VERSION 5.8 ;
BUSBITCHARS "[]" ;
DIVIDERCHAR "/" ;
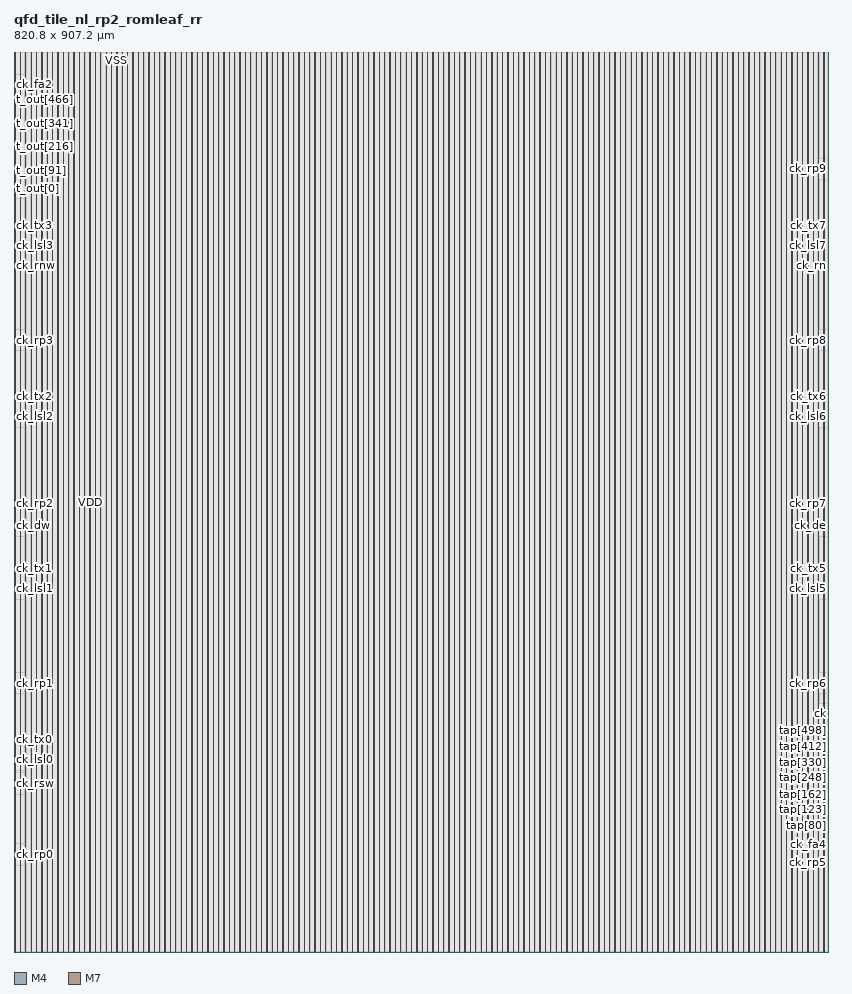
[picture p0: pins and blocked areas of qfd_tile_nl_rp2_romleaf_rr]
MACRO qfd_tile_nl_rp2_romleaf_rr
  CLASS BLOCK ;
  ORIGIN 0 0 ;
  FOREIGN qfd_tile_nl_rp2_romleaf_rr 0 0 ;
  SIZE 820.8 BY 907.2 ;
  SYMMETRY X Y ;
  PIN ck_rp0
    DIRECTION INPUT ;
    USE CLOCK ;
    PORT
      LAYER M4 ;
        RECT 0.000 98.304 0.192 98.328 ;
    END
  END ck_rp0
  PIN ck_rsw
    DIRECTION INPUT ;
    USE CLOCK ;
    PORT
      LAYER M4 ;
        RECT 0.000 170.016 0.192 170.040 ;
    END
  END ck_rsw
  PIN ck_lsl0
    DIRECTION INPUT ;
    USE CLOCK ;
    PORT
      LAYER M4 ;
        RECT 0.000 193.824 0.192 193.848 ;
    END
  END ck_lsl0
  PIN ck_tx0
    DIRECTION INPUT ;
    USE CLOCK ;
    PORT
      LAYER M4 ;
        RECT 0.000 205.824 0.192 205.848 ;
    END
  END ck_tx0
  PIN ck_rp1
    DIRECTION INPUT ;
    USE CLOCK ;
    PORT
      LAYER M4 ;
        RECT 0.000 271.104 0.192 271.128 ;
    END
  END ck_rp1
  PIN ck_lsl1
    DIRECTION INPUT ;
    USE CLOCK ;
    PORT
      LAYER M4 ;
        RECT 0.000 366.624 0.192 366.648 ;
    END
  END ck_lsl1
  PIN ck_tx1
    DIRECTION INPUT ;
    USE CLOCK ;
    PORT
      LAYER M4 ;
        RECT 0.000 378.624 0.192 378.648 ;
    END
  END ck_tx1
  PIN ck_dw
    DIRECTION INPUT ;
    USE CLOCK ;
    PORT
      LAYER M4 ;
        RECT 0.000 429.984 0.192 430.008 ;
    END
  END ck_dw
  PIN ck_rp2
    DIRECTION INPUT ;
    USE CLOCK ;
    PORT
      LAYER M4 ;
        RECT 0.000 443.904 0.192 443.928 ;
    END
  END ck_rp2
  PIN ck_lsl2
    DIRECTION INPUT ;
    USE CLOCK ;
    PORT
      LAYER M4 ;
        RECT 0.000 539.424 0.192 539.448 ;
    END
  END ck_lsl2
  PIN ck_tx2
    DIRECTION INPUT ;
    USE CLOCK ;
    PORT
      LAYER M4 ;
        RECT 0.000 551.424 0.192 551.448 ;
    END
  END ck_tx2
  PIN ck_rp3
    DIRECTION INPUT ;
    USE CLOCK ;
    PORT
      LAYER M4 ;
        RECT 0.000 616.704 0.192 616.728 ;
    END
  END ck_rp3
  PIN ck_rnw
    DIRECTION INPUT ;
    USE CLOCK ;
    PORT
      LAYER M4 ;
        RECT 0.000 700.032 0.192 700.056 ;
    END
  END ck_rnw
  PIN ck_lsl3
    DIRECTION INPUT ;
    USE CLOCK ;
    PORT
      LAYER M4 ;
        RECT 0.000 712.224 0.192 712.248 ;
    END
  END ck_lsl3
  PIN ck_tx3
    DIRECTION INPUT ;
    USE CLOCK ;
    PORT
      LAYER M4 ;
        RECT 0.000 724.224 0.192 724.248 ;
    END
  END ck_tx3
  PIN t_out[0]
    DIRECTION OUTPUT ;
    USE SIGNAL ;
    PORT
      LAYER M4 ;
        RECT 0.000 770.016 0.192 770.040 ;
    END
  END t_out[0]
  PIN t_out[1]
    DIRECTION OUTPUT ;
    USE SIGNAL ;
    PORT
      LAYER M4 ;
        RECT 0.000 770.208 0.192 770.232 ;
    END
  END t_out[1]
  PIN t_out[2]
    DIRECTION OUTPUT ;
    USE SIGNAL ;
    PORT
      LAYER M4 ;
        RECT 0.000 770.400 0.192 770.424 ;
    END
  END t_out[2]
  PIN t_out[3]
    DIRECTION OUTPUT ;
    USE SIGNAL ;
    PORT
      LAYER M4 ;
        RECT 0.000 770.592 0.192 770.616 ;
    END
  END t_out[3]
  PIN t_out[4]
    DIRECTION OUTPUT ;
    USE SIGNAL ;
    PORT
      LAYER M4 ;
        RECT 0.000 770.784 0.192 770.808 ;
    END
  END t_out[4]
  PIN t_out[5]
    DIRECTION OUTPUT ;
    USE SIGNAL ;
    PORT
      LAYER M4 ;
        RECT 0.000 770.976 0.192 771.000 ;
    END
  END t_out[5]
  PIN t_out[6]
    DIRECTION OUTPUT ;
    USE SIGNAL ;
    PORT
      LAYER M4 ;
        RECT 0.000 771.168 0.192 771.192 ;
    END
  END t_out[6]
  PIN t_out[7]
    DIRECTION OUTPUT ;
    USE SIGNAL ;
    PORT
      LAYER M4 ;
        RECT 0.000 771.360 0.192 771.384 ;
    END
  END t_out[7]
  PIN t_out[8]
    DIRECTION OUTPUT ;
    USE SIGNAL ;
    PORT
      LAYER M4 ;
        RECT 0.000 771.552 0.192 771.576 ;
    END
  END t_out[8]
  PIN t_out[9]
    DIRECTION OUTPUT ;
    USE SIGNAL ;
    PORT
      LAYER M4 ;
        RECT 0.000 771.744 0.192 771.768 ;
    END
  END t_out[9]
  PIN t_out[10]
    DIRECTION OUTPUT ;
    USE SIGNAL ;
    PORT
      LAYER M4 ;
        RECT 0.000 771.936 0.192 771.960 ;
    END
  END t_out[10]
  PIN t_out[11]
    DIRECTION OUTPUT ;
    USE SIGNAL ;
    PORT
      LAYER M4 ;
        RECT 0.000 772.128 0.192 772.152 ;
    END
  END t_out[11]
  PIN t_out[12]
    DIRECTION OUTPUT ;
    USE SIGNAL ;
    PORT
      LAYER M4 ;
        RECT 0.000 772.320 0.192 772.344 ;
    END
  END t_out[12]
  PIN t_out[13]
    DIRECTION OUTPUT ;
    USE SIGNAL ;
    PORT
      LAYER M4 ;
        RECT 0.000 772.512 0.192 772.536 ;
    END
  END t_out[13]
  PIN t_out[14]
    DIRECTION OUTPUT ;
    USE SIGNAL ;
    PORT
      LAYER M4 ;
        RECT 0.000 772.704 0.192 772.728 ;
    END
  END t_out[14]
  PIN t_out[15]
    DIRECTION OUTPUT ;
    USE SIGNAL ;
    PORT
      LAYER M4 ;
        RECT 0.000 772.896 0.192 772.920 ;
    END
  END t_out[15]
  PIN t_out[16]
    DIRECTION OUTPUT ;
    USE SIGNAL ;
    PORT
      LAYER M4 ;
        RECT 0.000 773.088 0.192 773.112 ;
    END
  END t_out[16]
  PIN t_out[17]
    DIRECTION OUTPUT ;
    USE SIGNAL ;
    PORT
      LAYER M4 ;
        RECT 0.000 773.280 0.192 773.304 ;
    END
  END t_out[17]
  PIN t_out[18]
    DIRECTION OUTPUT ;
    USE SIGNAL ;
    PORT
      LAYER M4 ;
        RECT 0.000 773.472 0.192 773.496 ;
    END
  END t_out[18]
  PIN t_out[19]
    DIRECTION OUTPUT ;
    USE SIGNAL ;
    PORT
      LAYER M4 ;
        RECT 0.000 773.664 0.192 773.688 ;
    END
  END t_out[19]
  PIN t_out[20]
    DIRECTION OUTPUT ;
    USE SIGNAL ;
    PORT
      LAYER M4 ;
        RECT 0.000 773.856 0.192 773.880 ;
    END
  END t_out[20]
  PIN t_out[21]
    DIRECTION OUTPUT ;
    USE SIGNAL ;
    PORT
      LAYER M4 ;
        RECT 0.000 774.048 0.192 774.072 ;
    END
  END t_out[21]
  PIN t_out[22]
    DIRECTION OUTPUT ;
    USE SIGNAL ;
    PORT
      LAYER M4 ;
        RECT 0.000 774.240 0.192 774.264 ;
    END
  END t_out[22]
  PIN t_out[23]
    DIRECTION OUTPUT ;
    USE SIGNAL ;
    PORT
      LAYER M4 ;
        RECT 0.000 774.432 0.192 774.456 ;
    END
  END t_out[23]
  PIN t_out[24]
    DIRECTION OUTPUT ;
    USE SIGNAL ;
    PORT
      LAYER M4 ;
        RECT 0.000 774.624 0.192 774.648 ;
    END
  END t_out[24]
  PIN t_out[25]
    DIRECTION OUTPUT ;
    USE SIGNAL ;
    PORT
      LAYER M4 ;
        RECT 0.000 774.816 0.192 774.840 ;
    END
  END t_out[25]
  PIN t_out[26]
    DIRECTION OUTPUT ;
    USE SIGNAL ;
    PORT
      LAYER M4 ;
        RECT 0.000 775.008 0.192 775.032 ;
    END
  END t_out[26]
  PIN t_out[27]
    DIRECTION OUTPUT ;
    USE SIGNAL ;
    PORT
      LAYER M4 ;
        RECT 0.000 775.200 0.192 775.224 ;
    END
  END t_out[27]
  PIN t_out[28]
    DIRECTION OUTPUT ;
    USE SIGNAL ;
    PORT
      LAYER M4 ;
        RECT 0.000 775.392 0.192 775.416 ;
    END
  END t_out[28]
  PIN t_out[29]
    DIRECTION OUTPUT ;
    USE SIGNAL ;
    PORT
      LAYER M4 ;
        RECT 0.000 775.584 0.192 775.608 ;
    END
  END t_out[29]
  PIN t_out[30]
    DIRECTION OUTPUT ;
    USE SIGNAL ;
    PORT
      LAYER M4 ;
        RECT 0.000 775.776 0.192 775.800 ;
    END
  END t_out[30]
  PIN t_out[31]
    DIRECTION OUTPUT ;
    USE SIGNAL ;
    PORT
      LAYER M4 ;
        RECT 0.000 775.968 0.192 775.992 ;
    END
  END t_out[31]
  PIN t_out[32]
    DIRECTION OUTPUT ;
    USE SIGNAL ;
    PORT
      LAYER M4 ;
        RECT 0.000 776.160 0.192 776.184 ;
    END
  END t_out[32]
  PIN t_out[33]
    DIRECTION OUTPUT ;
    USE SIGNAL ;
    PORT
      LAYER M4 ;
        RECT 0.000 776.352 0.192 776.376 ;
    END
  END t_out[33]
  PIN t_out[34]
    DIRECTION OUTPUT ;
    USE SIGNAL ;
    PORT
      LAYER M4 ;
        RECT 0.000 776.544 0.192 776.568 ;
    END
  END t_out[34]
  PIN t_out[35]
    DIRECTION OUTPUT ;
    USE SIGNAL ;
    PORT
      LAYER M4 ;
        RECT 0.000 776.736 0.192 776.760 ;
    END
  END t_out[35]
  PIN t_out[36]
    DIRECTION OUTPUT ;
    USE SIGNAL ;
    PORT
      LAYER M4 ;
        RECT 0.000 776.928 0.192 776.952 ;
    END
  END t_out[36]
  PIN t_out[37]
    DIRECTION OUTPUT ;
    USE SIGNAL ;
    PORT
      LAYER M4 ;
        RECT 0.000 777.120 0.192 777.144 ;
    END
  END t_out[37]
  PIN t_out[38]
    DIRECTION OUTPUT ;
    USE SIGNAL ;
    PORT
      LAYER M4 ;
        RECT 0.000 777.312 0.192 777.336 ;
    END
  END t_out[38]
  PIN t_out[39]
    DIRECTION OUTPUT ;
    USE SIGNAL ;
    PORT
      LAYER M4 ;
        RECT 0.000 777.504 0.192 777.528 ;
    END
  END t_out[39]
  PIN t_out[40]
    DIRECTION OUTPUT ;
    USE SIGNAL ;
    PORT
      LAYER M4 ;
        RECT 0.000 777.696 0.192 777.720 ;
    END
  END t_out[40]
  PIN t_out[41]
    DIRECTION OUTPUT ;
    USE SIGNAL ;
    PORT
      LAYER M4 ;
        RECT 0.000 777.888 0.192 777.912 ;
    END
  END t_out[41]
  PIN t_out[42]
    DIRECTION OUTPUT ;
    USE SIGNAL ;
    PORT
      LAYER M4 ;
        RECT 0.000 778.080 0.192 778.104 ;
    END
  END t_out[42]
  PIN t_out[43]
    DIRECTION OUTPUT ;
    USE SIGNAL ;
    PORT
      LAYER M4 ;
        RECT 0.000 778.272 0.192 778.296 ;
    END
  END t_out[43]
  PIN t_out[44]
    DIRECTION OUTPUT ;
    USE SIGNAL ;
    PORT
      LAYER M4 ;
        RECT 0.000 778.464 0.192 778.488 ;
    END
  END t_out[44]
  PIN t_out[45]
    DIRECTION OUTPUT ;
    USE SIGNAL ;
    PORT
      LAYER M4 ;
        RECT 0.000 778.656 0.192 778.680 ;
    END
  END t_out[45]
  PIN t_out[46]
    DIRECTION OUTPUT ;
    USE SIGNAL ;
    PORT
      LAYER M4 ;
        RECT 0.000 778.848 0.192 778.872 ;
    END
  END t_out[46]
  PIN t_out[47]
    DIRECTION OUTPUT ;
    USE SIGNAL ;
    PORT
      LAYER M4 ;
        RECT 0.000 779.040 0.192 779.064 ;
    END
  END t_out[47]
  PIN t_out[48]
    DIRECTION OUTPUT ;
    USE SIGNAL ;
    PORT
      LAYER M4 ;
        RECT 0.000 779.232 0.192 779.256 ;
    END
  END t_out[48]
  PIN t_out[49]
    DIRECTION OUTPUT ;
    USE SIGNAL ;
    PORT
      LAYER M4 ;
        RECT 0.000 779.424 0.192 779.448 ;
    END
  END t_out[49]
  PIN t_out[50]
    DIRECTION OUTPUT ;
    USE SIGNAL ;
    PORT
      LAYER M4 ;
        RECT 0.000 779.616 0.192 779.640 ;
    END
  END t_out[50]
  PIN t_out[51]
    DIRECTION OUTPUT ;
    USE SIGNAL ;
    PORT
      LAYER M4 ;
        RECT 0.000 779.808 0.192 779.832 ;
    END
  END t_out[51]
  PIN t_out[52]
    DIRECTION OUTPUT ;
    USE SIGNAL ;
    PORT
      LAYER M4 ;
        RECT 0.000 780.000 0.192 780.024 ;
    END
  END t_out[52]
  PIN t_out[53]
    DIRECTION OUTPUT ;
    USE SIGNAL ;
    PORT
      LAYER M4 ;
        RECT 0.000 780.192 0.192 780.216 ;
    END
  END t_out[53]
  PIN t_out[54]
    DIRECTION OUTPUT ;
    USE SIGNAL ;
    PORT
      LAYER M4 ;
        RECT 0.000 780.384 0.192 780.408 ;
    END
  END t_out[54]
  PIN t_out[55]
    DIRECTION OUTPUT ;
    USE SIGNAL ;
    PORT
      LAYER M4 ;
        RECT 0.000 780.576 0.192 780.600 ;
    END
  END t_out[55]
  PIN t_out[56]
    DIRECTION OUTPUT ;
    USE SIGNAL ;
    PORT
      LAYER M4 ;
        RECT 0.000 780.768 0.192 780.792 ;
    END
  END t_out[56]
  PIN t_out[57]
    DIRECTION OUTPUT ;
    USE SIGNAL ;
    PORT
      LAYER M4 ;
        RECT 0.000 780.960 0.192 780.984 ;
    END
  END t_out[57]
  PIN t_out[58]
    DIRECTION OUTPUT ;
    USE SIGNAL ;
    PORT
      LAYER M4 ;
        RECT 0.000 781.152 0.192 781.176 ;
    END
  END t_out[58]
  PIN t_out[59]
    DIRECTION OUTPUT ;
    USE SIGNAL ;
    PORT
      LAYER M4 ;
        RECT 0.000 781.344 0.192 781.368 ;
    END
  END t_out[59]
  PIN t_out[60]
    DIRECTION OUTPUT ;
    USE SIGNAL ;
    PORT
      LAYER M4 ;
        RECT 0.000 781.536 0.192 781.560 ;
    END
  END t_out[60]
  PIN t_out[61]
    DIRECTION OUTPUT ;
    USE SIGNAL ;
    PORT
      LAYER M4 ;
        RECT 0.000 781.728 0.192 781.752 ;
    END
  END t_out[61]
  PIN t_out[62]
    DIRECTION OUTPUT ;
    USE SIGNAL ;
    PORT
      LAYER M4 ;
        RECT 0.000 781.920 0.192 781.944 ;
    END
  END t_out[62]
  PIN t_out[63]
    DIRECTION OUTPUT ;
    USE SIGNAL ;
    PORT
      LAYER M4 ;
        RECT 0.000 782.112 0.192 782.136 ;
    END
  END t_out[63]
  PIN t_out[64]
    DIRECTION OUTPUT ;
    USE SIGNAL ;
    PORT
      LAYER M4 ;
        RECT 0.000 782.304 0.192 782.328 ;
    END
  END t_out[64]
  PIN t_out[65]
    DIRECTION OUTPUT ;
    USE SIGNAL ;
    PORT
      LAYER M4 ;
        RECT 0.000 782.496 0.192 782.520 ;
    END
  END t_out[65]
  PIN t_out[66]
    DIRECTION OUTPUT ;
    USE SIGNAL ;
    PORT
      LAYER M4 ;
        RECT 0.000 782.688 0.192 782.712 ;
    END
  END t_out[66]
  PIN t_out[67]
    DIRECTION OUTPUT ;
    USE SIGNAL ;
    PORT
      LAYER M4 ;
        RECT 0.000 782.880 0.192 782.904 ;
    END
  END t_out[67]
  PIN t_out[68]
    DIRECTION OUTPUT ;
    USE SIGNAL ;
    PORT
      LAYER M4 ;
        RECT 0.000 783.072 0.192 783.096 ;
    END
  END t_out[68]
  PIN t_out[69]
    DIRECTION OUTPUT ;
    USE SIGNAL ;
    PORT
      LAYER M4 ;
        RECT 0.000 783.264 0.192 783.288 ;
    END
  END t_out[69]
  PIN t_out[70]
    DIRECTION OUTPUT ;
    USE SIGNAL ;
    PORT
      LAYER M4 ;
        RECT 0.000 783.456 0.192 783.480 ;
    END
  END t_out[70]
  PIN t_out[71]
    DIRECTION OUTPUT ;
    USE SIGNAL ;
    PORT
      LAYER M4 ;
        RECT 0.000 783.648 0.192 783.672 ;
    END
  END t_out[71]
  PIN t_out[72]
    DIRECTION OUTPUT ;
    USE SIGNAL ;
    PORT
      LAYER M4 ;
        RECT 0.000 783.840 0.192 783.864 ;
    END
  END t_out[72]
  PIN t_out[73]
    DIRECTION OUTPUT ;
    USE SIGNAL ;
    PORT
      LAYER M4 ;
        RECT 0.000 784.032 0.192 784.056 ;
    END
  END t_out[73]
  PIN t_out[74]
    DIRECTION OUTPUT ;
    USE SIGNAL ;
    PORT
      LAYER M4 ;
        RECT 0.000 784.224 0.192 784.248 ;
    END
  END t_out[74]
  PIN t_out[75]
    DIRECTION OUTPUT ;
    USE SIGNAL ;
    PORT
      LAYER M4 ;
        RECT 0.000 784.416 0.192 784.440 ;
    END
  END t_out[75]
  PIN t_out[76]
    DIRECTION OUTPUT ;
    USE SIGNAL ;
    PORT
      LAYER M4 ;
        RECT 0.000 784.608 0.192 784.632 ;
    END
  END t_out[76]
  PIN t_out[77]
    DIRECTION OUTPUT ;
    USE SIGNAL ;
    PORT
      LAYER M4 ;
        RECT 0.000 784.800 0.192 784.824 ;
    END
  END t_out[77]
  PIN t_out[78]
    DIRECTION OUTPUT ;
    USE SIGNAL ;
    PORT
      LAYER M4 ;
        RECT 0.000 784.992 0.192 785.016 ;
    END
  END t_out[78]
  PIN t_out[79]
    DIRECTION OUTPUT ;
    USE SIGNAL ;
    PORT
      LAYER M4 ;
        RECT 0.000 785.184 0.192 785.208 ;
    END
  END t_out[79]
  PIN t_out[80]
    DIRECTION OUTPUT ;
    USE SIGNAL ;
    PORT
      LAYER M4 ;
        RECT 0.000 785.376 0.192 785.400 ;
    END
  END t_out[80]
  PIN t_out[81]
    DIRECTION OUTPUT ;
    USE SIGNAL ;
    PORT
      LAYER M4 ;
        RECT 0.000 785.568 0.192 785.592 ;
    END
  END t_out[81]
  PIN t_out[82]
    DIRECTION OUTPUT ;
    USE SIGNAL ;
    PORT
      LAYER M4 ;
        RECT 0.000 785.760 0.192 785.784 ;
    END
  END t_out[82]
  PIN t_out[83]
    DIRECTION OUTPUT ;
    USE SIGNAL ;
    PORT
      LAYER M4 ;
        RECT 0.000 785.952 0.192 785.976 ;
    END
  END t_out[83]
  PIN t_out[84]
    DIRECTION OUTPUT ;
    USE SIGNAL ;
    PORT
      LAYER M4 ;
        RECT 0.000 786.144 0.192 786.168 ;
    END
  END t_out[84]
  PIN t_out[85]
    DIRECTION OUTPUT ;
    USE SIGNAL ;
    PORT
      LAYER M4 ;
        RECT 0.000 786.336 0.192 786.360 ;
    END
  END t_out[85]
  PIN t_out[86]
    DIRECTION OUTPUT ;
    USE SIGNAL ;
    PORT
      LAYER M4 ;
        RECT 0.000 786.528 0.192 786.552 ;
    END
  END t_out[86]
  PIN t_out[87]
    DIRECTION OUTPUT ;
    USE SIGNAL ;
    PORT
      LAYER M4 ;
        RECT 0.000 786.720 0.192 786.744 ;
    END
  END t_out[87]
  PIN t_out[88]
    DIRECTION OUTPUT ;
    USE SIGNAL ;
    PORT
      LAYER M4 ;
        RECT 0.000 786.912 0.192 786.936 ;
    END
  END t_out[88]
  PIN t_out[89]
    DIRECTION OUTPUT ;
    USE SIGNAL ;
    PORT
      LAYER M4 ;
        RECT 0.000 787.104 0.192 787.128 ;
    END
  END t_out[89]
  PIN t_out[90]
    DIRECTION OUTPUT ;
    USE SIGNAL ;
    PORT
      LAYER M4 ;
        RECT 0.000 787.296 0.192 787.320 ;
    END
  END t_out[90]
  PIN t_out[91]
    DIRECTION OUTPUT ;
    USE SIGNAL ;
    PORT
      LAYER M4 ;
        RECT 0.000 787.488 0.192 787.512 ;
    END
  END t_out[91]
  PIN t_out[92]
    DIRECTION OUTPUT ;
    USE SIGNAL ;
    PORT
      LAYER M4 ;
        RECT 0.000 787.680 0.192 787.704 ;
    END
  END t_out[92]
  PIN t_out[93]
    DIRECTION OUTPUT ;
    USE SIGNAL ;
    PORT
      LAYER M4 ;
        RECT 0.000 787.872 0.192 787.896 ;
    END
  END t_out[93]
  PIN t_out[94]
    DIRECTION OUTPUT ;
    USE SIGNAL ;
    PORT
      LAYER M4 ;
        RECT 0.000 788.064 0.192 788.088 ;
    END
  END t_out[94]
  PIN t_out[95]
    DIRECTION OUTPUT ;
    USE SIGNAL ;
    PORT
      LAYER M4 ;
        RECT 0.000 788.256 0.192 788.280 ;
    END
  END t_out[95]
  PIN t_out[96]
    DIRECTION OUTPUT ;
    USE SIGNAL ;
    PORT
      LAYER M4 ;
        RECT 0.000 788.448 0.192 788.472 ;
    END
  END t_out[96]
  PIN t_out[97]
    DIRECTION OUTPUT ;
    USE SIGNAL ;
    PORT
      LAYER M4 ;
        RECT 0.000 788.640 0.192 788.664 ;
    END
  END t_out[97]
  PIN t_out[98]
    DIRECTION OUTPUT ;
    USE SIGNAL ;
    PORT
      LAYER M4 ;
        RECT 0.000 788.832 0.192 788.856 ;
    END
  END t_out[98]
  PIN t_out[99]
    DIRECTION OUTPUT ;
    USE SIGNAL ;
    PORT
      LAYER M4 ;
        RECT 0.000 789.024 0.192 789.048 ;
    END
  END t_out[99]
  PIN t_out[100]
    DIRECTION OUTPUT ;
    USE SIGNAL ;
    PORT
      LAYER M4 ;
        RECT 0.000 789.216 0.192 789.240 ;
    END
  END t_out[100]
  PIN t_out[101]
    DIRECTION OUTPUT ;
    USE SIGNAL ;
    PORT
      LAYER M4 ;
        RECT 0.000 789.408 0.192 789.432 ;
    END
  END t_out[101]
  PIN t_out[102]
    DIRECTION OUTPUT ;
    USE SIGNAL ;
    PORT
      LAYER M4 ;
        RECT 0.000 789.600 0.192 789.624 ;
    END
  END t_out[102]
  PIN t_out[103]
    DIRECTION OUTPUT ;
    USE SIGNAL ;
    PORT
      LAYER M4 ;
        RECT 0.000 789.792 0.192 789.816 ;
    END
  END t_out[103]
  PIN t_out[104]
    DIRECTION OUTPUT ;
    USE SIGNAL ;
    PORT
      LAYER M4 ;
        RECT 0.000 789.984 0.192 790.008 ;
    END
  END t_out[104]
  PIN t_out[105]
    DIRECTION OUTPUT ;
    USE SIGNAL ;
    PORT
      LAYER M4 ;
        RECT 0.000 790.176 0.192 790.200 ;
    END
  END t_out[105]
  PIN t_out[106]
    DIRECTION OUTPUT ;
    USE SIGNAL ;
    PORT
      LAYER M4 ;
        RECT 0.000 790.368 0.192 790.392 ;
    END
  END t_out[106]
  PIN t_out[107]
    DIRECTION OUTPUT ;
    USE SIGNAL ;
    PORT
      LAYER M4 ;
        RECT 0.000 790.560 0.192 790.584 ;
    END
  END t_out[107]
  PIN t_out[108]
    DIRECTION OUTPUT ;
    USE SIGNAL ;
    PORT
      LAYER M4 ;
        RECT 0.000 790.752 0.192 790.776 ;
    END
  END t_out[108]
  PIN t_out[109]
    DIRECTION OUTPUT ;
    USE SIGNAL ;
    PORT
      LAYER M4 ;
        RECT 0.000 790.944 0.192 790.968 ;
    END
  END t_out[109]
  PIN t_out[110]
    DIRECTION OUTPUT ;
    USE SIGNAL ;
    PORT
      LAYER M4 ;
        RECT 0.000 791.136 0.192 791.160 ;
    END
  END t_out[110]
  PIN t_out[111]
    DIRECTION OUTPUT ;
    USE SIGNAL ;
    PORT
      LAYER M4 ;
        RECT 0.000 791.328 0.192 791.352 ;
    END
  END t_out[111]
  PIN t_out[112]
    DIRECTION OUTPUT ;
    USE SIGNAL ;
    PORT
      LAYER M4 ;
        RECT 0.000 791.520 0.192 791.544 ;
    END
  END t_out[112]
  PIN t_out[113]
    DIRECTION OUTPUT ;
    USE SIGNAL ;
    PORT
      LAYER M4 ;
        RECT 0.000 791.712 0.192 791.736 ;
    END
  END t_out[113]
  PIN t_out[114]
    DIRECTION OUTPUT ;
    USE SIGNAL ;
    PORT
      LAYER M4 ;
        RECT 0.000 791.904 0.192 791.928 ;
    END
  END t_out[114]
  PIN t_out[115]
    DIRECTION OUTPUT ;
    USE SIGNAL ;
    PORT
      LAYER M4 ;
        RECT 0.000 792.096 0.192 792.120 ;
    END
  END t_out[115]
  PIN t_out[116]
    DIRECTION OUTPUT ;
    USE SIGNAL ;
    PORT
      LAYER M4 ;
        RECT 0.000 792.288 0.192 792.312 ;
    END
  END t_out[116]
  PIN t_out[117]
    DIRECTION OUTPUT ;
    USE SIGNAL ;
    PORT
      LAYER M4 ;
        RECT 0.000 792.480 0.192 792.504 ;
    END
  END t_out[117]
  PIN t_out[118]
    DIRECTION OUTPUT ;
    USE SIGNAL ;
    PORT
      LAYER M4 ;
        RECT 0.000 792.672 0.192 792.696 ;
    END
  END t_out[118]
  PIN t_out[119]
    DIRECTION OUTPUT ;
    USE SIGNAL ;
    PORT
      LAYER M4 ;
        RECT 0.000 792.864 0.192 792.888 ;
    END
  END t_out[119]
  PIN t_out[120]
    DIRECTION OUTPUT ;
    USE SIGNAL ;
    PORT
      LAYER M4 ;
        RECT 0.000 793.056 0.192 793.080 ;
    END
  END t_out[120]
  PIN t_out[121]
    DIRECTION OUTPUT ;
    USE SIGNAL ;
    PORT
      LAYER M4 ;
        RECT 0.000 793.248 0.192 793.272 ;
    END
  END t_out[121]
  PIN t_out[122]
    DIRECTION OUTPUT ;
    USE SIGNAL ;
    PORT
      LAYER M4 ;
        RECT 0.000 793.440 0.192 793.464 ;
    END
  END t_out[122]
  PIN t_out[123]
    DIRECTION OUTPUT ;
    USE SIGNAL ;
    PORT
      LAYER M4 ;
        RECT 0.000 793.632 0.192 793.656 ;
    END
  END t_out[123]
  PIN t_out[124]
    DIRECTION OUTPUT ;
    USE SIGNAL ;
    PORT
      LAYER M4 ;
        RECT 0.000 793.824 0.192 793.848 ;
    END
  END t_out[124]
  PIN t_out[125]
    DIRECTION OUTPUT ;
    USE SIGNAL ;
    PORT
      LAYER M4 ;
        RECT 0.000 794.016 0.192 794.040 ;
    END
  END t_out[125]
  PIN t_out[126]
    DIRECTION OUTPUT ;
    USE SIGNAL ;
    PORT
      LAYER M4 ;
        RECT 0.000 794.208 0.192 794.232 ;
    END
  END t_out[126]
  PIN t_out[127]
    DIRECTION OUTPUT ;
    USE SIGNAL ;
    PORT
      LAYER M4 ;
        RECT 0.000 794.400 0.192 794.424 ;
    END
  END t_out[127]
  PIN t_out[128]
    DIRECTION OUTPUT ;
    USE SIGNAL ;
    PORT
      LAYER M4 ;
        RECT 0.000 794.592 0.192 794.616 ;
    END
  END t_out[128]
  PIN t_out[129]
    DIRECTION OUTPUT ;
    USE SIGNAL ;
    PORT
      LAYER M4 ;
        RECT 0.000 794.784 0.192 794.808 ;
    END
  END t_out[129]
  PIN t_out[130]
    DIRECTION OUTPUT ;
    USE SIGNAL ;
    PORT
      LAYER M4 ;
        RECT 0.000 794.976 0.192 795.000 ;
    END
  END t_out[130]
  PIN t_out[131]
    DIRECTION OUTPUT ;
    USE SIGNAL ;
    PORT
      LAYER M4 ;
        RECT 0.000 795.168 0.192 795.192 ;
    END
  END t_out[131]
  PIN t_out[132]
    DIRECTION OUTPUT ;
    USE SIGNAL ;
    PORT
      LAYER M4 ;
        RECT 0.000 795.360 0.192 795.384 ;
    END
  END t_out[132]
  PIN t_out[133]
    DIRECTION OUTPUT ;
    USE SIGNAL ;
    PORT
      LAYER M4 ;
        RECT 0.000 795.552 0.192 795.576 ;
    END
  END t_out[133]
  PIN t_out[134]
    DIRECTION OUTPUT ;
    USE SIGNAL ;
    PORT
      LAYER M4 ;
        RECT 0.000 795.744 0.192 795.768 ;
    END
  END t_out[134]
  PIN t_out[135]
    DIRECTION OUTPUT ;
    USE SIGNAL ;
    PORT
      LAYER M4 ;
        RECT 0.000 795.936 0.192 795.960 ;
    END
  END t_out[135]
  PIN t_out[136]
    DIRECTION OUTPUT ;
    USE SIGNAL ;
    PORT
      LAYER M4 ;
        RECT 0.000 796.128 0.192 796.152 ;
    END
  END t_out[136]
  PIN t_out[137]
    DIRECTION OUTPUT ;
    USE SIGNAL ;
    PORT
      LAYER M4 ;
        RECT 0.000 796.320 0.192 796.344 ;
    END
  END t_out[137]
  PIN t_out[138]
    DIRECTION OUTPUT ;
    USE SIGNAL ;
    PORT
      LAYER M4 ;
        RECT 0.000 796.512 0.192 796.536 ;
    END
  END t_out[138]
  PIN t_out[139]
    DIRECTION OUTPUT ;
    USE SIGNAL ;
    PORT
      LAYER M4 ;
        RECT 0.000 796.704 0.192 796.728 ;
    END
  END t_out[139]
  PIN t_out[140]
    DIRECTION OUTPUT ;
    USE SIGNAL ;
    PORT
      LAYER M4 ;
        RECT 0.000 796.896 0.192 796.920 ;
    END
  END t_out[140]
  PIN t_out[141]
    DIRECTION OUTPUT ;
    USE SIGNAL ;
    PORT
      LAYER M4 ;
        RECT 0.000 797.088 0.192 797.112 ;
    END
  END t_out[141]
  PIN t_out[142]
    DIRECTION OUTPUT ;
    USE SIGNAL ;
    PORT
      LAYER M4 ;
        RECT 0.000 797.280 0.192 797.304 ;
    END
  END t_out[142]
  PIN t_out[143]
    DIRECTION OUTPUT ;
    USE SIGNAL ;
    PORT
      LAYER M4 ;
        RECT 0.000 797.472 0.192 797.496 ;
    END
  END t_out[143]
  PIN t_out[144]
    DIRECTION OUTPUT ;
    USE SIGNAL ;
    PORT
      LAYER M4 ;
        RECT 0.000 797.664 0.192 797.688 ;
    END
  END t_out[144]
  PIN t_out[145]
    DIRECTION OUTPUT ;
    USE SIGNAL ;
    PORT
      LAYER M4 ;
        RECT 0.000 797.856 0.192 797.880 ;
    END
  END t_out[145]
  PIN t_out[146]
    DIRECTION OUTPUT ;
    USE SIGNAL ;
    PORT
      LAYER M4 ;
        RECT 0.000 798.048 0.192 798.072 ;
    END
  END t_out[146]
  PIN t_out[147]
    DIRECTION OUTPUT ;
    USE SIGNAL ;
    PORT
      LAYER M4 ;
        RECT 0.000 798.240 0.192 798.264 ;
    END
  END t_out[147]
  PIN t_out[148]
    DIRECTION OUTPUT ;
    USE SIGNAL ;
    PORT
      LAYER M4 ;
        RECT 0.000 798.432 0.192 798.456 ;
    END
  END t_out[148]
  PIN t_out[149]
    DIRECTION OUTPUT ;
    USE SIGNAL ;
    PORT
      LAYER M4 ;
        RECT 0.000 798.624 0.192 798.648 ;
    END
  END t_out[149]
  PIN t_out[150]
    DIRECTION OUTPUT ;
    USE SIGNAL ;
    PORT
      LAYER M4 ;
        RECT 0.000 798.816 0.192 798.840 ;
    END
  END t_out[150]
  PIN t_out[151]
    DIRECTION OUTPUT ;
    USE SIGNAL ;
    PORT
      LAYER M4 ;
        RECT 0.000 799.008 0.192 799.032 ;
    END
  END t_out[151]
  PIN t_out[152]
    DIRECTION OUTPUT ;
    USE SIGNAL ;
    PORT
      LAYER M4 ;
        RECT 0.000 799.200 0.192 799.224 ;
    END
  END t_out[152]
  PIN t_out[153]
    DIRECTION OUTPUT ;
    USE SIGNAL ;
    PORT
      LAYER M4 ;
        RECT 0.000 799.392 0.192 799.416 ;
    END
  END t_out[153]
  PIN t_out[154]
    DIRECTION OUTPUT ;
    USE SIGNAL ;
    PORT
      LAYER M4 ;
        RECT 0.000 799.584 0.192 799.608 ;
    END
  END t_out[154]
  PIN t_out[155]
    DIRECTION OUTPUT ;
    USE SIGNAL ;
    PORT
      LAYER M4 ;
        RECT 0.000 799.776 0.192 799.800 ;
    END
  END t_out[155]
  PIN t_out[156]
    DIRECTION OUTPUT ;
    USE SIGNAL ;
    PORT
      LAYER M4 ;
        RECT 0.000 799.968 0.192 799.992 ;
    END
  END t_out[156]
  PIN t_out[157]
    DIRECTION OUTPUT ;
    USE SIGNAL ;
    PORT
      LAYER M4 ;
        RECT 0.000 800.160 0.192 800.184 ;
    END
  END t_out[157]
  PIN t_out[158]
    DIRECTION OUTPUT ;
    USE SIGNAL ;
    PORT
      LAYER M4 ;
        RECT 0.000 800.352 0.192 800.376 ;
    END
  END t_out[158]
  PIN t_out[159]
    DIRECTION OUTPUT ;
    USE SIGNAL ;
    PORT
      LAYER M4 ;
        RECT 0.000 800.544 0.192 800.568 ;
    END
  END t_out[159]
  PIN t_out[160]
    DIRECTION OUTPUT ;
    USE SIGNAL ;
    PORT
      LAYER M4 ;
        RECT 0.000 800.736 0.192 800.760 ;
    END
  END t_out[160]
  PIN t_out[161]
    DIRECTION OUTPUT ;
    USE SIGNAL ;
    PORT
      LAYER M4 ;
        RECT 0.000 800.928 0.192 800.952 ;
    END
  END t_out[161]
  PIN t_out[162]
    DIRECTION OUTPUT ;
    USE SIGNAL ;
    PORT
      LAYER M4 ;
        RECT 0.000 801.120 0.192 801.144 ;
    END
  END t_out[162]
  PIN t_out[163]
    DIRECTION OUTPUT ;
    USE SIGNAL ;
    PORT
      LAYER M4 ;
        RECT 0.000 801.312 0.192 801.336 ;
    END
  END t_out[163]
  PIN t_out[164]
    DIRECTION OUTPUT ;
    USE SIGNAL ;
    PORT
      LAYER M4 ;
        RECT 0.000 801.504 0.192 801.528 ;
    END
  END t_out[164]
  PIN t_out[165]
    DIRECTION OUTPUT ;
    USE SIGNAL ;
    PORT
      LAYER M4 ;
        RECT 0.000 801.696 0.192 801.720 ;
    END
  END t_out[165]
  PIN t_out[166]
    DIRECTION OUTPUT ;
    USE SIGNAL ;
    PORT
      LAYER M4 ;
        RECT 0.000 801.888 0.192 801.912 ;
    END
  END t_out[166]
  PIN t_out[167]
    DIRECTION OUTPUT ;
    USE SIGNAL ;
    PORT
      LAYER M4 ;
        RECT 0.000 802.080 0.192 802.104 ;
    END
  END t_out[167]
  PIN t_out[168]
    DIRECTION OUTPUT ;
    USE SIGNAL ;
    PORT
      LAYER M4 ;
        RECT 0.000 802.272 0.192 802.296 ;
    END
  END t_out[168]
  PIN t_out[169]
    DIRECTION OUTPUT ;
    USE SIGNAL ;
    PORT
      LAYER M4 ;
        RECT 0.000 802.464 0.192 802.488 ;
    END
  END t_out[169]
  PIN t_out[170]
    DIRECTION OUTPUT ;
    USE SIGNAL ;
    PORT
      LAYER M4 ;
        RECT 0.000 802.656 0.192 802.680 ;
    END
  END t_out[170]
  PIN t_out[171]
    DIRECTION OUTPUT ;
    USE SIGNAL ;
    PORT
      LAYER M4 ;
        RECT 0.000 802.848 0.192 802.872 ;
    END
  END t_out[171]
  PIN t_out[172]
    DIRECTION OUTPUT ;
    USE SIGNAL ;
    PORT
      LAYER M4 ;
        RECT 0.000 803.040 0.192 803.064 ;
    END
  END t_out[172]
  PIN t_out[173]
    DIRECTION OUTPUT ;
    USE SIGNAL ;
    PORT
      LAYER M4 ;
        RECT 0.000 803.232 0.192 803.256 ;
    END
  END t_out[173]
  PIN t_out[174]
    DIRECTION OUTPUT ;
    USE SIGNAL ;
    PORT
      LAYER M4 ;
        RECT 0.000 803.424 0.192 803.448 ;
    END
  END t_out[174]
  PIN t_out[175]
    DIRECTION OUTPUT ;
    USE SIGNAL ;
    PORT
      LAYER M4 ;
        RECT 0.000 803.616 0.192 803.640 ;
    END
  END t_out[175]
  PIN t_out[176]
    DIRECTION OUTPUT ;
    USE SIGNAL ;
    PORT
      LAYER M4 ;
        RECT 0.000 803.808 0.192 803.832 ;
    END
  END t_out[176]
  PIN t_out[177]
    DIRECTION OUTPUT ;
    USE SIGNAL ;
    PORT
      LAYER M4 ;
        RECT 0.000 804.000 0.192 804.024 ;
    END
  END t_out[177]
  PIN t_out[178]
    DIRECTION OUTPUT ;
    USE SIGNAL ;
    PORT
      LAYER M4 ;
        RECT 0.000 804.192 0.192 804.216 ;
    END
  END t_out[178]
  PIN t_out[179]
    DIRECTION OUTPUT ;
    USE SIGNAL ;
    PORT
      LAYER M4 ;
        RECT 0.000 804.384 0.192 804.408 ;
    END
  END t_out[179]
  PIN t_out[180]
    DIRECTION OUTPUT ;
    USE SIGNAL ;
    PORT
      LAYER M4 ;
        RECT 0.000 804.576 0.192 804.600 ;
    END
  END t_out[180]
  PIN t_out[181]
    DIRECTION OUTPUT ;
    USE SIGNAL ;
    PORT
      LAYER M4 ;
        RECT 0.000 804.768 0.192 804.792 ;
    END
  END t_out[181]
  PIN t_out[182]
    DIRECTION OUTPUT ;
    USE SIGNAL ;
    PORT
      LAYER M4 ;
        RECT 0.000 804.960 0.192 804.984 ;
    END
  END t_out[182]
  PIN t_out[183]
    DIRECTION OUTPUT ;
    USE SIGNAL ;
    PORT
      LAYER M4 ;
        RECT 0.000 805.152 0.192 805.176 ;
    END
  END t_out[183]
  PIN t_out[184]
    DIRECTION OUTPUT ;
    USE SIGNAL ;
    PORT
      LAYER M4 ;
        RECT 0.000 805.344 0.192 805.368 ;
    END
  END t_out[184]
  PIN t_out[185]
    DIRECTION OUTPUT ;
    USE SIGNAL ;
    PORT
      LAYER M4 ;
        RECT 0.000 805.536 0.192 805.560 ;
    END
  END t_out[185]
  PIN t_out[186]
    DIRECTION OUTPUT ;
    USE SIGNAL ;
    PORT
      LAYER M4 ;
        RECT 0.000 805.728 0.192 805.752 ;
    END
  END t_out[186]
  PIN t_out[187]
    DIRECTION OUTPUT ;
    USE SIGNAL ;
    PORT
      LAYER M4 ;
        RECT 0.000 805.920 0.192 805.944 ;
    END
  END t_out[187]
  PIN t_out[188]
    DIRECTION OUTPUT ;
    USE SIGNAL ;
    PORT
      LAYER M4 ;
        RECT 0.000 806.112 0.192 806.136 ;
    END
  END t_out[188]
  PIN t_out[189]
    DIRECTION OUTPUT ;
    USE SIGNAL ;
    PORT
      LAYER M4 ;
        RECT 0.000 806.304 0.192 806.328 ;
    END
  END t_out[189]
  PIN t_out[190]
    DIRECTION OUTPUT ;
    USE SIGNAL ;
    PORT
      LAYER M4 ;
        RECT 0.000 806.496 0.192 806.520 ;
    END
  END t_out[190]
  PIN t_out[191]
    DIRECTION OUTPUT ;
    USE SIGNAL ;
    PORT
      LAYER M4 ;
        RECT 0.000 806.688 0.192 806.712 ;
    END
  END t_out[191]
  PIN t_out[192]
    DIRECTION OUTPUT ;
    USE SIGNAL ;
    PORT
      LAYER M4 ;
        RECT 0.000 806.880 0.192 806.904 ;
    END
  END t_out[192]
  PIN t_out[193]
    DIRECTION OUTPUT ;
    USE SIGNAL ;
    PORT
      LAYER M4 ;
        RECT 0.000 807.072 0.192 807.096 ;
    END
  END t_out[193]
  PIN t_out[194]
    DIRECTION OUTPUT ;
    USE SIGNAL ;
    PORT
      LAYER M4 ;
        RECT 0.000 807.264 0.192 807.288 ;
    END
  END t_out[194]
  PIN t_out[195]
    DIRECTION OUTPUT ;
    USE SIGNAL ;
    PORT
      LAYER M4 ;
        RECT 0.000 807.456 0.192 807.480 ;
    END
  END t_out[195]
  PIN t_out[196]
    DIRECTION OUTPUT ;
    USE SIGNAL ;
    PORT
      LAYER M4 ;
        RECT 0.000 807.648 0.192 807.672 ;
    END
  END t_out[196]
  PIN t_out[197]
    DIRECTION OUTPUT ;
    USE SIGNAL ;
    PORT
      LAYER M4 ;
        RECT 0.000 807.840 0.192 807.864 ;
    END
  END t_out[197]
  PIN t_out[198]
    DIRECTION OUTPUT ;
    USE SIGNAL ;
    PORT
      LAYER M4 ;
        RECT 0.000 808.032 0.192 808.056 ;
    END
  END t_out[198]
  PIN t_out[199]
    DIRECTION OUTPUT ;
    USE SIGNAL ;
    PORT
      LAYER M4 ;
        RECT 0.000 808.224 0.192 808.248 ;
    END
  END t_out[199]
  PIN t_out[200]
    DIRECTION OUTPUT ;
    USE SIGNAL ;
    PORT
      LAYER M4 ;
        RECT 0.000 808.416 0.192 808.440 ;
    END
  END t_out[200]
  PIN t_out[201]
    DIRECTION OUTPUT ;
    USE SIGNAL ;
    PORT
      LAYER M4 ;
        RECT 0.000 808.608 0.192 808.632 ;
    END
  END t_out[201]
  PIN t_out[202]
    DIRECTION OUTPUT ;
    USE SIGNAL ;
    PORT
      LAYER M4 ;
        RECT 0.000 808.800 0.192 808.824 ;
    END
  END t_out[202]
  PIN t_out[203]
    DIRECTION OUTPUT ;
    USE SIGNAL ;
    PORT
      LAYER M4 ;
        RECT 0.000 808.992 0.192 809.016 ;
    END
  END t_out[203]
  PIN t_out[204]
    DIRECTION OUTPUT ;
    USE SIGNAL ;
    PORT
      LAYER M4 ;
        RECT 0.000 809.184 0.192 809.208 ;
    END
  END t_out[204]
  PIN t_out[205]
    DIRECTION OUTPUT ;
    USE SIGNAL ;
    PORT
      LAYER M4 ;
        RECT 0.000 809.376 0.192 809.400 ;
    END
  END t_out[205]
  PIN t_out[206]
    DIRECTION OUTPUT ;
    USE SIGNAL ;
    PORT
      LAYER M4 ;
        RECT 0.000 809.568 0.192 809.592 ;
    END
  END t_out[206]
  PIN t_out[207]
    DIRECTION OUTPUT ;
    USE SIGNAL ;
    PORT
      LAYER M4 ;
        RECT 0.000 809.760 0.192 809.784 ;
    END
  END t_out[207]
  PIN t_out[208]
    DIRECTION OUTPUT ;
    USE SIGNAL ;
    PORT
      LAYER M4 ;
        RECT 0.000 809.952 0.192 809.976 ;
    END
  END t_out[208]
  PIN t_out[209]
    DIRECTION OUTPUT ;
    USE SIGNAL ;
    PORT
      LAYER M4 ;
        RECT 0.000 810.144 0.192 810.168 ;
    END
  END t_out[209]
  PIN t_out[210]
    DIRECTION OUTPUT ;
    USE SIGNAL ;
    PORT
      LAYER M4 ;
        RECT 0.000 810.336 0.192 810.360 ;
    END
  END t_out[210]
  PIN t_out[211]
    DIRECTION OUTPUT ;
    USE SIGNAL ;
    PORT
      LAYER M4 ;
        RECT 0.000 810.528 0.192 810.552 ;
    END
  END t_out[211]
  PIN t_out[212]
    DIRECTION OUTPUT ;
    USE SIGNAL ;
    PORT
      LAYER M4 ;
        RECT 0.000 810.720 0.192 810.744 ;
    END
  END t_out[212]
  PIN t_out[213]
    DIRECTION OUTPUT ;
    USE SIGNAL ;
    PORT
      LAYER M4 ;
        RECT 0.000 810.912 0.192 810.936 ;
    END
  END t_out[213]
  PIN t_out[214]
    DIRECTION OUTPUT ;
    USE SIGNAL ;
    PORT
      LAYER M4 ;
        RECT 0.000 811.104 0.192 811.128 ;
    END
  END t_out[214]
  PIN t_out[215]
    DIRECTION OUTPUT ;
    USE SIGNAL ;
    PORT
      LAYER M4 ;
        RECT 0.000 811.296 0.192 811.320 ;
    END
  END t_out[215]
  PIN t_out[216]
    DIRECTION OUTPUT ;
    USE SIGNAL ;
    PORT
      LAYER M4 ;
        RECT 0.000 811.488 0.192 811.512 ;
    END
  END t_out[216]
  PIN t_out[217]
    DIRECTION OUTPUT ;
    USE SIGNAL ;
    PORT
      LAYER M4 ;
        RECT 0.000 811.680 0.192 811.704 ;
    END
  END t_out[217]
  PIN t_out[218]
    DIRECTION OUTPUT ;
    USE SIGNAL ;
    PORT
      LAYER M4 ;
        RECT 0.000 811.872 0.192 811.896 ;
    END
  END t_out[218]
  PIN t_out[219]
    DIRECTION OUTPUT ;
    USE SIGNAL ;
    PORT
      LAYER M4 ;
        RECT 0.000 812.064 0.192 812.088 ;
    END
  END t_out[219]
  PIN t_out[220]
    DIRECTION OUTPUT ;
    USE SIGNAL ;
    PORT
      LAYER M4 ;
        RECT 0.000 812.256 0.192 812.280 ;
    END
  END t_out[220]
  PIN t_out[221]
    DIRECTION OUTPUT ;
    USE SIGNAL ;
    PORT
      LAYER M4 ;
        RECT 0.000 812.448 0.192 812.472 ;
    END
  END t_out[221]
  PIN t_out[222]
    DIRECTION OUTPUT ;
    USE SIGNAL ;
    PORT
      LAYER M4 ;
        RECT 0.000 812.640 0.192 812.664 ;
    END
  END t_out[222]
  PIN t_out[223]
    DIRECTION OUTPUT ;
    USE SIGNAL ;
    PORT
      LAYER M4 ;
        RECT 0.000 812.832 0.192 812.856 ;
    END
  END t_out[223]
  PIN t_out[224]
    DIRECTION OUTPUT ;
    USE SIGNAL ;
    PORT
      LAYER M4 ;
        RECT 0.000 813.024 0.192 813.048 ;
    END
  END t_out[224]
  PIN t_out[225]
    DIRECTION OUTPUT ;
    USE SIGNAL ;
    PORT
      LAYER M4 ;
        RECT 0.000 813.216 0.192 813.240 ;
    END
  END t_out[225]
  PIN t_out[226]
    DIRECTION OUTPUT ;
    USE SIGNAL ;
    PORT
      LAYER M4 ;
        RECT 0.000 813.408 0.192 813.432 ;
    END
  END t_out[226]
  PIN t_out[227]
    DIRECTION OUTPUT ;
    USE SIGNAL ;
    PORT
      LAYER M4 ;
        RECT 0.000 813.600 0.192 813.624 ;
    END
  END t_out[227]
  PIN t_out[228]
    DIRECTION OUTPUT ;
    USE SIGNAL ;
    PORT
      LAYER M4 ;
        RECT 0.000 813.792 0.192 813.816 ;
    END
  END t_out[228]
  PIN t_out[229]
    DIRECTION OUTPUT ;
    USE SIGNAL ;
    PORT
      LAYER M4 ;
        RECT 0.000 813.984 0.192 814.008 ;
    END
  END t_out[229]
  PIN t_out[230]
    DIRECTION OUTPUT ;
    USE SIGNAL ;
    PORT
      LAYER M4 ;
        RECT 0.000 814.176 0.192 814.200 ;
    END
  END t_out[230]
  PIN t_out[231]
    DIRECTION OUTPUT ;
    USE SIGNAL ;
    PORT
      LAYER M4 ;
        RECT 0.000 814.368 0.192 814.392 ;
    END
  END t_out[231]
  PIN t_out[232]
    DIRECTION OUTPUT ;
    USE SIGNAL ;
    PORT
      LAYER M4 ;
        RECT 0.000 814.560 0.192 814.584 ;
    END
  END t_out[232]
  PIN t_out[233]
    DIRECTION OUTPUT ;
    USE SIGNAL ;
    PORT
      LAYER M4 ;
        RECT 0.000 814.752 0.192 814.776 ;
    END
  END t_out[233]
  PIN t_out[234]
    DIRECTION OUTPUT ;
    USE SIGNAL ;
    PORT
      LAYER M4 ;
        RECT 0.000 814.944 0.192 814.968 ;
    END
  END t_out[234]
  PIN t_out[235]
    DIRECTION OUTPUT ;
    USE SIGNAL ;
    PORT
      LAYER M4 ;
        RECT 0.000 815.136 0.192 815.160 ;
    END
  END t_out[235]
  PIN t_out[236]
    DIRECTION OUTPUT ;
    USE SIGNAL ;
    PORT
      LAYER M4 ;
        RECT 0.000 815.328 0.192 815.352 ;
    END
  END t_out[236]
  PIN t_out[237]
    DIRECTION OUTPUT ;
    USE SIGNAL ;
    PORT
      LAYER M4 ;
        RECT 0.000 815.520 0.192 815.544 ;
    END
  END t_out[237]
  PIN t_out[238]
    DIRECTION OUTPUT ;
    USE SIGNAL ;
    PORT
      LAYER M4 ;
        RECT 0.000 815.712 0.192 815.736 ;
    END
  END t_out[238]
  PIN t_out[239]
    DIRECTION OUTPUT ;
    USE SIGNAL ;
    PORT
      LAYER M4 ;
        RECT 0.000 815.904 0.192 815.928 ;
    END
  END t_out[239]
  PIN t_out[240]
    DIRECTION OUTPUT ;
    USE SIGNAL ;
    PORT
      LAYER M4 ;
        RECT 0.000 816.096 0.192 816.120 ;
    END
  END t_out[240]
  PIN t_out[241]
    DIRECTION OUTPUT ;
    USE SIGNAL ;
    PORT
      LAYER M4 ;
        RECT 0.000 816.288 0.192 816.312 ;
    END
  END t_out[241]
  PIN t_out[242]
    DIRECTION OUTPUT ;
    USE SIGNAL ;
    PORT
      LAYER M4 ;
        RECT 0.000 816.480 0.192 816.504 ;
    END
  END t_out[242]
  PIN t_out[243]
    DIRECTION OUTPUT ;
    USE SIGNAL ;
    PORT
      LAYER M4 ;
        RECT 0.000 816.672 0.192 816.696 ;
    END
  END t_out[243]
  PIN t_out[244]
    DIRECTION OUTPUT ;
    USE SIGNAL ;
    PORT
      LAYER M4 ;
        RECT 0.000 816.864 0.192 816.888 ;
    END
  END t_out[244]
  PIN t_out[245]
    DIRECTION OUTPUT ;
    USE SIGNAL ;
    PORT
      LAYER M4 ;
        RECT 0.000 817.056 0.192 817.080 ;
    END
  END t_out[245]
  PIN t_out[246]
    DIRECTION OUTPUT ;
    USE SIGNAL ;
    PORT
      LAYER M4 ;
        RECT 0.000 817.248 0.192 817.272 ;
    END
  END t_out[246]
  PIN t_out[247]
    DIRECTION OUTPUT ;
    USE SIGNAL ;
    PORT
      LAYER M4 ;
        RECT 0.000 817.440 0.192 817.464 ;
    END
  END t_out[247]
  PIN t_out[248]
    DIRECTION OUTPUT ;
    USE SIGNAL ;
    PORT
      LAYER M4 ;
        RECT 0.000 817.632 0.192 817.656 ;
    END
  END t_out[248]
  PIN t_out[249]
    DIRECTION OUTPUT ;
    USE SIGNAL ;
    PORT
      LAYER M4 ;
        RECT 0.000 817.824 0.192 817.848 ;
    END
  END t_out[249]
  PIN t_out[250]
    DIRECTION OUTPUT ;
    USE SIGNAL ;
    PORT
      LAYER M4 ;
        RECT 0.000 818.016 0.192 818.040 ;
    END
  END t_out[250]
  PIN t_out[251]
    DIRECTION OUTPUT ;
    USE SIGNAL ;
    PORT
      LAYER M4 ;
        RECT 0.000 818.208 0.192 818.232 ;
    END
  END t_out[251]
  PIN t_out[252]
    DIRECTION OUTPUT ;
    USE SIGNAL ;
    PORT
      LAYER M4 ;
        RECT 0.000 818.400 0.192 818.424 ;
    END
  END t_out[252]
  PIN t_out[253]
    DIRECTION OUTPUT ;
    USE SIGNAL ;
    PORT
      LAYER M4 ;
        RECT 0.000 818.592 0.192 818.616 ;
    END
  END t_out[253]
  PIN t_out[254]
    DIRECTION OUTPUT ;
    USE SIGNAL ;
    PORT
      LAYER M4 ;
        RECT 0.000 818.784 0.192 818.808 ;
    END
  END t_out[254]
  PIN t_out[255]
    DIRECTION OUTPUT ;
    USE SIGNAL ;
    PORT
      LAYER M4 ;
        RECT 0.000 818.976 0.192 819.000 ;
    END
  END t_out[255]
  PIN t_out[256]
    DIRECTION OUTPUT ;
    USE SIGNAL ;
    PORT
      LAYER M4 ;
        RECT 0.000 819.168 0.192 819.192 ;
    END
  END t_out[256]
  PIN t_out[257]
    DIRECTION OUTPUT ;
    USE SIGNAL ;
    PORT
      LAYER M4 ;
        RECT 0.000 819.360 0.192 819.384 ;
    END
  END t_out[257]
  PIN t_out[258]
    DIRECTION OUTPUT ;
    USE SIGNAL ;
    PORT
      LAYER M4 ;
        RECT 0.000 819.552 0.192 819.576 ;
    END
  END t_out[258]
  PIN t_out[259]
    DIRECTION OUTPUT ;
    USE SIGNAL ;
    PORT
      LAYER M4 ;
        RECT 0.000 819.744 0.192 819.768 ;
    END
  END t_out[259]
  PIN t_out[260]
    DIRECTION OUTPUT ;
    USE SIGNAL ;
    PORT
      LAYER M4 ;
        RECT 0.000 819.936 0.192 819.960 ;
    END
  END t_out[260]
  PIN t_out[261]
    DIRECTION OUTPUT ;
    USE SIGNAL ;
    PORT
      LAYER M4 ;
        RECT 0.000 820.128 0.192 820.152 ;
    END
  END t_out[261]
  PIN t_out[262]
    DIRECTION OUTPUT ;
    USE SIGNAL ;
    PORT
      LAYER M4 ;
        RECT 0.000 820.320 0.192 820.344 ;
    END
  END t_out[262]
  PIN t_out[263]
    DIRECTION OUTPUT ;
    USE SIGNAL ;
    PORT
      LAYER M4 ;
        RECT 0.000 820.512 0.192 820.536 ;
    END
  END t_out[263]
  PIN t_out[264]
    DIRECTION OUTPUT ;
    USE SIGNAL ;
    PORT
      LAYER M4 ;
        RECT 0.000 820.704 0.192 820.728 ;
    END
  END t_out[264]
  PIN t_out[265]
    DIRECTION OUTPUT ;
    USE SIGNAL ;
    PORT
      LAYER M4 ;
        RECT 0.000 820.896 0.192 820.920 ;
    END
  END t_out[265]
  PIN t_out[266]
    DIRECTION OUTPUT ;
    USE SIGNAL ;
    PORT
      LAYER M4 ;
        RECT 0.000 821.088 0.192 821.112 ;
    END
  END t_out[266]
  PIN t_out[267]
    DIRECTION OUTPUT ;
    USE SIGNAL ;
    PORT
      LAYER M4 ;
        RECT 0.000 821.280 0.192 821.304 ;
    END
  END t_out[267]
  PIN t_out[268]
    DIRECTION OUTPUT ;
    USE SIGNAL ;
    PORT
      LAYER M4 ;
        RECT 0.000 821.472 0.192 821.496 ;
    END
  END t_out[268]
  PIN t_out[269]
    DIRECTION OUTPUT ;
    USE SIGNAL ;
    PORT
      LAYER M4 ;
        RECT 0.000 821.664 0.192 821.688 ;
    END
  END t_out[269]
  PIN t_out[270]
    DIRECTION OUTPUT ;
    USE SIGNAL ;
    PORT
      LAYER M4 ;
        RECT 0.000 821.856 0.192 821.880 ;
    END
  END t_out[270]
  PIN t_out[271]
    DIRECTION OUTPUT ;
    USE SIGNAL ;
    PORT
      LAYER M4 ;
        RECT 0.000 822.048 0.192 822.072 ;
    END
  END t_out[271]
  PIN t_out[272]
    DIRECTION OUTPUT ;
    USE SIGNAL ;
    PORT
      LAYER M4 ;
        RECT 0.000 822.240 0.192 822.264 ;
    END
  END t_out[272]
  PIN t_out[273]
    DIRECTION OUTPUT ;
    USE SIGNAL ;
    PORT
      LAYER M4 ;
        RECT 0.000 822.432 0.192 822.456 ;
    END
  END t_out[273]
  PIN t_out[274]
    DIRECTION OUTPUT ;
    USE SIGNAL ;
    PORT
      LAYER M4 ;
        RECT 0.000 822.624 0.192 822.648 ;
    END
  END t_out[274]
  PIN t_out[275]
    DIRECTION OUTPUT ;
    USE SIGNAL ;
    PORT
      LAYER M4 ;
        RECT 0.000 822.816 0.192 822.840 ;
    END
  END t_out[275]
  PIN t_out[276]
    DIRECTION OUTPUT ;
    USE SIGNAL ;
    PORT
      LAYER M4 ;
        RECT 0.000 823.008 0.192 823.032 ;
    END
  END t_out[276]
  PIN t_out[277]
    DIRECTION OUTPUT ;
    USE SIGNAL ;
    PORT
      LAYER M4 ;
        RECT 0.000 823.200 0.192 823.224 ;
    END
  END t_out[277]
  PIN t_out[278]
    DIRECTION OUTPUT ;
    USE SIGNAL ;
    PORT
      LAYER M4 ;
        RECT 0.000 823.392 0.192 823.416 ;
    END
  END t_out[278]
  PIN t_out[279]
    DIRECTION OUTPUT ;
    USE SIGNAL ;
    PORT
      LAYER M4 ;
        RECT 0.000 823.584 0.192 823.608 ;
    END
  END t_out[279]
  PIN t_out[280]
    DIRECTION OUTPUT ;
    USE SIGNAL ;
    PORT
      LAYER M4 ;
        RECT 0.000 823.776 0.192 823.800 ;
    END
  END t_out[280]
  PIN t_out[281]
    DIRECTION OUTPUT ;
    USE SIGNAL ;
    PORT
      LAYER M4 ;
        RECT 0.000 823.968 0.192 823.992 ;
    END
  END t_out[281]
  PIN t_out[282]
    DIRECTION OUTPUT ;
    USE SIGNAL ;
    PORT
      LAYER M4 ;
        RECT 0.000 824.160 0.192 824.184 ;
    END
  END t_out[282]
  PIN t_out[283]
    DIRECTION OUTPUT ;
    USE SIGNAL ;
    PORT
      LAYER M4 ;
        RECT 0.000 824.352 0.192 824.376 ;
    END
  END t_out[283]
  PIN t_out[284]
    DIRECTION OUTPUT ;
    USE SIGNAL ;
    PORT
      LAYER M4 ;
        RECT 0.000 824.544 0.192 824.568 ;
    END
  END t_out[284]
  PIN t_out[285]
    DIRECTION OUTPUT ;
    USE SIGNAL ;
    PORT
      LAYER M4 ;
        RECT 0.000 824.736 0.192 824.760 ;
    END
  END t_out[285]
  PIN t_out[286]
    DIRECTION OUTPUT ;
    USE SIGNAL ;
    PORT
      LAYER M4 ;
        RECT 0.000 824.928 0.192 824.952 ;
    END
  END t_out[286]
  PIN t_out[287]
    DIRECTION OUTPUT ;
    USE SIGNAL ;
    PORT
      LAYER M4 ;
        RECT 0.000 825.120 0.192 825.144 ;
    END
  END t_out[287]
  PIN t_out[288]
    DIRECTION OUTPUT ;
    USE SIGNAL ;
    PORT
      LAYER M4 ;
        RECT 0.000 825.312 0.192 825.336 ;
    END
  END t_out[288]
  PIN t_out[289]
    DIRECTION OUTPUT ;
    USE SIGNAL ;
    PORT
      LAYER M4 ;
        RECT 0.000 825.504 0.192 825.528 ;
    END
  END t_out[289]
  PIN t_out[290]
    DIRECTION OUTPUT ;
    USE SIGNAL ;
    PORT
      LAYER M4 ;
        RECT 0.000 825.696 0.192 825.720 ;
    END
  END t_out[290]
  PIN t_out[291]
    DIRECTION OUTPUT ;
    USE SIGNAL ;
    PORT
      LAYER M4 ;
        RECT 0.000 825.888 0.192 825.912 ;
    END
  END t_out[291]
  PIN t_out[292]
    DIRECTION OUTPUT ;
    USE SIGNAL ;
    PORT
      LAYER M4 ;
        RECT 0.000 826.080 0.192 826.104 ;
    END
  END t_out[292]
  PIN t_out[293]
    DIRECTION OUTPUT ;
    USE SIGNAL ;
    PORT
      LAYER M4 ;
        RECT 0.000 826.272 0.192 826.296 ;
    END
  END t_out[293]
  PIN t_out[294]
    DIRECTION OUTPUT ;
    USE SIGNAL ;
    PORT
      LAYER M4 ;
        RECT 0.000 826.464 0.192 826.488 ;
    END
  END t_out[294]
  PIN t_out[295]
    DIRECTION OUTPUT ;
    USE SIGNAL ;
    PORT
      LAYER M4 ;
        RECT 0.000 826.656 0.192 826.680 ;
    END
  END t_out[295]
  PIN t_out[296]
    DIRECTION OUTPUT ;
    USE SIGNAL ;
    PORT
      LAYER M4 ;
        RECT 0.000 826.848 0.192 826.872 ;
    END
  END t_out[296]
  PIN t_out[297]
    DIRECTION OUTPUT ;
    USE SIGNAL ;
    PORT
      LAYER M4 ;
        RECT 0.000 827.040 0.192 827.064 ;
    END
  END t_out[297]
  PIN t_out[298]
    DIRECTION OUTPUT ;
    USE SIGNAL ;
    PORT
      LAYER M4 ;
        RECT 0.000 827.232 0.192 827.256 ;
    END
  END t_out[298]
  PIN t_out[299]
    DIRECTION OUTPUT ;
    USE SIGNAL ;
    PORT
      LAYER M4 ;
        RECT 0.000 827.424 0.192 827.448 ;
    END
  END t_out[299]
  PIN t_out[300]
    DIRECTION OUTPUT ;
    USE SIGNAL ;
    PORT
      LAYER M4 ;
        RECT 0.000 827.616 0.192 827.640 ;
    END
  END t_out[300]
  PIN t_out[301]
    DIRECTION OUTPUT ;
    USE SIGNAL ;
    PORT
      LAYER M4 ;
        RECT 0.000 827.808 0.192 827.832 ;
    END
  END t_out[301]
  PIN t_out[302]
    DIRECTION OUTPUT ;
    USE SIGNAL ;
    PORT
      LAYER M4 ;
        RECT 0.000 828.000 0.192 828.024 ;
    END
  END t_out[302]
  PIN t_out[303]
    DIRECTION OUTPUT ;
    USE SIGNAL ;
    PORT
      LAYER M4 ;
        RECT 0.000 828.192 0.192 828.216 ;
    END
  END t_out[303]
  PIN t_out[304]
    DIRECTION OUTPUT ;
    USE SIGNAL ;
    PORT
      LAYER M4 ;
        RECT 0.000 828.384 0.192 828.408 ;
    END
  END t_out[304]
  PIN t_out[305]
    DIRECTION OUTPUT ;
    USE SIGNAL ;
    PORT
      LAYER M4 ;
        RECT 0.000 828.576 0.192 828.600 ;
    END
  END t_out[305]
  PIN t_out[306]
    DIRECTION OUTPUT ;
    USE SIGNAL ;
    PORT
      LAYER M4 ;
        RECT 0.000 828.768 0.192 828.792 ;
    END
  END t_out[306]
  PIN t_out[307]
    DIRECTION OUTPUT ;
    USE SIGNAL ;
    PORT
      LAYER M4 ;
        RECT 0.000 828.960 0.192 828.984 ;
    END
  END t_out[307]
  PIN t_out[308]
    DIRECTION OUTPUT ;
    USE SIGNAL ;
    PORT
      LAYER M4 ;
        RECT 0.000 829.152 0.192 829.176 ;
    END
  END t_out[308]
  PIN t_out[309]
    DIRECTION OUTPUT ;
    USE SIGNAL ;
    PORT
      LAYER M4 ;
        RECT 0.000 829.344 0.192 829.368 ;
    END
  END t_out[309]
  PIN t_out[310]
    DIRECTION OUTPUT ;
    USE SIGNAL ;
    PORT
      LAYER M4 ;
        RECT 0.000 829.536 0.192 829.560 ;
    END
  END t_out[310]
  PIN t_out[311]
    DIRECTION OUTPUT ;
    USE SIGNAL ;
    PORT
      LAYER M4 ;
        RECT 0.000 829.728 0.192 829.752 ;
    END
  END t_out[311]
  PIN t_out[312]
    DIRECTION OUTPUT ;
    USE SIGNAL ;
    PORT
      LAYER M4 ;
        RECT 0.000 829.920 0.192 829.944 ;
    END
  END t_out[312]
  PIN t_out[313]
    DIRECTION OUTPUT ;
    USE SIGNAL ;
    PORT
      LAYER M4 ;
        RECT 0.000 830.112 0.192 830.136 ;
    END
  END t_out[313]
  PIN t_out[314]
    DIRECTION OUTPUT ;
    USE SIGNAL ;
    PORT
      LAYER M4 ;
        RECT 0.000 830.304 0.192 830.328 ;
    END
  END t_out[314]
  PIN t_out[315]
    DIRECTION OUTPUT ;
    USE SIGNAL ;
    PORT
      LAYER M4 ;
        RECT 0.000 830.496 0.192 830.520 ;
    END
  END t_out[315]
  PIN t_out[316]
    DIRECTION OUTPUT ;
    USE SIGNAL ;
    PORT
      LAYER M4 ;
        RECT 0.000 830.688 0.192 830.712 ;
    END
  END t_out[316]
  PIN t_out[317]
    DIRECTION OUTPUT ;
    USE SIGNAL ;
    PORT
      LAYER M4 ;
        RECT 0.000 830.880 0.192 830.904 ;
    END
  END t_out[317]
  PIN t_out[318]
    DIRECTION OUTPUT ;
    USE SIGNAL ;
    PORT
      LAYER M4 ;
        RECT 0.000 831.072 0.192 831.096 ;
    END
  END t_out[318]
  PIN t_out[319]
    DIRECTION OUTPUT ;
    USE SIGNAL ;
    PORT
      LAYER M4 ;
        RECT 0.000 831.264 0.192 831.288 ;
    END
  END t_out[319]
  PIN t_out[320]
    DIRECTION OUTPUT ;
    USE SIGNAL ;
    PORT
      LAYER M4 ;
        RECT 0.000 831.456 0.192 831.480 ;
    END
  END t_out[320]
  PIN t_out[321]
    DIRECTION OUTPUT ;
    USE SIGNAL ;
    PORT
      LAYER M4 ;
        RECT 0.000 831.648 0.192 831.672 ;
    END
  END t_out[321]
  PIN t_out[322]
    DIRECTION OUTPUT ;
    USE SIGNAL ;
    PORT
      LAYER M4 ;
        RECT 0.000 831.840 0.192 831.864 ;
    END
  END t_out[322]
  PIN t_out[323]
    DIRECTION OUTPUT ;
    USE SIGNAL ;
    PORT
      LAYER M4 ;
        RECT 0.000 832.032 0.192 832.056 ;
    END
  END t_out[323]
  PIN t_out[324]
    DIRECTION OUTPUT ;
    USE SIGNAL ;
    PORT
      LAYER M4 ;
        RECT 0.000 832.224 0.192 832.248 ;
    END
  END t_out[324]
  PIN t_out[325]
    DIRECTION OUTPUT ;
    USE SIGNAL ;
    PORT
      LAYER M4 ;
        RECT 0.000 832.416 0.192 832.440 ;
    END
  END t_out[325]
  PIN t_out[326]
    DIRECTION OUTPUT ;
    USE SIGNAL ;
    PORT
      LAYER M4 ;
        RECT 0.000 832.608 0.192 832.632 ;
    END
  END t_out[326]
  PIN t_out[327]
    DIRECTION OUTPUT ;
    USE SIGNAL ;
    PORT
      LAYER M4 ;
        RECT 0.000 832.800 0.192 832.824 ;
    END
  END t_out[327]
  PIN t_out[328]
    DIRECTION OUTPUT ;
    USE SIGNAL ;
    PORT
      LAYER M4 ;
        RECT 0.000 832.992 0.192 833.016 ;
    END
  END t_out[328]
  PIN t_out[329]
    DIRECTION OUTPUT ;
    USE SIGNAL ;
    PORT
      LAYER M4 ;
        RECT 0.000 833.184 0.192 833.208 ;
    END
  END t_out[329]
  PIN t_out[330]
    DIRECTION OUTPUT ;
    USE SIGNAL ;
    PORT
      LAYER M4 ;
        RECT 0.000 833.376 0.192 833.400 ;
    END
  END t_out[330]
  PIN t_out[331]
    DIRECTION OUTPUT ;
    USE SIGNAL ;
    PORT
      LAYER M4 ;
        RECT 0.000 833.568 0.192 833.592 ;
    END
  END t_out[331]
  PIN t_out[332]
    DIRECTION OUTPUT ;
    USE SIGNAL ;
    PORT
      LAYER M4 ;
        RECT 0.000 833.760 0.192 833.784 ;
    END
  END t_out[332]
  PIN t_out[333]
    DIRECTION OUTPUT ;
    USE SIGNAL ;
    PORT
      LAYER M4 ;
        RECT 0.000 833.952 0.192 833.976 ;
    END
  END t_out[333]
  PIN t_out[334]
    DIRECTION OUTPUT ;
    USE SIGNAL ;
    PORT
      LAYER M4 ;
        RECT 0.000 834.144 0.192 834.168 ;
    END
  END t_out[334]
  PIN t_out[335]
    DIRECTION OUTPUT ;
    USE SIGNAL ;
    PORT
      LAYER M4 ;
        RECT 0.000 834.336 0.192 834.360 ;
    END
  END t_out[335]
  PIN t_out[336]
    DIRECTION OUTPUT ;
    USE SIGNAL ;
    PORT
      LAYER M4 ;
        RECT 0.000 834.528 0.192 834.552 ;
    END
  END t_out[336]
  PIN t_out[337]
    DIRECTION OUTPUT ;
    USE SIGNAL ;
    PORT
      LAYER M4 ;
        RECT 0.000 834.720 0.192 834.744 ;
    END
  END t_out[337]
  PIN t_out[338]
    DIRECTION OUTPUT ;
    USE SIGNAL ;
    PORT
      LAYER M4 ;
        RECT 0.000 834.912 0.192 834.936 ;
    END
  END t_out[338]
  PIN t_out[339]
    DIRECTION OUTPUT ;
    USE SIGNAL ;
    PORT
      LAYER M4 ;
        RECT 0.000 835.104 0.192 835.128 ;
    END
  END t_out[339]
  PIN t_out[340]
    DIRECTION OUTPUT ;
    USE SIGNAL ;
    PORT
      LAYER M4 ;
        RECT 0.000 835.296 0.192 835.320 ;
    END
  END t_out[340]
  PIN t_out[341]
    DIRECTION OUTPUT ;
    USE SIGNAL ;
    PORT
      LAYER M4 ;
        RECT 0.000 835.488 0.192 835.512 ;
    END
  END t_out[341]
  PIN t_out[342]
    DIRECTION OUTPUT ;
    USE SIGNAL ;
    PORT
      LAYER M4 ;
        RECT 0.000 835.680 0.192 835.704 ;
    END
  END t_out[342]
  PIN t_out[343]
    DIRECTION OUTPUT ;
    USE SIGNAL ;
    PORT
      LAYER M4 ;
        RECT 0.000 835.872 0.192 835.896 ;
    END
  END t_out[343]
  PIN t_out[344]
    DIRECTION OUTPUT ;
    USE SIGNAL ;
    PORT
      LAYER M4 ;
        RECT 0.000 836.064 0.192 836.088 ;
    END
  END t_out[344]
  PIN t_out[345]
    DIRECTION OUTPUT ;
    USE SIGNAL ;
    PORT
      LAYER M4 ;
        RECT 0.000 836.256 0.192 836.280 ;
    END
  END t_out[345]
  PIN t_out[346]
    DIRECTION OUTPUT ;
    USE SIGNAL ;
    PORT
      LAYER M4 ;
        RECT 0.000 836.448 0.192 836.472 ;
    END
  END t_out[346]
  PIN t_out[347]
    DIRECTION OUTPUT ;
    USE SIGNAL ;
    PORT
      LAYER M4 ;
        RECT 0.000 836.640 0.192 836.664 ;
    END
  END t_out[347]
  PIN t_out[348]
    DIRECTION OUTPUT ;
    USE SIGNAL ;
    PORT
      LAYER M4 ;
        RECT 0.000 836.832 0.192 836.856 ;
    END
  END t_out[348]
  PIN t_out[349]
    DIRECTION OUTPUT ;
    USE SIGNAL ;
    PORT
      LAYER M4 ;
        RECT 0.000 837.024 0.192 837.048 ;
    END
  END t_out[349]
  PIN t_out[350]
    DIRECTION OUTPUT ;
    USE SIGNAL ;
    PORT
      LAYER M4 ;
        RECT 0.000 837.216 0.192 837.240 ;
    END
  END t_out[350]
  PIN t_out[351]
    DIRECTION OUTPUT ;
    USE SIGNAL ;
    PORT
      LAYER M4 ;
        RECT 0.000 837.408 0.192 837.432 ;
    END
  END t_out[351]
  PIN t_out[352]
    DIRECTION OUTPUT ;
    USE SIGNAL ;
    PORT
      LAYER M4 ;
        RECT 0.000 837.600 0.192 837.624 ;
    END
  END t_out[352]
  PIN t_out[353]
    DIRECTION OUTPUT ;
    USE SIGNAL ;
    PORT
      LAYER M4 ;
        RECT 0.000 837.792 0.192 837.816 ;
    END
  END t_out[353]
  PIN t_out[354]
    DIRECTION OUTPUT ;
    USE SIGNAL ;
    PORT
      LAYER M4 ;
        RECT 0.000 837.984 0.192 838.008 ;
    END
  END t_out[354]
  PIN t_out[355]
    DIRECTION OUTPUT ;
    USE SIGNAL ;
    PORT
      LAYER M4 ;
        RECT 0.000 838.176 0.192 838.200 ;
    END
  END t_out[355]
  PIN t_out[356]
    DIRECTION OUTPUT ;
    USE SIGNAL ;
    PORT
      LAYER M4 ;
        RECT 0.000 838.368 0.192 838.392 ;
    END
  END t_out[356]
  PIN t_out[357]
    DIRECTION OUTPUT ;
    USE SIGNAL ;
    PORT
      LAYER M4 ;
        RECT 0.000 838.560 0.192 838.584 ;
    END
  END t_out[357]
  PIN t_out[358]
    DIRECTION OUTPUT ;
    USE SIGNAL ;
    PORT
      LAYER M4 ;
        RECT 0.000 838.752 0.192 838.776 ;
    END
  END t_out[358]
  PIN t_out[359]
    DIRECTION OUTPUT ;
    USE SIGNAL ;
    PORT
      LAYER M4 ;
        RECT 0.000 838.944 0.192 838.968 ;
    END
  END t_out[359]
  PIN t_out[360]
    DIRECTION OUTPUT ;
    USE SIGNAL ;
    PORT
      LAYER M4 ;
        RECT 0.000 839.136 0.192 839.160 ;
    END
  END t_out[360]
  PIN t_out[361]
    DIRECTION OUTPUT ;
    USE SIGNAL ;
    PORT
      LAYER M4 ;
        RECT 0.000 839.328 0.192 839.352 ;
    END
  END t_out[361]
  PIN t_out[362]
    DIRECTION OUTPUT ;
    USE SIGNAL ;
    PORT
      LAYER M4 ;
        RECT 0.000 839.520 0.192 839.544 ;
    END
  END t_out[362]
  PIN t_out[363]
    DIRECTION OUTPUT ;
    USE SIGNAL ;
    PORT
      LAYER M4 ;
        RECT 0.000 839.712 0.192 839.736 ;
    END
  END t_out[363]
  PIN t_out[364]
    DIRECTION OUTPUT ;
    USE SIGNAL ;
    PORT
      LAYER M4 ;
        RECT 0.000 839.904 0.192 839.928 ;
    END
  END t_out[364]
  PIN t_out[365]
    DIRECTION OUTPUT ;
    USE SIGNAL ;
    PORT
      LAYER M4 ;
        RECT 0.000 840.096 0.192 840.120 ;
    END
  END t_out[365]
  PIN t_out[366]
    DIRECTION OUTPUT ;
    USE SIGNAL ;
    PORT
      LAYER M4 ;
        RECT 0.000 840.288 0.192 840.312 ;
    END
  END t_out[366]
  PIN t_out[367]
    DIRECTION OUTPUT ;
    USE SIGNAL ;
    PORT
      LAYER M4 ;
        RECT 0.000 840.480 0.192 840.504 ;
    END
  END t_out[367]
  PIN t_out[368]
    DIRECTION OUTPUT ;
    USE SIGNAL ;
    PORT
      LAYER M4 ;
        RECT 0.000 840.672 0.192 840.696 ;
    END
  END t_out[368]
  PIN t_out[369]
    DIRECTION OUTPUT ;
    USE SIGNAL ;
    PORT
      LAYER M4 ;
        RECT 0.000 840.864 0.192 840.888 ;
    END
  END t_out[369]
  PIN t_out[370]
    DIRECTION OUTPUT ;
    USE SIGNAL ;
    PORT
      LAYER M4 ;
        RECT 0.000 841.056 0.192 841.080 ;
    END
  END t_out[370]
  PIN t_out[371]
    DIRECTION OUTPUT ;
    USE SIGNAL ;
    PORT
      LAYER M4 ;
        RECT 0.000 841.248 0.192 841.272 ;
    END
  END t_out[371]
  PIN t_out[372]
    DIRECTION OUTPUT ;
    USE SIGNAL ;
    PORT
      LAYER M4 ;
        RECT 0.000 841.440 0.192 841.464 ;
    END
  END t_out[372]
  PIN t_out[373]
    DIRECTION OUTPUT ;
    USE SIGNAL ;
    PORT
      LAYER M4 ;
        RECT 0.000 841.632 0.192 841.656 ;
    END
  END t_out[373]
  PIN t_out[374]
    DIRECTION OUTPUT ;
    USE SIGNAL ;
    PORT
      LAYER M4 ;
        RECT 0.000 841.824 0.192 841.848 ;
    END
  END t_out[374]
  PIN t_out[375]
    DIRECTION OUTPUT ;
    USE SIGNAL ;
    PORT
      LAYER M4 ;
        RECT 0.000 842.016 0.192 842.040 ;
    END
  END t_out[375]
  PIN t_out[376]
    DIRECTION OUTPUT ;
    USE SIGNAL ;
    PORT
      LAYER M4 ;
        RECT 0.000 842.208 0.192 842.232 ;
    END
  END t_out[376]
  PIN t_out[377]
    DIRECTION OUTPUT ;
    USE SIGNAL ;
    PORT
      LAYER M4 ;
        RECT 0.000 842.400 0.192 842.424 ;
    END
  END t_out[377]
  PIN t_out[378]
    DIRECTION OUTPUT ;
    USE SIGNAL ;
    PORT
      LAYER M4 ;
        RECT 0.000 842.592 0.192 842.616 ;
    END
  END t_out[378]
  PIN t_out[379]
    DIRECTION OUTPUT ;
    USE SIGNAL ;
    PORT
      LAYER M4 ;
        RECT 0.000 842.784 0.192 842.808 ;
    END
  END t_out[379]
  PIN t_out[380]
    DIRECTION OUTPUT ;
    USE SIGNAL ;
    PORT
      LAYER M4 ;
        RECT 0.000 842.976 0.192 843.000 ;
    END
  END t_out[380]
  PIN t_out[381]
    DIRECTION OUTPUT ;
    USE SIGNAL ;
    PORT
      LAYER M4 ;
        RECT 0.000 843.168 0.192 843.192 ;
    END
  END t_out[381]
  PIN t_out[382]
    DIRECTION OUTPUT ;
    USE SIGNAL ;
    PORT
      LAYER M4 ;
        RECT 0.000 843.360 0.192 843.384 ;
    END
  END t_out[382]
  PIN t_out[383]
    DIRECTION OUTPUT ;
    USE SIGNAL ;
    PORT
      LAYER M4 ;
        RECT 0.000 843.552 0.192 843.576 ;
    END
  END t_out[383]
  PIN t_out[384]
    DIRECTION OUTPUT ;
    USE SIGNAL ;
    PORT
      LAYER M4 ;
        RECT 0.000 843.744 0.192 843.768 ;
    END
  END t_out[384]
  PIN t_out[385]
    DIRECTION OUTPUT ;
    USE SIGNAL ;
    PORT
      LAYER M4 ;
        RECT 0.000 843.936 0.192 843.960 ;
    END
  END t_out[385]
  PIN t_out[386]
    DIRECTION OUTPUT ;
    USE SIGNAL ;
    PORT
      LAYER M4 ;
        RECT 0.000 844.128 0.192 844.152 ;
    END
  END t_out[386]
  PIN t_out[387]
    DIRECTION OUTPUT ;
    USE SIGNAL ;
    PORT
      LAYER M4 ;
        RECT 0.000 844.320 0.192 844.344 ;
    END
  END t_out[387]
  PIN t_out[388]
    DIRECTION OUTPUT ;
    USE SIGNAL ;
    PORT
      LAYER M4 ;
        RECT 0.000 844.512 0.192 844.536 ;
    END
  END t_out[388]
  PIN t_out[389]
    DIRECTION OUTPUT ;
    USE SIGNAL ;
    PORT
      LAYER M4 ;
        RECT 0.000 844.704 0.192 844.728 ;
    END
  END t_out[389]
  PIN t_out[390]
    DIRECTION OUTPUT ;
    USE SIGNAL ;
    PORT
      LAYER M4 ;
        RECT 0.000 844.896 0.192 844.920 ;
    END
  END t_out[390]
  PIN t_out[391]
    DIRECTION OUTPUT ;
    USE SIGNAL ;
    PORT
      LAYER M4 ;
        RECT 0.000 845.088 0.192 845.112 ;
    END
  END t_out[391]
  PIN t_out[392]
    DIRECTION OUTPUT ;
    USE SIGNAL ;
    PORT
      LAYER M4 ;
        RECT 0.000 845.280 0.192 845.304 ;
    END
  END t_out[392]
  PIN t_out[393]
    DIRECTION OUTPUT ;
    USE SIGNAL ;
    PORT
      LAYER M4 ;
        RECT 0.000 845.472 0.192 845.496 ;
    END
  END t_out[393]
  PIN t_out[394]
    DIRECTION OUTPUT ;
    USE SIGNAL ;
    PORT
      LAYER M4 ;
        RECT 0.000 845.664 0.192 845.688 ;
    END
  END t_out[394]
  PIN t_out[395]
    DIRECTION OUTPUT ;
    USE SIGNAL ;
    PORT
      LAYER M4 ;
        RECT 0.000 845.856 0.192 845.880 ;
    END
  END t_out[395]
  PIN t_out[396]
    DIRECTION OUTPUT ;
    USE SIGNAL ;
    PORT
      LAYER M4 ;
        RECT 0.000 846.048 0.192 846.072 ;
    END
  END t_out[396]
  PIN t_out[397]
    DIRECTION OUTPUT ;
    USE SIGNAL ;
    PORT
      LAYER M4 ;
        RECT 0.000 846.240 0.192 846.264 ;
    END
  END t_out[397]
  PIN t_out[398]
    DIRECTION OUTPUT ;
    USE SIGNAL ;
    PORT
      LAYER M4 ;
        RECT 0.000 846.432 0.192 846.456 ;
    END
  END t_out[398]
  PIN t_out[399]
    DIRECTION OUTPUT ;
    USE SIGNAL ;
    PORT
      LAYER M4 ;
        RECT 0.000 846.624 0.192 846.648 ;
    END
  END t_out[399]
  PIN t_out[400]
    DIRECTION OUTPUT ;
    USE SIGNAL ;
    PORT
      LAYER M4 ;
        RECT 0.000 846.816 0.192 846.840 ;
    END
  END t_out[400]
  PIN t_out[401]
    DIRECTION OUTPUT ;
    USE SIGNAL ;
    PORT
      LAYER M4 ;
        RECT 0.000 847.008 0.192 847.032 ;
    END
  END t_out[401]
  PIN t_out[402]
    DIRECTION OUTPUT ;
    USE SIGNAL ;
    PORT
      LAYER M4 ;
        RECT 0.000 847.200 0.192 847.224 ;
    END
  END t_out[402]
  PIN t_out[403]
    DIRECTION OUTPUT ;
    USE SIGNAL ;
    PORT
      LAYER M4 ;
        RECT 0.000 847.392 0.192 847.416 ;
    END
  END t_out[403]
  PIN t_out[404]
    DIRECTION OUTPUT ;
    USE SIGNAL ;
    PORT
      LAYER M4 ;
        RECT 0.000 847.584 0.192 847.608 ;
    END
  END t_out[404]
  PIN t_out[405]
    DIRECTION OUTPUT ;
    USE SIGNAL ;
    PORT
      LAYER M4 ;
        RECT 0.000 847.776 0.192 847.800 ;
    END
  END t_out[405]
  PIN t_out[406]
    DIRECTION OUTPUT ;
    USE SIGNAL ;
    PORT
      LAYER M4 ;
        RECT 0.000 847.968 0.192 847.992 ;
    END
  END t_out[406]
  PIN t_out[407]
    DIRECTION OUTPUT ;
    USE SIGNAL ;
    PORT
      LAYER M4 ;
        RECT 0.000 848.160 0.192 848.184 ;
    END
  END t_out[407]
  PIN t_out[408]
    DIRECTION OUTPUT ;
    USE SIGNAL ;
    PORT
      LAYER M4 ;
        RECT 0.000 848.352 0.192 848.376 ;
    END
  END t_out[408]
  PIN t_out[409]
    DIRECTION OUTPUT ;
    USE SIGNAL ;
    PORT
      LAYER M4 ;
        RECT 0.000 848.544 0.192 848.568 ;
    END
  END t_out[409]
  PIN t_out[410]
    DIRECTION OUTPUT ;
    USE SIGNAL ;
    PORT
      LAYER M4 ;
        RECT 0.000 848.736 0.192 848.760 ;
    END
  END t_out[410]
  PIN t_out[411]
    DIRECTION OUTPUT ;
    USE SIGNAL ;
    PORT
      LAYER M4 ;
        RECT 0.000 848.928 0.192 848.952 ;
    END
  END t_out[411]
  PIN t_out[412]
    DIRECTION OUTPUT ;
    USE SIGNAL ;
    PORT
      LAYER M4 ;
        RECT 0.000 849.120 0.192 849.144 ;
    END
  END t_out[412]
  PIN t_out[413]
    DIRECTION OUTPUT ;
    USE SIGNAL ;
    PORT
      LAYER M4 ;
        RECT 0.000 849.312 0.192 849.336 ;
    END
  END t_out[413]
  PIN t_out[414]
    DIRECTION OUTPUT ;
    USE SIGNAL ;
    PORT
      LAYER M4 ;
        RECT 0.000 849.504 0.192 849.528 ;
    END
  END t_out[414]
  PIN t_out[415]
    DIRECTION OUTPUT ;
    USE SIGNAL ;
    PORT
      LAYER M4 ;
        RECT 0.000 849.696 0.192 849.720 ;
    END
  END t_out[415]
  PIN t_out[416]
    DIRECTION OUTPUT ;
    USE SIGNAL ;
    PORT
      LAYER M4 ;
        RECT 0.000 849.888 0.192 849.912 ;
    END
  END t_out[416]
  PIN t_out[417]
    DIRECTION OUTPUT ;
    USE SIGNAL ;
    PORT
      LAYER M4 ;
        RECT 0.000 850.080 0.192 850.104 ;
    END
  END t_out[417]
  PIN t_out[418]
    DIRECTION OUTPUT ;
    USE SIGNAL ;
    PORT
      LAYER M4 ;
        RECT 0.000 850.272 0.192 850.296 ;
    END
  END t_out[418]
  PIN t_out[419]
    DIRECTION OUTPUT ;
    USE SIGNAL ;
    PORT
      LAYER M4 ;
        RECT 0.000 850.464 0.192 850.488 ;
    END
  END t_out[419]
  PIN t_out[420]
    DIRECTION OUTPUT ;
    USE SIGNAL ;
    PORT
      LAYER M4 ;
        RECT 0.000 850.656 0.192 850.680 ;
    END
  END t_out[420]
  PIN t_out[421]
    DIRECTION OUTPUT ;
    USE SIGNAL ;
    PORT
      LAYER M4 ;
        RECT 0.000 850.848 0.192 850.872 ;
    END
  END t_out[421]
  PIN t_out[422]
    DIRECTION OUTPUT ;
    USE SIGNAL ;
    PORT
      LAYER M4 ;
        RECT 0.000 851.040 0.192 851.064 ;
    END
  END t_out[422]
  PIN t_out[423]
    DIRECTION OUTPUT ;
    USE SIGNAL ;
    PORT
      LAYER M4 ;
        RECT 0.000 851.232 0.192 851.256 ;
    END
  END t_out[423]
  PIN t_out[424]
    DIRECTION OUTPUT ;
    USE SIGNAL ;
    PORT
      LAYER M4 ;
        RECT 0.000 851.424 0.192 851.448 ;
    END
  END t_out[424]
  PIN t_out[425]
    DIRECTION OUTPUT ;
    USE SIGNAL ;
    PORT
      LAYER M4 ;
        RECT 0.000 851.616 0.192 851.640 ;
    END
  END t_out[425]
  PIN t_out[426]
    DIRECTION OUTPUT ;
    USE SIGNAL ;
    PORT
      LAYER M4 ;
        RECT 0.000 851.808 0.192 851.832 ;
    END
  END t_out[426]
  PIN t_out[427]
    DIRECTION OUTPUT ;
    USE SIGNAL ;
    PORT
      LAYER M4 ;
        RECT 0.000 852.000 0.192 852.024 ;
    END
  END t_out[427]
  PIN t_out[428]
    DIRECTION OUTPUT ;
    USE SIGNAL ;
    PORT
      LAYER M4 ;
        RECT 0.000 852.192 0.192 852.216 ;
    END
  END t_out[428]
  PIN t_out[429]
    DIRECTION OUTPUT ;
    USE SIGNAL ;
    PORT
      LAYER M4 ;
        RECT 0.000 852.384 0.192 852.408 ;
    END
  END t_out[429]
  PIN t_out[430]
    DIRECTION OUTPUT ;
    USE SIGNAL ;
    PORT
      LAYER M4 ;
        RECT 0.000 852.576 0.192 852.600 ;
    END
  END t_out[430]
  PIN t_out[431]
    DIRECTION OUTPUT ;
    USE SIGNAL ;
    PORT
      LAYER M4 ;
        RECT 0.000 852.768 0.192 852.792 ;
    END
  END t_out[431]
  PIN t_out[432]
    DIRECTION OUTPUT ;
    USE SIGNAL ;
    PORT
      LAYER M4 ;
        RECT 0.000 852.960 0.192 852.984 ;
    END
  END t_out[432]
  PIN t_out[433]
    DIRECTION OUTPUT ;
    USE SIGNAL ;
    PORT
      LAYER M4 ;
        RECT 0.000 853.152 0.192 853.176 ;
    END
  END t_out[433]
  PIN t_out[434]
    DIRECTION OUTPUT ;
    USE SIGNAL ;
    PORT
      LAYER M4 ;
        RECT 0.000 853.344 0.192 853.368 ;
    END
  END t_out[434]
  PIN t_out[435]
    DIRECTION OUTPUT ;
    USE SIGNAL ;
    PORT
      LAYER M4 ;
        RECT 0.000 853.536 0.192 853.560 ;
    END
  END t_out[435]
  PIN t_out[436]
    DIRECTION OUTPUT ;
    USE SIGNAL ;
    PORT
      LAYER M4 ;
        RECT 0.000 853.728 0.192 853.752 ;
    END
  END t_out[436]
  PIN t_out[437]
    DIRECTION OUTPUT ;
    USE SIGNAL ;
    PORT
      LAYER M4 ;
        RECT 0.000 853.920 0.192 853.944 ;
    END
  END t_out[437]
  PIN t_out[438]
    DIRECTION OUTPUT ;
    USE SIGNAL ;
    PORT
      LAYER M4 ;
        RECT 0.000 854.112 0.192 854.136 ;
    END
  END t_out[438]
  PIN t_out[439]
    DIRECTION OUTPUT ;
    USE SIGNAL ;
    PORT
      LAYER M4 ;
        RECT 0.000 854.304 0.192 854.328 ;
    END
  END t_out[439]
  PIN t_out[440]
    DIRECTION OUTPUT ;
    USE SIGNAL ;
    PORT
      LAYER M4 ;
        RECT 0.000 854.496 0.192 854.520 ;
    END
  END t_out[440]
  PIN t_out[441]
    DIRECTION OUTPUT ;
    USE SIGNAL ;
    PORT
      LAYER M4 ;
        RECT 0.000 854.688 0.192 854.712 ;
    END
  END t_out[441]
  PIN t_out[442]
    DIRECTION OUTPUT ;
    USE SIGNAL ;
    PORT
      LAYER M4 ;
        RECT 0.000 854.880 0.192 854.904 ;
    END
  END t_out[442]
  PIN t_out[443]
    DIRECTION OUTPUT ;
    USE SIGNAL ;
    PORT
      LAYER M4 ;
        RECT 0.000 855.072 0.192 855.096 ;
    END
  END t_out[443]
  PIN t_out[444]
    DIRECTION OUTPUT ;
    USE SIGNAL ;
    PORT
      LAYER M4 ;
        RECT 0.000 855.264 0.192 855.288 ;
    END
  END t_out[444]
  PIN t_out[445]
    DIRECTION OUTPUT ;
    USE SIGNAL ;
    PORT
      LAYER M4 ;
        RECT 0.000 855.456 0.192 855.480 ;
    END
  END t_out[445]
  PIN t_out[446]
    DIRECTION OUTPUT ;
    USE SIGNAL ;
    PORT
      LAYER M4 ;
        RECT 0.000 855.648 0.192 855.672 ;
    END
  END t_out[446]
  PIN t_out[447]
    DIRECTION OUTPUT ;
    USE SIGNAL ;
    PORT
      LAYER M4 ;
        RECT 0.000 855.840 0.192 855.864 ;
    END
  END t_out[447]
  PIN t_out[448]
    DIRECTION OUTPUT ;
    USE SIGNAL ;
    PORT
      LAYER M4 ;
        RECT 0.000 856.032 0.192 856.056 ;
    END
  END t_out[448]
  PIN t_out[449]
    DIRECTION OUTPUT ;
    USE SIGNAL ;
    PORT
      LAYER M4 ;
        RECT 0.000 856.224 0.192 856.248 ;
    END
  END t_out[449]
  PIN t_out[450]
    DIRECTION OUTPUT ;
    USE SIGNAL ;
    PORT
      LAYER M4 ;
        RECT 0.000 856.416 0.192 856.440 ;
    END
  END t_out[450]
  PIN t_out[451]
    DIRECTION OUTPUT ;
    USE SIGNAL ;
    PORT
      LAYER M4 ;
        RECT 0.000 856.608 0.192 856.632 ;
    END
  END t_out[451]
  PIN t_out[452]
    DIRECTION OUTPUT ;
    USE SIGNAL ;
    PORT
      LAYER M4 ;
        RECT 0.000 856.800 0.192 856.824 ;
    END
  END t_out[452]
  PIN t_out[453]
    DIRECTION OUTPUT ;
    USE SIGNAL ;
    PORT
      LAYER M4 ;
        RECT 0.000 856.992 0.192 857.016 ;
    END
  END t_out[453]
  PIN t_out[454]
    DIRECTION OUTPUT ;
    USE SIGNAL ;
    PORT
      LAYER M4 ;
        RECT 0.000 857.184 0.192 857.208 ;
    END
  END t_out[454]
  PIN t_out[455]
    DIRECTION OUTPUT ;
    USE SIGNAL ;
    PORT
      LAYER M4 ;
        RECT 0.000 857.376 0.192 857.400 ;
    END
  END t_out[455]
  PIN t_out[456]
    DIRECTION OUTPUT ;
    USE SIGNAL ;
    PORT
      LAYER M4 ;
        RECT 0.000 857.568 0.192 857.592 ;
    END
  END t_out[456]
  PIN t_out[457]
    DIRECTION OUTPUT ;
    USE SIGNAL ;
    PORT
      LAYER M4 ;
        RECT 0.000 857.760 0.192 857.784 ;
    END
  END t_out[457]
  PIN t_out[458]
    DIRECTION OUTPUT ;
    USE SIGNAL ;
    PORT
      LAYER M4 ;
        RECT 0.000 857.952 0.192 857.976 ;
    END
  END t_out[458]
  PIN t_out[459]
    DIRECTION OUTPUT ;
    USE SIGNAL ;
    PORT
      LAYER M4 ;
        RECT 0.000 858.144 0.192 858.168 ;
    END
  END t_out[459]
  PIN t_out[460]
    DIRECTION OUTPUT ;
    USE SIGNAL ;
    PORT
      LAYER M4 ;
        RECT 0.000 858.336 0.192 858.360 ;
    END
  END t_out[460]
  PIN t_out[461]
    DIRECTION OUTPUT ;
    USE SIGNAL ;
    PORT
      LAYER M4 ;
        RECT 0.000 858.528 0.192 858.552 ;
    END
  END t_out[461]
  PIN t_out[462]
    DIRECTION OUTPUT ;
    USE SIGNAL ;
    PORT
      LAYER M4 ;
        RECT 0.000 858.720 0.192 858.744 ;
    END
  END t_out[462]
  PIN t_out[463]
    DIRECTION OUTPUT ;
    USE SIGNAL ;
    PORT
      LAYER M4 ;
        RECT 0.000 858.912 0.192 858.936 ;
    END
  END t_out[463]
  PIN t_out[464]
    DIRECTION OUTPUT ;
    USE SIGNAL ;
    PORT
      LAYER M4 ;
        RECT 0.000 859.104 0.192 859.128 ;
    END
  END t_out[464]
  PIN t_out[465]
    DIRECTION OUTPUT ;
    USE SIGNAL ;
    PORT
      LAYER M4 ;
        RECT 0.000 859.296 0.192 859.320 ;
    END
  END t_out[465]
  PIN t_out[466]
    DIRECTION OUTPUT ;
    USE SIGNAL ;
    PORT
      LAYER M4 ;
        RECT 0.000 859.488 0.192 859.512 ;
    END
  END t_out[466]
  PIN t_out[467]
    DIRECTION OUTPUT ;
    USE SIGNAL ;
    PORT
      LAYER M4 ;
        RECT 0.000 859.680 0.192 859.704 ;
    END
  END t_out[467]
  PIN t_out[468]
    DIRECTION OUTPUT ;
    USE SIGNAL ;
    PORT
      LAYER M4 ;
        RECT 0.000 859.872 0.192 859.896 ;
    END
  END t_out[468]
  PIN t_out[469]
    DIRECTION OUTPUT ;
    USE SIGNAL ;
    PORT
      LAYER M4 ;
        RECT 0.000 860.064 0.192 860.088 ;
    END
  END t_out[469]
  PIN t_out[470]
    DIRECTION OUTPUT ;
    USE SIGNAL ;
    PORT
      LAYER M4 ;
        RECT 0.000 860.256 0.192 860.280 ;
    END
  END t_out[470]
  PIN t_out[471]
    DIRECTION OUTPUT ;
    USE SIGNAL ;
    PORT
      LAYER M4 ;
        RECT 0.000 860.448 0.192 860.472 ;
    END
  END t_out[471]
  PIN t_out[472]
    DIRECTION OUTPUT ;
    USE SIGNAL ;
    PORT
      LAYER M4 ;
        RECT 0.000 860.640 0.192 860.664 ;
    END
  END t_out[472]
  PIN t_out[473]
    DIRECTION OUTPUT ;
    USE SIGNAL ;
    PORT
      LAYER M4 ;
        RECT 0.000 860.832 0.192 860.856 ;
    END
  END t_out[473]
  PIN t_out[474]
    DIRECTION OUTPUT ;
    USE SIGNAL ;
    PORT
      LAYER M4 ;
        RECT 0.000 861.024 0.192 861.048 ;
    END
  END t_out[474]
  PIN t_out[475]
    DIRECTION OUTPUT ;
    USE SIGNAL ;
    PORT
      LAYER M4 ;
        RECT 0.000 861.216 0.192 861.240 ;
    END
  END t_out[475]
  PIN t_out[476]
    DIRECTION OUTPUT ;
    USE SIGNAL ;
    PORT
      LAYER M4 ;
        RECT 0.000 861.408 0.192 861.432 ;
    END
  END t_out[476]
  PIN t_out[477]
    DIRECTION OUTPUT ;
    USE SIGNAL ;
    PORT
      LAYER M4 ;
        RECT 0.000 861.600 0.192 861.624 ;
    END
  END t_out[477]
  PIN t_out[478]
    DIRECTION OUTPUT ;
    USE SIGNAL ;
    PORT
      LAYER M4 ;
        RECT 0.000 861.792 0.192 861.816 ;
    END
  END t_out[478]
  PIN t_out[479]
    DIRECTION OUTPUT ;
    USE SIGNAL ;
    PORT
      LAYER M4 ;
        RECT 0.000 861.984 0.192 862.008 ;
    END
  END t_out[479]
  PIN t_out[480]
    DIRECTION OUTPUT ;
    USE SIGNAL ;
    PORT
      LAYER M4 ;
        RECT 0.000 862.176 0.192 862.200 ;
    END
  END t_out[480]
  PIN t_out[481]
    DIRECTION OUTPUT ;
    USE SIGNAL ;
    PORT
      LAYER M4 ;
        RECT 0.000 862.368 0.192 862.392 ;
    END
  END t_out[481]
  PIN t_out[482]
    DIRECTION OUTPUT ;
    USE SIGNAL ;
    PORT
      LAYER M4 ;
        RECT 0.000 862.560 0.192 862.584 ;
    END
  END t_out[482]
  PIN t_out[483]
    DIRECTION OUTPUT ;
    USE SIGNAL ;
    PORT
      LAYER M4 ;
        RECT 0.000 862.752 0.192 862.776 ;
    END
  END t_out[483]
  PIN t_out[484]
    DIRECTION OUTPUT ;
    USE SIGNAL ;
    PORT
      LAYER M4 ;
        RECT 0.000 862.944 0.192 862.968 ;
    END
  END t_out[484]
  PIN t_out[485]
    DIRECTION OUTPUT ;
    USE SIGNAL ;
    PORT
      LAYER M4 ;
        RECT 0.000 863.136 0.192 863.160 ;
    END
  END t_out[485]
  PIN t_out[486]
    DIRECTION OUTPUT ;
    USE SIGNAL ;
    PORT
      LAYER M4 ;
        RECT 0.000 863.328 0.192 863.352 ;
    END
  END t_out[486]
  PIN t_out[487]
    DIRECTION OUTPUT ;
    USE SIGNAL ;
    PORT
      LAYER M4 ;
        RECT 0.000 863.520 0.192 863.544 ;
    END
  END t_out[487]
  PIN t_out[488]
    DIRECTION OUTPUT ;
    USE SIGNAL ;
    PORT
      LAYER M4 ;
        RECT 0.000 863.712 0.192 863.736 ;
    END
  END t_out[488]
  PIN t_out[489]
    DIRECTION OUTPUT ;
    USE SIGNAL ;
    PORT
      LAYER M4 ;
        RECT 0.000 863.904 0.192 863.928 ;
    END
  END t_out[489]
  PIN t_out[490]
    DIRECTION OUTPUT ;
    USE SIGNAL ;
    PORT
      LAYER M4 ;
        RECT 0.000 864.096 0.192 864.120 ;
    END
  END t_out[490]
  PIN t_out[491]
    DIRECTION OUTPUT ;
    USE SIGNAL ;
    PORT
      LAYER M4 ;
        RECT 0.000 864.288 0.192 864.312 ;
    END
  END t_out[491]
  PIN t_out[492]
    DIRECTION OUTPUT ;
    USE SIGNAL ;
    PORT
      LAYER M4 ;
        RECT 0.000 864.480 0.192 864.504 ;
    END
  END t_out[492]
  PIN t_out[493]
    DIRECTION OUTPUT ;
    USE SIGNAL ;
    PORT
      LAYER M4 ;
        RECT 0.000 864.672 0.192 864.696 ;
    END
  END t_out[493]
  PIN t_out[494]
    DIRECTION OUTPUT ;
    USE SIGNAL ;
    PORT
      LAYER M4 ;
        RECT 0.000 864.864 0.192 864.888 ;
    END
  END t_out[494]
  PIN t_out[495]
    DIRECTION OUTPUT ;
    USE SIGNAL ;
    PORT
      LAYER M4 ;
        RECT 0.000 865.056 0.192 865.080 ;
    END
  END t_out[495]
  PIN t_out[496]
    DIRECTION OUTPUT ;
    USE SIGNAL ;
    PORT
      LAYER M4 ;
        RECT 0.000 865.248 0.192 865.272 ;
    END
  END t_out[496]
  PIN t_out[497]
    DIRECTION OUTPUT ;
    USE SIGNAL ;
    PORT
      LAYER M4 ;
        RECT 0.000 865.440 0.192 865.464 ;
    END
  END t_out[497]
  PIN t_out[498]
    DIRECTION OUTPUT ;
    USE SIGNAL ;
    PORT
      LAYER M4 ;
        RECT 0.000 865.632 0.192 865.656 ;
    END
  END t_out[498]
  PIN t_out[499]
    DIRECTION OUTPUT ;
    USE SIGNAL ;
    PORT
      LAYER M4 ;
        RECT 0.000 865.824 0.192 865.848 ;
    END
  END t_out[499]
  PIN t_out[500]
    DIRECTION OUTPUT ;
    USE SIGNAL ;
    PORT
      LAYER M4 ;
        RECT 0.000 866.016 0.192 866.040 ;
    END
  END t_out[500]
  PIN t_out[501]
    DIRECTION OUTPUT ;
    USE SIGNAL ;
    PORT
      LAYER M4 ;
        RECT 0.000 866.208 0.192 866.232 ;
    END
  END t_out[501]
  PIN t_out[502]
    DIRECTION OUTPUT ;
    USE SIGNAL ;
    PORT
      LAYER M4 ;
        RECT 0.000 866.400 0.192 866.424 ;
    END
  END t_out[502]
  PIN t_out[503]
    DIRECTION OUTPUT ;
    USE SIGNAL ;
    PORT
      LAYER M4 ;
        RECT 0.000 866.592 0.192 866.616 ;
    END
  END t_out[503]
  PIN t_out[504]
    DIRECTION OUTPUT ;
    USE SIGNAL ;
    PORT
      LAYER M4 ;
        RECT 0.000 866.784 0.192 866.808 ;
    END
  END t_out[504]
  PIN t_out[505]
    DIRECTION OUTPUT ;
    USE SIGNAL ;
    PORT
      LAYER M4 ;
        RECT 0.000 866.976 0.192 867.000 ;
    END
  END t_out[505]
  PIN t_out[506]
    DIRECTION OUTPUT ;
    USE SIGNAL ;
    PORT
      LAYER M4 ;
        RECT 0.000 867.168 0.192 867.192 ;
    END
  END t_out[506]
  PIN t_out[507]
    DIRECTION OUTPUT ;
    USE SIGNAL ;
    PORT
      LAYER M4 ;
        RECT 0.000 867.360 0.192 867.384 ;
    END
  END t_out[507]
  PIN t_out[508]
    DIRECTION OUTPUT ;
    USE SIGNAL ;
    PORT
      LAYER M4 ;
        RECT 0.000 867.552 0.192 867.576 ;
    END
  END t_out[508]
  PIN t_out[509]
    DIRECTION OUTPUT ;
    USE SIGNAL ;
    PORT
      LAYER M4 ;
        RECT 0.000 867.744 0.192 867.768 ;
    END
  END t_out[509]
  PIN t_out[510]
    DIRECTION OUTPUT ;
    USE SIGNAL ;
    PORT
      LAYER M4 ;
        RECT 0.000 867.936 0.192 867.960 ;
    END
  END t_out[510]
  PIN t_out[511]
    DIRECTION OUTPUT ;
    USE SIGNAL ;
    PORT
      LAYER M4 ;
        RECT 0.000 868.128 0.192 868.152 ;
    END
  END t_out[511]
  PIN t_out[512]
    DIRECTION OUTPUT ;
    USE SIGNAL ;
    PORT
      LAYER M4 ;
        RECT 0.000 868.320 0.192 868.344 ;
    END
  END t_out[512]
  PIN t_out[513]
    DIRECTION OUTPUT ;
    USE SIGNAL ;
    PORT
      LAYER M4 ;
        RECT 0.000 868.512 0.192 868.536 ;
    END
  END t_out[513]
  PIN ck_rp4
    DIRECTION INPUT ;
    USE CLOCK ;
    PORT
      LAYER M4 ;
        RECT 0.000 869.184 0.192 869.208 ;
    END
  END ck_rp4
  PIN ck_fa2
    DIRECTION INPUT ;
    USE CLOCK ;
    PORT
      LAYER M4 ;
        RECT 0.000 873.984 0.192 874.008 ;
    END
  END ck_fa2
  PIN ck_rp5
    DIRECTION INPUT ;
    USE CLOCK ;
    PORT
      LAYER M4 ;
        RECT 820.608 98.304 820.800 98.328 ;
    END
  END ck_rp5
  PIN ck_fa4
    DIRECTION INPUT ;
    USE CLOCK ;
    PORT
      LAYER M4 ;
        RECT 820.608 115.968 820.800 115.992 ;
    END
  END ck_fa4
  PIN tap[0]
    DIRECTION INPUT ;
    USE SIGNAL ;
    PORT
      LAYER M4 ;
        RECT 820.608 120.000 820.800 120.024 ;
    END
  END tap[0]
  PIN tap[1]
    DIRECTION INPUT ;
    USE SIGNAL ;
    PORT
      LAYER M4 ;
        RECT 820.608 120.192 820.800 120.216 ;
    END
  END tap[1]
  PIN tap[2]
    DIRECTION INPUT ;
    USE SIGNAL ;
    PORT
      LAYER M4 ;
        RECT 820.608 120.384 820.800 120.408 ;
    END
  END tap[2]
  PIN tap[3]
    DIRECTION INPUT ;
    USE SIGNAL ;
    PORT
      LAYER M4 ;
        RECT 820.608 120.576 820.800 120.600 ;
    END
  END tap[3]
  PIN tap[4]
    DIRECTION INPUT ;
    USE SIGNAL ;
    PORT
      LAYER M4 ;
        RECT 820.608 120.768 820.800 120.792 ;
    END
  END tap[4]
  PIN tap[5]
    DIRECTION INPUT ;
    USE SIGNAL ;
    PORT
      LAYER M4 ;
        RECT 820.608 120.960 820.800 120.984 ;
    END
  END tap[5]
  PIN tap[6]
    DIRECTION INPUT ;
    USE SIGNAL ;
    PORT
      LAYER M4 ;
        RECT 820.608 121.152 820.800 121.176 ;
    END
  END tap[6]
  PIN tap[7]
    DIRECTION INPUT ;
    USE SIGNAL ;
    PORT
      LAYER M4 ;
        RECT 820.608 121.344 820.800 121.368 ;
    END
  END tap[7]
  PIN tap[8]
    DIRECTION INPUT ;
    USE SIGNAL ;
    PORT
      LAYER M4 ;
        RECT 820.608 121.536 820.800 121.560 ;
    END
  END tap[8]
  PIN tap[9]
    DIRECTION INPUT ;
    USE SIGNAL ;
    PORT
      LAYER M4 ;
        RECT 820.608 121.728 820.800 121.752 ;
    END
  END tap[9]
  PIN tap[10]
    DIRECTION INPUT ;
    USE SIGNAL ;
    PORT
      LAYER M4 ;
        RECT 820.608 121.920 820.800 121.944 ;
    END
  END tap[10]
  PIN tap[11]
    DIRECTION INPUT ;
    USE SIGNAL ;
    PORT
      LAYER M4 ;
        RECT 820.608 122.112 820.800 122.136 ;
    END
  END tap[11]
  PIN tap[12]
    DIRECTION INPUT ;
    USE SIGNAL ;
    PORT
      LAYER M4 ;
        RECT 820.608 122.304 820.800 122.328 ;
    END
  END tap[12]
  PIN tap[13]
    DIRECTION INPUT ;
    USE SIGNAL ;
    PORT
      LAYER M4 ;
        RECT 820.608 122.496 820.800 122.520 ;
    END
  END tap[13]
  PIN tap[14]
    DIRECTION INPUT ;
    USE SIGNAL ;
    PORT
      LAYER M4 ;
        RECT 820.608 122.688 820.800 122.712 ;
    END
  END tap[14]
  PIN tap[15]
    DIRECTION INPUT ;
    USE SIGNAL ;
    PORT
      LAYER M4 ;
        RECT 820.608 122.880 820.800 122.904 ;
    END
  END tap[15]
  PIN tap[16]
    DIRECTION INPUT ;
    USE SIGNAL ;
    PORT
      LAYER M4 ;
        RECT 820.608 123.072 820.800 123.096 ;
    END
  END tap[16]
  PIN tap[17]
    DIRECTION INPUT ;
    USE SIGNAL ;
    PORT
      LAYER M4 ;
        RECT 820.608 123.264 820.800 123.288 ;
    END
  END tap[17]
  PIN tap[18]
    DIRECTION INPUT ;
    USE SIGNAL ;
    PORT
      LAYER M4 ;
        RECT 820.608 123.456 820.800 123.480 ;
    END
  END tap[18]
  PIN tap[19]
    DIRECTION INPUT ;
    USE SIGNAL ;
    PORT
      LAYER M4 ;
        RECT 820.608 123.648 820.800 123.672 ;
    END
  END tap[19]
  PIN tap[20]
    DIRECTION INPUT ;
    USE SIGNAL ;
    PORT
      LAYER M4 ;
        RECT 820.608 123.840 820.800 123.864 ;
    END
  END tap[20]
  PIN tap[21]
    DIRECTION INPUT ;
    USE SIGNAL ;
    PORT
      LAYER M4 ;
        RECT 820.608 124.032 820.800 124.056 ;
    END
  END tap[21]
  PIN tap[22]
    DIRECTION INPUT ;
    USE SIGNAL ;
    PORT
      LAYER M4 ;
        RECT 820.608 124.224 820.800 124.248 ;
    END
  END tap[22]
  PIN tap[23]
    DIRECTION INPUT ;
    USE SIGNAL ;
    PORT
      LAYER M4 ;
        RECT 820.608 124.416 820.800 124.440 ;
    END
  END tap[23]
  PIN tap[24]
    DIRECTION INPUT ;
    USE SIGNAL ;
    PORT
      LAYER M4 ;
        RECT 820.608 124.608 820.800 124.632 ;
    END
  END tap[24]
  PIN tap[25]
    DIRECTION INPUT ;
    USE SIGNAL ;
    PORT
      LAYER M4 ;
        RECT 820.608 124.800 820.800 124.824 ;
    END
  END tap[25]
  PIN tap[26]
    DIRECTION INPUT ;
    USE SIGNAL ;
    PORT
      LAYER M4 ;
        RECT 820.608 124.992 820.800 125.016 ;
    END
  END tap[26]
  PIN tap[27]
    DIRECTION INPUT ;
    USE SIGNAL ;
    PORT
      LAYER M4 ;
        RECT 820.608 125.184 820.800 125.208 ;
    END
  END tap[27]
  PIN tap[28]
    DIRECTION INPUT ;
    USE SIGNAL ;
    PORT
      LAYER M4 ;
        RECT 820.608 125.376 820.800 125.400 ;
    END
  END tap[28]
  PIN tap[29]
    DIRECTION INPUT ;
    USE SIGNAL ;
    PORT
      LAYER M4 ;
        RECT 820.608 125.568 820.800 125.592 ;
    END
  END tap[29]
  PIN tap[30]
    DIRECTION INPUT ;
    USE SIGNAL ;
    PORT
      LAYER M4 ;
        RECT 820.608 125.760 820.800 125.784 ;
    END
  END tap[30]
  PIN tap[31]
    DIRECTION INPUT ;
    USE SIGNAL ;
    PORT
      LAYER M4 ;
        RECT 820.608 125.952 820.800 125.976 ;
    END
  END tap[31]
  PIN tap[32]
    DIRECTION INPUT ;
    USE SIGNAL ;
    PORT
      LAYER M4 ;
        RECT 820.608 126.144 820.800 126.168 ;
    END
  END tap[32]
  PIN tap[33]
    DIRECTION INPUT ;
    USE SIGNAL ;
    PORT
      LAYER M4 ;
        RECT 820.608 126.336 820.800 126.360 ;
    END
  END tap[33]
  PIN tap[34]
    DIRECTION INPUT ;
    USE SIGNAL ;
    PORT
      LAYER M4 ;
        RECT 820.608 126.528 820.800 126.552 ;
    END
  END tap[34]
  PIN tap[35]
    DIRECTION INPUT ;
    USE SIGNAL ;
    PORT
      LAYER M4 ;
        RECT 820.608 126.720 820.800 126.744 ;
    END
  END tap[35]
  PIN tap[36]
    DIRECTION INPUT ;
    USE SIGNAL ;
    PORT
      LAYER M4 ;
        RECT 820.608 126.912 820.800 126.936 ;
    END
  END tap[36]
  PIN tap[37]
    DIRECTION INPUT ;
    USE SIGNAL ;
    PORT
      LAYER M4 ;
        RECT 820.608 127.104 820.800 127.128 ;
    END
  END tap[37]
  PIN tap[38]
    DIRECTION INPUT ;
    USE SIGNAL ;
    PORT
      LAYER M4 ;
        RECT 820.608 127.296 820.800 127.320 ;
    END
  END tap[38]
  PIN tap[39]
    DIRECTION INPUT ;
    USE SIGNAL ;
    PORT
      LAYER M4 ;
        RECT 820.608 127.488 820.800 127.512 ;
    END
  END tap[39]
  PIN tap[40]
    DIRECTION INPUT ;
    USE SIGNAL ;
    PORT
      LAYER M4 ;
        RECT 820.608 127.680 820.800 127.704 ;
    END
  END tap[40]
  PIN tap[41]
    DIRECTION INPUT ;
    USE SIGNAL ;
    PORT
      LAYER M4 ;
        RECT 820.608 127.872 820.800 127.896 ;
    END
  END tap[41]
  PIN tap[42]
    DIRECTION INPUT ;
    USE SIGNAL ;
    PORT
      LAYER M4 ;
        RECT 820.608 128.064 820.800 128.088 ;
    END
  END tap[42]
  PIN tap[43]
    DIRECTION INPUT ;
    USE SIGNAL ;
    PORT
      LAYER M4 ;
        RECT 820.608 128.256 820.800 128.280 ;
    END
  END tap[43]
  PIN tap[44]
    DIRECTION INPUT ;
    USE SIGNAL ;
    PORT
      LAYER M4 ;
        RECT 820.608 128.448 820.800 128.472 ;
    END
  END tap[44]
  PIN tap[45]
    DIRECTION INPUT ;
    USE SIGNAL ;
    PORT
      LAYER M4 ;
        RECT 820.608 128.640 820.800 128.664 ;
    END
  END tap[45]
  PIN tap[46]
    DIRECTION INPUT ;
    USE SIGNAL ;
    PORT
      LAYER M4 ;
        RECT 820.608 128.832 820.800 128.856 ;
    END
  END tap[46]
  PIN tap[47]
    DIRECTION INPUT ;
    USE SIGNAL ;
    PORT
      LAYER M4 ;
        RECT 820.608 129.024 820.800 129.048 ;
    END
  END tap[47]
  PIN tap[48]
    DIRECTION INPUT ;
    USE SIGNAL ;
    PORT
      LAYER M4 ;
        RECT 820.608 129.216 820.800 129.240 ;
    END
  END tap[48]
  PIN tap[49]
    DIRECTION INPUT ;
    USE SIGNAL ;
    PORT
      LAYER M4 ;
        RECT 820.608 129.408 820.800 129.432 ;
    END
  END tap[49]
  PIN tap[50]
    DIRECTION INPUT ;
    USE SIGNAL ;
    PORT
      LAYER M4 ;
        RECT 820.608 129.600 820.800 129.624 ;
    END
  END tap[50]
  PIN tap[51]
    DIRECTION INPUT ;
    USE SIGNAL ;
    PORT
      LAYER M4 ;
        RECT 820.608 129.792 820.800 129.816 ;
    END
  END tap[51]
  PIN tap[52]
    DIRECTION INPUT ;
    USE SIGNAL ;
    PORT
      LAYER M4 ;
        RECT 820.608 129.984 820.800 130.008 ;
    END
  END tap[52]
  PIN tap[53]
    DIRECTION INPUT ;
    USE SIGNAL ;
    PORT
      LAYER M4 ;
        RECT 820.608 130.176 820.800 130.200 ;
    END
  END tap[53]
  PIN tap[54]
    DIRECTION INPUT ;
    USE SIGNAL ;
    PORT
      LAYER M4 ;
        RECT 820.608 130.368 820.800 130.392 ;
    END
  END tap[54]
  PIN tap[55]
    DIRECTION INPUT ;
    USE SIGNAL ;
    PORT
      LAYER M4 ;
        RECT 820.608 130.560 820.800 130.584 ;
    END
  END tap[55]
  PIN tap[56]
    DIRECTION INPUT ;
    USE SIGNAL ;
    PORT
      LAYER M4 ;
        RECT 820.608 130.752 820.800 130.776 ;
    END
  END tap[56]
  PIN tap[57]
    DIRECTION INPUT ;
    USE SIGNAL ;
    PORT
      LAYER M4 ;
        RECT 820.608 130.944 820.800 130.968 ;
    END
  END tap[57]
  PIN tap[58]
    DIRECTION INPUT ;
    USE SIGNAL ;
    PORT
      LAYER M4 ;
        RECT 820.608 131.136 820.800 131.160 ;
    END
  END tap[58]
  PIN tap[59]
    DIRECTION INPUT ;
    USE SIGNAL ;
    PORT
      LAYER M4 ;
        RECT 820.608 131.328 820.800 131.352 ;
    END
  END tap[59]
  PIN tap[60]
    DIRECTION INPUT ;
    USE SIGNAL ;
    PORT
      LAYER M4 ;
        RECT 820.608 131.520 820.800 131.544 ;
    END
  END tap[60]
  PIN tap[61]
    DIRECTION INPUT ;
    USE SIGNAL ;
    PORT
      LAYER M4 ;
        RECT 820.608 131.712 820.800 131.736 ;
    END
  END tap[61]
  PIN tap[62]
    DIRECTION INPUT ;
    USE SIGNAL ;
    PORT
      LAYER M4 ;
        RECT 820.608 131.904 820.800 131.928 ;
    END
  END tap[62]
  PIN tap[63]
    DIRECTION INPUT ;
    USE SIGNAL ;
    PORT
      LAYER M4 ;
        RECT 820.608 132.096 820.800 132.120 ;
    END
  END tap[63]
  PIN tap[64]
    DIRECTION INPUT ;
    USE SIGNAL ;
    PORT
      LAYER M4 ;
        RECT 820.608 132.288 820.800 132.312 ;
    END
  END tap[64]
  PIN tap[65]
    DIRECTION INPUT ;
    USE SIGNAL ;
    PORT
      LAYER M4 ;
        RECT 820.608 132.480 820.800 132.504 ;
    END
  END tap[65]
  PIN tap[66]
    DIRECTION INPUT ;
    USE SIGNAL ;
    PORT
      LAYER M4 ;
        RECT 820.608 132.672 820.800 132.696 ;
    END
  END tap[66]
  PIN tap[67]
    DIRECTION INPUT ;
    USE SIGNAL ;
    PORT
      LAYER M4 ;
        RECT 820.608 132.864 820.800 132.888 ;
    END
  END tap[67]
  PIN tap[68]
    DIRECTION INPUT ;
    USE SIGNAL ;
    PORT
      LAYER M4 ;
        RECT 820.608 133.056 820.800 133.080 ;
    END
  END tap[68]
  PIN tap[69]
    DIRECTION INPUT ;
    USE SIGNAL ;
    PORT
      LAYER M4 ;
        RECT 820.608 133.248 820.800 133.272 ;
    END
  END tap[69]
  PIN tap[70]
    DIRECTION INPUT ;
    USE SIGNAL ;
    PORT
      LAYER M4 ;
        RECT 820.608 133.440 820.800 133.464 ;
    END
  END tap[70]
  PIN tap[71]
    DIRECTION INPUT ;
    USE SIGNAL ;
    PORT
      LAYER M4 ;
        RECT 820.608 133.632 820.800 133.656 ;
    END
  END tap[71]
  PIN tap[72]
    DIRECTION INPUT ;
    USE SIGNAL ;
    PORT
      LAYER M4 ;
        RECT 820.608 133.824 820.800 133.848 ;
    END
  END tap[72]
  PIN tap[73]
    DIRECTION INPUT ;
    USE SIGNAL ;
    PORT
      LAYER M4 ;
        RECT 820.608 134.016 820.800 134.040 ;
    END
  END tap[73]
  PIN tap[74]
    DIRECTION INPUT ;
    USE SIGNAL ;
    PORT
      LAYER M4 ;
        RECT 820.608 134.208 820.800 134.232 ;
    END
  END tap[74]
  PIN tap[75]
    DIRECTION INPUT ;
    USE SIGNAL ;
    PORT
      LAYER M4 ;
        RECT 820.608 134.400 820.800 134.424 ;
    END
  END tap[75]
  PIN tap[76]
    DIRECTION INPUT ;
    USE SIGNAL ;
    PORT
      LAYER M4 ;
        RECT 820.608 134.592 820.800 134.616 ;
    END
  END tap[76]
  PIN tap[77]
    DIRECTION INPUT ;
    USE SIGNAL ;
    PORT
      LAYER M4 ;
        RECT 820.608 134.784 820.800 134.808 ;
    END
  END tap[77]
  PIN tap[78]
    DIRECTION INPUT ;
    USE SIGNAL ;
    PORT
      LAYER M4 ;
        RECT 820.608 134.976 820.800 135.000 ;
    END
  END tap[78]
  PIN tap[79]
    DIRECTION INPUT ;
    USE SIGNAL ;
    PORT
      LAYER M4 ;
        RECT 820.608 135.168 820.800 135.192 ;
    END
  END tap[79]
  PIN tap[80]
    DIRECTION INPUT ;
    USE SIGNAL ;
    PORT
      LAYER M4 ;
        RECT 820.608 135.360 820.800 135.384 ;
    END
  END tap[80]
  PIN tap[81]
    DIRECTION INPUT ;
    USE SIGNAL ;
    PORT
      LAYER M4 ;
        RECT 820.608 135.552 820.800 135.576 ;
    END
  END tap[81]
  PIN tap[82]
    DIRECTION INPUT ;
    USE SIGNAL ;
    PORT
      LAYER M4 ;
        RECT 820.608 135.744 820.800 135.768 ;
    END
  END tap[82]
  PIN tap[83]
    DIRECTION INPUT ;
    USE SIGNAL ;
    PORT
      LAYER M4 ;
        RECT 820.608 135.936 820.800 135.960 ;
    END
  END tap[83]
  PIN tap[84]
    DIRECTION INPUT ;
    USE SIGNAL ;
    PORT
      LAYER M4 ;
        RECT 820.608 136.128 820.800 136.152 ;
    END
  END tap[84]
  PIN tap[85]
    DIRECTION INPUT ;
    USE SIGNAL ;
    PORT
      LAYER M4 ;
        RECT 820.608 136.320 820.800 136.344 ;
    END
  END tap[85]
  PIN tap[86]
    DIRECTION INPUT ;
    USE SIGNAL ;
    PORT
      LAYER M4 ;
        RECT 820.608 136.512 820.800 136.536 ;
    END
  END tap[86]
  PIN tap[87]
    DIRECTION INPUT ;
    USE SIGNAL ;
    PORT
      LAYER M4 ;
        RECT 820.608 136.704 820.800 136.728 ;
    END
  END tap[87]
  PIN tap[88]
    DIRECTION INPUT ;
    USE SIGNAL ;
    PORT
      LAYER M4 ;
        RECT 820.608 136.896 820.800 136.920 ;
    END
  END tap[88]
  PIN tap[89]
    DIRECTION INPUT ;
    USE SIGNAL ;
    PORT
      LAYER M4 ;
        RECT 820.608 137.088 820.800 137.112 ;
    END
  END tap[89]
  PIN tap[90]
    DIRECTION INPUT ;
    USE SIGNAL ;
    PORT
      LAYER M4 ;
        RECT 820.608 137.280 820.800 137.304 ;
    END
  END tap[90]
  PIN tap[91]
    DIRECTION INPUT ;
    USE SIGNAL ;
    PORT
      LAYER M4 ;
        RECT 820.608 137.472 820.800 137.496 ;
    END
  END tap[91]
  PIN tap[92]
    DIRECTION INPUT ;
    USE SIGNAL ;
    PORT
      LAYER M4 ;
        RECT 820.608 137.664 820.800 137.688 ;
    END
  END tap[92]
  PIN tap[93]
    DIRECTION INPUT ;
    USE SIGNAL ;
    PORT
      LAYER M4 ;
        RECT 820.608 137.856 820.800 137.880 ;
    END
  END tap[93]
  PIN tap[94]
    DIRECTION INPUT ;
    USE SIGNAL ;
    PORT
      LAYER M4 ;
        RECT 820.608 138.048 820.800 138.072 ;
    END
  END tap[94]
  PIN tap[95]
    DIRECTION INPUT ;
    USE SIGNAL ;
    PORT
      LAYER M4 ;
        RECT 820.608 138.240 820.800 138.264 ;
    END
  END tap[95]
  PIN tap[96]
    DIRECTION INPUT ;
    USE SIGNAL ;
    PORT
      LAYER M4 ;
        RECT 820.608 138.432 820.800 138.456 ;
    END
  END tap[96]
  PIN tap[97]
    DIRECTION INPUT ;
    USE SIGNAL ;
    PORT
      LAYER M4 ;
        RECT 820.608 138.624 820.800 138.648 ;
    END
  END tap[97]
  PIN tap[98]
    DIRECTION INPUT ;
    USE SIGNAL ;
    PORT
      LAYER M4 ;
        RECT 820.608 138.816 820.800 138.840 ;
    END
  END tap[98]
  PIN tap[99]
    DIRECTION INPUT ;
    USE SIGNAL ;
    PORT
      LAYER M4 ;
        RECT 820.608 139.008 820.800 139.032 ;
    END
  END tap[99]
  PIN tap[100]
    DIRECTION INPUT ;
    USE SIGNAL ;
    PORT
      LAYER M4 ;
        RECT 820.608 139.200 820.800 139.224 ;
    END
  END tap[100]
  PIN tap[101]
    DIRECTION INPUT ;
    USE SIGNAL ;
    PORT
      LAYER M4 ;
        RECT 820.608 139.392 820.800 139.416 ;
    END
  END tap[101]
  PIN tap[102]
    DIRECTION INPUT ;
    USE SIGNAL ;
    PORT
      LAYER M4 ;
        RECT 820.608 139.584 820.800 139.608 ;
    END
  END tap[102]
  PIN tap[103]
    DIRECTION INPUT ;
    USE SIGNAL ;
    PORT
      LAYER M4 ;
        RECT 820.608 139.776 820.800 139.800 ;
    END
  END tap[103]
  PIN tap[104]
    DIRECTION INPUT ;
    USE SIGNAL ;
    PORT
      LAYER M4 ;
        RECT 820.608 139.968 820.800 139.992 ;
    END
  END tap[104]
  PIN tap[105]
    DIRECTION INPUT ;
    USE SIGNAL ;
    PORT
      LAYER M4 ;
        RECT 820.608 140.160 820.800 140.184 ;
    END
  END tap[105]
  PIN tap[106]
    DIRECTION INPUT ;
    USE SIGNAL ;
    PORT
      LAYER M4 ;
        RECT 820.608 140.352 820.800 140.376 ;
    END
  END tap[106]
  PIN tap[107]
    DIRECTION INPUT ;
    USE SIGNAL ;
    PORT
      LAYER M4 ;
        RECT 820.608 140.544 820.800 140.568 ;
    END
  END tap[107]
  PIN tap[108]
    DIRECTION INPUT ;
    USE SIGNAL ;
    PORT
      LAYER M4 ;
        RECT 820.608 140.736 820.800 140.760 ;
    END
  END tap[108]
  PIN tap[109]
    DIRECTION INPUT ;
    USE SIGNAL ;
    PORT
      LAYER M4 ;
        RECT 820.608 140.928 820.800 140.952 ;
    END
  END tap[109]
  PIN tap[110]
    DIRECTION INPUT ;
    USE SIGNAL ;
    PORT
      LAYER M4 ;
        RECT 820.608 141.120 820.800 141.144 ;
    END
  END tap[110]
  PIN tap[111]
    DIRECTION INPUT ;
    USE SIGNAL ;
    PORT
      LAYER M4 ;
        RECT 820.608 141.312 820.800 141.336 ;
    END
  END tap[111]
  PIN tap[112]
    DIRECTION INPUT ;
    USE SIGNAL ;
    PORT
      LAYER M4 ;
        RECT 820.608 141.504 820.800 141.528 ;
    END
  END tap[112]
  PIN tap[113]
    DIRECTION INPUT ;
    USE SIGNAL ;
    PORT
      LAYER M4 ;
        RECT 820.608 141.696 820.800 141.720 ;
    END
  END tap[113]
  PIN tap[114]
    DIRECTION INPUT ;
    USE SIGNAL ;
    PORT
      LAYER M4 ;
        RECT 820.608 141.888 820.800 141.912 ;
    END
  END tap[114]
  PIN tap[115]
    DIRECTION INPUT ;
    USE SIGNAL ;
    PORT
      LAYER M4 ;
        RECT 820.608 142.080 820.800 142.104 ;
    END
  END tap[115]
  PIN tap[116]
    DIRECTION INPUT ;
    USE SIGNAL ;
    PORT
      LAYER M4 ;
        RECT 820.608 142.272 820.800 142.296 ;
    END
  END tap[116]
  PIN tap[117]
    DIRECTION INPUT ;
    USE SIGNAL ;
    PORT
      LAYER M4 ;
        RECT 820.608 142.464 820.800 142.488 ;
    END
  END tap[117]
  PIN tap[118]
    DIRECTION INPUT ;
    USE SIGNAL ;
    PORT
      LAYER M4 ;
        RECT 820.608 142.656 820.800 142.680 ;
    END
  END tap[118]
  PIN tap[119]
    DIRECTION INPUT ;
    USE SIGNAL ;
    PORT
      LAYER M4 ;
        RECT 820.608 142.848 820.800 142.872 ;
    END
  END tap[119]
  PIN tap[120]
    DIRECTION INPUT ;
    USE SIGNAL ;
    PORT
      LAYER M4 ;
        RECT 820.608 143.040 820.800 143.064 ;
    END
  END tap[120]
  PIN tap[121]
    DIRECTION INPUT ;
    USE SIGNAL ;
    PORT
      LAYER M4 ;
        RECT 820.608 143.232 820.800 143.256 ;
    END
  END tap[121]
  PIN tap[122]
    DIRECTION INPUT ;
    USE SIGNAL ;
    PORT
      LAYER M4 ;
        RECT 820.608 143.424 820.800 143.448 ;
    END
  END tap[122]
  PIN tap[123]
    DIRECTION INPUT ;
    USE SIGNAL ;
    PORT
      LAYER M4 ;
        RECT 820.608 143.616 820.800 143.640 ;
    END
  END tap[123]
  PIN tap[124]
    DIRECTION INPUT ;
    USE SIGNAL ;
    PORT
      LAYER M4 ;
        RECT 820.608 143.808 820.800 143.832 ;
    END
  END tap[124]
  PIN tap[125]
    DIRECTION INPUT ;
    USE SIGNAL ;
    PORT
      LAYER M4 ;
        RECT 820.608 144.000 820.800 144.024 ;
    END
  END tap[125]
  PIN tap[126]
    DIRECTION INPUT ;
    USE SIGNAL ;
    PORT
      LAYER M4 ;
        RECT 820.608 144.192 820.800 144.216 ;
    END
  END tap[126]
  PIN tap[127]
    DIRECTION INPUT ;
    USE SIGNAL ;
    PORT
      LAYER M4 ;
        RECT 820.608 144.384 820.800 144.408 ;
    END
  END tap[127]
  PIN tap[128]
    DIRECTION INPUT ;
    USE SIGNAL ;
    PORT
      LAYER M4 ;
        RECT 820.608 144.576 820.800 144.600 ;
    END
  END tap[128]
  PIN tap[129]
    DIRECTION INPUT ;
    USE SIGNAL ;
    PORT
      LAYER M4 ;
        RECT 820.608 144.768 820.800 144.792 ;
    END
  END tap[129]
  PIN tap[130]
    DIRECTION INPUT ;
    USE SIGNAL ;
    PORT
      LAYER M4 ;
        RECT 820.608 144.960 820.800 144.984 ;
    END
  END tap[130]
  PIN tap[131]
    DIRECTION INPUT ;
    USE SIGNAL ;
    PORT
      LAYER M4 ;
        RECT 820.608 145.152 820.800 145.176 ;
    END
  END tap[131]
  PIN tap[132]
    DIRECTION INPUT ;
    USE SIGNAL ;
    PORT
      LAYER M4 ;
        RECT 820.608 145.344 820.800 145.368 ;
    END
  END tap[132]
  PIN tap[133]
    DIRECTION INPUT ;
    USE SIGNAL ;
    PORT
      LAYER M4 ;
        RECT 820.608 145.536 820.800 145.560 ;
    END
  END tap[133]
  PIN tap[134]
    DIRECTION INPUT ;
    USE SIGNAL ;
    PORT
      LAYER M4 ;
        RECT 820.608 145.728 820.800 145.752 ;
    END
  END tap[134]
  PIN tap[135]
    DIRECTION INPUT ;
    USE SIGNAL ;
    PORT
      LAYER M4 ;
        RECT 820.608 145.920 820.800 145.944 ;
    END
  END tap[135]
  PIN tap[136]
    DIRECTION INPUT ;
    USE SIGNAL ;
    PORT
      LAYER M4 ;
        RECT 820.608 146.112 820.800 146.136 ;
    END
  END tap[136]
  PIN tap[137]
    DIRECTION INPUT ;
    USE SIGNAL ;
    PORT
      LAYER M4 ;
        RECT 820.608 146.304 820.800 146.328 ;
    END
  END tap[137]
  PIN tap[138]
    DIRECTION INPUT ;
    USE SIGNAL ;
    PORT
      LAYER M4 ;
        RECT 820.608 146.496 820.800 146.520 ;
    END
  END tap[138]
  PIN tap[139]
    DIRECTION INPUT ;
    USE SIGNAL ;
    PORT
      LAYER M4 ;
        RECT 820.608 146.688 820.800 146.712 ;
    END
  END tap[139]
  PIN tap[140]
    DIRECTION INPUT ;
    USE SIGNAL ;
    PORT
      LAYER M4 ;
        RECT 820.608 146.880 820.800 146.904 ;
    END
  END tap[140]
  PIN tap[141]
    DIRECTION INPUT ;
    USE SIGNAL ;
    PORT
      LAYER M4 ;
        RECT 820.608 147.072 820.800 147.096 ;
    END
  END tap[141]
  PIN tap[142]
    DIRECTION INPUT ;
    USE SIGNAL ;
    PORT
      LAYER M4 ;
        RECT 820.608 147.264 820.800 147.288 ;
    END
  END tap[142]
  PIN tap[143]
    DIRECTION INPUT ;
    USE SIGNAL ;
    PORT
      LAYER M4 ;
        RECT 820.608 147.456 820.800 147.480 ;
    END
  END tap[143]
  PIN tap[144]
    DIRECTION INPUT ;
    USE SIGNAL ;
    PORT
      LAYER M4 ;
        RECT 820.608 147.648 820.800 147.672 ;
    END
  END tap[144]
  PIN tap[145]
    DIRECTION INPUT ;
    USE SIGNAL ;
    PORT
      LAYER M4 ;
        RECT 820.608 147.840 820.800 147.864 ;
    END
  END tap[145]
  PIN tap[146]
    DIRECTION INPUT ;
    USE SIGNAL ;
    PORT
      LAYER M4 ;
        RECT 820.608 148.032 820.800 148.056 ;
    END
  END tap[146]
  PIN tap[147]
    DIRECTION INPUT ;
    USE SIGNAL ;
    PORT
      LAYER M4 ;
        RECT 820.608 148.224 820.800 148.248 ;
    END
  END tap[147]
  PIN tap[148]
    DIRECTION INPUT ;
    USE SIGNAL ;
    PORT
      LAYER M4 ;
        RECT 820.608 148.416 820.800 148.440 ;
    END
  END tap[148]
  PIN tap[149]
    DIRECTION INPUT ;
    USE SIGNAL ;
    PORT
      LAYER M4 ;
        RECT 820.608 148.608 820.800 148.632 ;
    END
  END tap[149]
  PIN tap[150]
    DIRECTION INPUT ;
    USE SIGNAL ;
    PORT
      LAYER M4 ;
        RECT 820.608 148.800 820.800 148.824 ;
    END
  END tap[150]
  PIN tap[151]
    DIRECTION INPUT ;
    USE SIGNAL ;
    PORT
      LAYER M4 ;
        RECT 820.608 148.992 820.800 149.016 ;
    END
  END tap[151]
  PIN tap[152]
    DIRECTION INPUT ;
    USE SIGNAL ;
    PORT
      LAYER M4 ;
        RECT 820.608 149.184 820.800 149.208 ;
    END
  END tap[152]
  PIN tap[153]
    DIRECTION INPUT ;
    USE SIGNAL ;
    PORT
      LAYER M4 ;
        RECT 820.608 149.376 820.800 149.400 ;
    END
  END tap[153]
  PIN tap[154]
    DIRECTION INPUT ;
    USE SIGNAL ;
    PORT
      LAYER M4 ;
        RECT 820.608 149.568 820.800 149.592 ;
    END
  END tap[154]
  PIN tap[155]
    DIRECTION INPUT ;
    USE SIGNAL ;
    PORT
      LAYER M4 ;
        RECT 820.608 149.760 820.800 149.784 ;
    END
  END tap[155]
  PIN tap[156]
    DIRECTION INPUT ;
    USE SIGNAL ;
    PORT
      LAYER M4 ;
        RECT 820.608 149.952 820.800 149.976 ;
    END
  END tap[156]
  PIN tap[157]
    DIRECTION INPUT ;
    USE SIGNAL ;
    PORT
      LAYER M4 ;
        RECT 820.608 150.144 820.800 150.168 ;
    END
  END tap[157]
  PIN tap[158]
    DIRECTION INPUT ;
    USE SIGNAL ;
    PORT
      LAYER M4 ;
        RECT 820.608 150.336 820.800 150.360 ;
    END
  END tap[158]
  PIN tap[159]
    DIRECTION INPUT ;
    USE SIGNAL ;
    PORT
      LAYER M4 ;
        RECT 820.608 150.528 820.800 150.552 ;
    END
  END tap[159]
  PIN tap[160]
    DIRECTION INPUT ;
    USE SIGNAL ;
    PORT
      LAYER M4 ;
        RECT 820.608 150.720 820.800 150.744 ;
    END
  END tap[160]
  PIN tap[161]
    DIRECTION INPUT ;
    USE SIGNAL ;
    PORT
      LAYER M4 ;
        RECT 820.608 150.912 820.800 150.936 ;
    END
  END tap[161]
  PIN tap[162]
    DIRECTION INPUT ;
    USE SIGNAL ;
    PORT
      LAYER M4 ;
        RECT 820.608 151.104 820.800 151.128 ;
    END
  END tap[162]
  PIN tap[163]
    DIRECTION INPUT ;
    USE SIGNAL ;
    PORT
      LAYER M4 ;
        RECT 820.608 151.296 820.800 151.320 ;
    END
  END tap[163]
  PIN tap[164]
    DIRECTION INPUT ;
    USE SIGNAL ;
    PORT
      LAYER M4 ;
        RECT 820.608 151.488 820.800 151.512 ;
    END
  END tap[164]
  PIN tap[165]
    DIRECTION INPUT ;
    USE SIGNAL ;
    PORT
      LAYER M4 ;
        RECT 820.608 151.680 820.800 151.704 ;
    END
  END tap[165]
  PIN tap[166]
    DIRECTION INPUT ;
    USE SIGNAL ;
    PORT
      LAYER M4 ;
        RECT 820.608 151.872 820.800 151.896 ;
    END
  END tap[166]
  PIN tap[167]
    DIRECTION INPUT ;
    USE SIGNAL ;
    PORT
      LAYER M4 ;
        RECT 820.608 152.064 820.800 152.088 ;
    END
  END tap[167]
  PIN tap[168]
    DIRECTION INPUT ;
    USE SIGNAL ;
    PORT
      LAYER M4 ;
        RECT 820.608 152.256 820.800 152.280 ;
    END
  END tap[168]
  PIN tap[169]
    DIRECTION INPUT ;
    USE SIGNAL ;
    PORT
      LAYER M4 ;
        RECT 820.608 152.448 820.800 152.472 ;
    END
  END tap[169]
  PIN tap[170]
    DIRECTION INPUT ;
    USE SIGNAL ;
    PORT
      LAYER M4 ;
        RECT 820.608 152.640 820.800 152.664 ;
    END
  END tap[170]
  PIN tap[171]
    DIRECTION INPUT ;
    USE SIGNAL ;
    PORT
      LAYER M4 ;
        RECT 820.608 152.832 820.800 152.856 ;
    END
  END tap[171]
  PIN tap[172]
    DIRECTION INPUT ;
    USE SIGNAL ;
    PORT
      LAYER M4 ;
        RECT 820.608 153.024 820.800 153.048 ;
    END
  END tap[172]
  PIN tap[173]
    DIRECTION INPUT ;
    USE SIGNAL ;
    PORT
      LAYER M4 ;
        RECT 820.608 153.216 820.800 153.240 ;
    END
  END tap[173]
  PIN tap[174]
    DIRECTION INPUT ;
    USE SIGNAL ;
    PORT
      LAYER M4 ;
        RECT 820.608 153.408 820.800 153.432 ;
    END
  END tap[174]
  PIN tap[175]
    DIRECTION INPUT ;
    USE SIGNAL ;
    PORT
      LAYER M4 ;
        RECT 820.608 153.600 820.800 153.624 ;
    END
  END tap[175]
  PIN tap[176]
    DIRECTION INPUT ;
    USE SIGNAL ;
    PORT
      LAYER M4 ;
        RECT 820.608 153.792 820.800 153.816 ;
    END
  END tap[176]
  PIN tap[177]
    DIRECTION INPUT ;
    USE SIGNAL ;
    PORT
      LAYER M4 ;
        RECT 820.608 153.984 820.800 154.008 ;
    END
  END tap[177]
  PIN tap[178]
    DIRECTION INPUT ;
    USE SIGNAL ;
    PORT
      LAYER M4 ;
        RECT 820.608 154.176 820.800 154.200 ;
    END
  END tap[178]
  PIN tap[179]
    DIRECTION INPUT ;
    USE SIGNAL ;
    PORT
      LAYER M4 ;
        RECT 820.608 154.368 820.800 154.392 ;
    END
  END tap[179]
  PIN tap[180]
    DIRECTION INPUT ;
    USE SIGNAL ;
    PORT
      LAYER M4 ;
        RECT 820.608 154.560 820.800 154.584 ;
    END
  END tap[180]
  PIN tap[181]
    DIRECTION INPUT ;
    USE SIGNAL ;
    PORT
      LAYER M4 ;
        RECT 820.608 154.752 820.800 154.776 ;
    END
  END tap[181]
  PIN tap[182]
    DIRECTION INPUT ;
    USE SIGNAL ;
    PORT
      LAYER M4 ;
        RECT 820.608 154.944 820.800 154.968 ;
    END
  END tap[182]
  PIN tap[183]
    DIRECTION INPUT ;
    USE SIGNAL ;
    PORT
      LAYER M4 ;
        RECT 820.608 155.136 820.800 155.160 ;
    END
  END tap[183]
  PIN tap[184]
    DIRECTION INPUT ;
    USE SIGNAL ;
    PORT
      LAYER M4 ;
        RECT 820.608 155.328 820.800 155.352 ;
    END
  END tap[184]
  PIN tap[185]
    DIRECTION INPUT ;
    USE SIGNAL ;
    PORT
      LAYER M4 ;
        RECT 820.608 155.520 820.800 155.544 ;
    END
  END tap[185]
  PIN tap[186]
    DIRECTION INPUT ;
    USE SIGNAL ;
    PORT
      LAYER M4 ;
        RECT 820.608 155.712 820.800 155.736 ;
    END
  END tap[186]
  PIN tap[187]
    DIRECTION INPUT ;
    USE SIGNAL ;
    PORT
      LAYER M4 ;
        RECT 820.608 155.904 820.800 155.928 ;
    END
  END tap[187]
  PIN tap[188]
    DIRECTION INPUT ;
    USE SIGNAL ;
    PORT
      LAYER M4 ;
        RECT 820.608 156.096 820.800 156.120 ;
    END
  END tap[188]
  PIN tap[189]
    DIRECTION INPUT ;
    USE SIGNAL ;
    PORT
      LAYER M4 ;
        RECT 820.608 156.288 820.800 156.312 ;
    END
  END tap[189]
  PIN tap[190]
    DIRECTION INPUT ;
    USE SIGNAL ;
    PORT
      LAYER M4 ;
        RECT 820.608 156.480 820.800 156.504 ;
    END
  END tap[190]
  PIN tap[191]
    DIRECTION INPUT ;
    USE SIGNAL ;
    PORT
      LAYER M4 ;
        RECT 820.608 156.672 820.800 156.696 ;
    END
  END tap[191]
  PIN tap[192]
    DIRECTION INPUT ;
    USE SIGNAL ;
    PORT
      LAYER M4 ;
        RECT 820.608 156.864 820.800 156.888 ;
    END
  END tap[192]
  PIN tap[193]
    DIRECTION INPUT ;
    USE SIGNAL ;
    PORT
      LAYER M4 ;
        RECT 820.608 157.056 820.800 157.080 ;
    END
  END tap[193]
  PIN tap[194]
    DIRECTION INPUT ;
    USE SIGNAL ;
    PORT
      LAYER M4 ;
        RECT 820.608 157.248 820.800 157.272 ;
    END
  END tap[194]
  PIN tap[195]
    DIRECTION INPUT ;
    USE SIGNAL ;
    PORT
      LAYER M4 ;
        RECT 820.608 157.440 820.800 157.464 ;
    END
  END tap[195]
  PIN tap[196]
    DIRECTION INPUT ;
    USE SIGNAL ;
    PORT
      LAYER M4 ;
        RECT 820.608 157.632 820.800 157.656 ;
    END
  END tap[196]
  PIN tap[197]
    DIRECTION INPUT ;
    USE SIGNAL ;
    PORT
      LAYER M4 ;
        RECT 820.608 157.824 820.800 157.848 ;
    END
  END tap[197]
  PIN tap[198]
    DIRECTION INPUT ;
    USE SIGNAL ;
    PORT
      LAYER M4 ;
        RECT 820.608 158.016 820.800 158.040 ;
    END
  END tap[198]
  PIN tap[199]
    DIRECTION INPUT ;
    USE SIGNAL ;
    PORT
      LAYER M4 ;
        RECT 820.608 158.208 820.800 158.232 ;
    END
  END tap[199]
  PIN tap[200]
    DIRECTION INPUT ;
    USE SIGNAL ;
    PORT
      LAYER M4 ;
        RECT 820.608 158.400 820.800 158.424 ;
    END
  END tap[200]
  PIN tap[201]
    DIRECTION INPUT ;
    USE SIGNAL ;
    PORT
      LAYER M4 ;
        RECT 820.608 158.592 820.800 158.616 ;
    END
  END tap[201]
  PIN tap[202]
    DIRECTION INPUT ;
    USE SIGNAL ;
    PORT
      LAYER M4 ;
        RECT 820.608 158.784 820.800 158.808 ;
    END
  END tap[202]
  PIN tap[203]
    DIRECTION INPUT ;
    USE SIGNAL ;
    PORT
      LAYER M4 ;
        RECT 820.608 158.976 820.800 159.000 ;
    END
  END tap[203]
  PIN tap[204]
    DIRECTION INPUT ;
    USE SIGNAL ;
    PORT
      LAYER M4 ;
        RECT 820.608 159.168 820.800 159.192 ;
    END
  END tap[204]
  PIN tap[205]
    DIRECTION INPUT ;
    USE SIGNAL ;
    PORT
      LAYER M4 ;
        RECT 820.608 159.360 820.800 159.384 ;
    END
  END tap[205]
  PIN tap[206]
    DIRECTION INPUT ;
    USE SIGNAL ;
    PORT
      LAYER M4 ;
        RECT 820.608 159.552 820.800 159.576 ;
    END
  END tap[206]
  PIN tap[207]
    DIRECTION INPUT ;
    USE SIGNAL ;
    PORT
      LAYER M4 ;
        RECT 820.608 159.744 820.800 159.768 ;
    END
  END tap[207]
  PIN tap[208]
    DIRECTION INPUT ;
    USE SIGNAL ;
    PORT
      LAYER M4 ;
        RECT 820.608 159.936 820.800 159.960 ;
    END
  END tap[208]
  PIN tap[209]
    DIRECTION INPUT ;
    USE SIGNAL ;
    PORT
      LAYER M4 ;
        RECT 820.608 160.128 820.800 160.152 ;
    END
  END tap[209]
  PIN tap[210]
    DIRECTION INPUT ;
    USE SIGNAL ;
    PORT
      LAYER M4 ;
        RECT 820.608 160.320 820.800 160.344 ;
    END
  END tap[210]
  PIN tap[211]
    DIRECTION INPUT ;
    USE SIGNAL ;
    PORT
      LAYER M4 ;
        RECT 820.608 160.512 820.800 160.536 ;
    END
  END tap[211]
  PIN tap[212]
    DIRECTION INPUT ;
    USE SIGNAL ;
    PORT
      LAYER M4 ;
        RECT 820.608 160.704 820.800 160.728 ;
    END
  END tap[212]
  PIN tap[213]
    DIRECTION INPUT ;
    USE SIGNAL ;
    PORT
      LAYER M4 ;
        RECT 820.608 160.896 820.800 160.920 ;
    END
  END tap[213]
  PIN tap[214]
    DIRECTION INPUT ;
    USE SIGNAL ;
    PORT
      LAYER M4 ;
        RECT 820.608 161.088 820.800 161.112 ;
    END
  END tap[214]
  PIN tap[215]
    DIRECTION INPUT ;
    USE SIGNAL ;
    PORT
      LAYER M4 ;
        RECT 820.608 161.280 820.800 161.304 ;
    END
  END tap[215]
  PIN tap[216]
    DIRECTION INPUT ;
    USE SIGNAL ;
    PORT
      LAYER M4 ;
        RECT 820.608 161.472 820.800 161.496 ;
    END
  END tap[216]
  PIN tap[217]
    DIRECTION INPUT ;
    USE SIGNAL ;
    PORT
      LAYER M4 ;
        RECT 820.608 161.664 820.800 161.688 ;
    END
  END tap[217]
  PIN tap[218]
    DIRECTION INPUT ;
    USE SIGNAL ;
    PORT
      LAYER M4 ;
        RECT 820.608 161.856 820.800 161.880 ;
    END
  END tap[218]
  PIN tap[219]
    DIRECTION INPUT ;
    USE SIGNAL ;
    PORT
      LAYER M4 ;
        RECT 820.608 162.048 820.800 162.072 ;
    END
  END tap[219]
  PIN tap[220]
    DIRECTION INPUT ;
    USE SIGNAL ;
    PORT
      LAYER M4 ;
        RECT 820.608 162.240 820.800 162.264 ;
    END
  END tap[220]
  PIN tap[221]
    DIRECTION INPUT ;
    USE SIGNAL ;
    PORT
      LAYER M4 ;
        RECT 820.608 162.432 820.800 162.456 ;
    END
  END tap[221]
  PIN tap[222]
    DIRECTION INPUT ;
    USE SIGNAL ;
    PORT
      LAYER M4 ;
        RECT 820.608 162.624 820.800 162.648 ;
    END
  END tap[222]
  PIN tap[223]
    DIRECTION INPUT ;
    USE SIGNAL ;
    PORT
      LAYER M4 ;
        RECT 820.608 162.816 820.800 162.840 ;
    END
  END tap[223]
  PIN tap[224]
    DIRECTION INPUT ;
    USE SIGNAL ;
    PORT
      LAYER M4 ;
        RECT 820.608 163.008 820.800 163.032 ;
    END
  END tap[224]
  PIN tap[225]
    DIRECTION INPUT ;
    USE SIGNAL ;
    PORT
      LAYER M4 ;
        RECT 820.608 163.200 820.800 163.224 ;
    END
  END tap[225]
  PIN tap[226]
    DIRECTION INPUT ;
    USE SIGNAL ;
    PORT
      LAYER M4 ;
        RECT 820.608 163.392 820.800 163.416 ;
    END
  END tap[226]
  PIN tap[227]
    DIRECTION INPUT ;
    USE SIGNAL ;
    PORT
      LAYER M4 ;
        RECT 820.608 163.584 820.800 163.608 ;
    END
  END tap[227]
  PIN tap[228]
    DIRECTION INPUT ;
    USE SIGNAL ;
    PORT
      LAYER M4 ;
        RECT 820.608 163.776 820.800 163.800 ;
    END
  END tap[228]
  PIN tap[229]
    DIRECTION INPUT ;
    USE SIGNAL ;
    PORT
      LAYER M4 ;
        RECT 820.608 163.968 820.800 163.992 ;
    END
  END tap[229]
  PIN tap[230]
    DIRECTION INPUT ;
    USE SIGNAL ;
    PORT
      LAYER M4 ;
        RECT 820.608 164.160 820.800 164.184 ;
    END
  END tap[230]
  PIN tap[231]
    DIRECTION INPUT ;
    USE SIGNAL ;
    PORT
      LAYER M4 ;
        RECT 820.608 164.352 820.800 164.376 ;
    END
  END tap[231]
  PIN tap[232]
    DIRECTION INPUT ;
    USE SIGNAL ;
    PORT
      LAYER M4 ;
        RECT 820.608 164.544 820.800 164.568 ;
    END
  END tap[232]
  PIN tap[233]
    DIRECTION INPUT ;
    USE SIGNAL ;
    PORT
      LAYER M4 ;
        RECT 820.608 164.736 820.800 164.760 ;
    END
  END tap[233]
  PIN tap[234]
    DIRECTION INPUT ;
    USE SIGNAL ;
    PORT
      LAYER M4 ;
        RECT 820.608 164.928 820.800 164.952 ;
    END
  END tap[234]
  PIN tap[235]
    DIRECTION INPUT ;
    USE SIGNAL ;
    PORT
      LAYER M4 ;
        RECT 820.608 165.120 820.800 165.144 ;
    END
  END tap[235]
  PIN tap[236]
    DIRECTION INPUT ;
    USE SIGNAL ;
    PORT
      LAYER M4 ;
        RECT 820.608 165.312 820.800 165.336 ;
    END
  END tap[236]
  PIN tap[237]
    DIRECTION INPUT ;
    USE SIGNAL ;
    PORT
      LAYER M4 ;
        RECT 820.608 165.504 820.800 165.528 ;
    END
  END tap[237]
  PIN tap[238]
    DIRECTION INPUT ;
    USE SIGNAL ;
    PORT
      LAYER M4 ;
        RECT 820.608 165.696 820.800 165.720 ;
    END
  END tap[238]
  PIN tap[239]
    DIRECTION INPUT ;
    USE SIGNAL ;
    PORT
      LAYER M4 ;
        RECT 820.608 165.888 820.800 165.912 ;
    END
  END tap[239]
  PIN tap[240]
    DIRECTION INPUT ;
    USE SIGNAL ;
    PORT
      LAYER M4 ;
        RECT 820.608 166.080 820.800 166.104 ;
    END
  END tap[240]
  PIN tap[241]
    DIRECTION INPUT ;
    USE SIGNAL ;
    PORT
      LAYER M4 ;
        RECT 820.608 166.272 820.800 166.296 ;
    END
  END tap[241]
  PIN tap[242]
    DIRECTION INPUT ;
    USE SIGNAL ;
    PORT
      LAYER M4 ;
        RECT 820.608 166.464 820.800 166.488 ;
    END
  END tap[242]
  PIN tap[243]
    DIRECTION INPUT ;
    USE SIGNAL ;
    PORT
      LAYER M4 ;
        RECT 820.608 166.656 820.800 166.680 ;
    END
  END tap[243]
  PIN tap[244]
    DIRECTION INPUT ;
    USE SIGNAL ;
    PORT
      LAYER M4 ;
        RECT 820.608 166.848 820.800 166.872 ;
    END
  END tap[244]
  PIN tap[245]
    DIRECTION INPUT ;
    USE SIGNAL ;
    PORT
      LAYER M4 ;
        RECT 820.608 167.040 820.800 167.064 ;
    END
  END tap[245]
  PIN tap[246]
    DIRECTION INPUT ;
    USE SIGNAL ;
    PORT
      LAYER M4 ;
        RECT 820.608 167.232 820.800 167.256 ;
    END
  END tap[246]
  PIN tap[247]
    DIRECTION INPUT ;
    USE SIGNAL ;
    PORT
      LAYER M4 ;
        RECT 820.608 167.424 820.800 167.448 ;
    END
  END tap[247]
  PIN tap[248]
    DIRECTION INPUT ;
    USE SIGNAL ;
    PORT
      LAYER M4 ;
        RECT 820.608 167.616 820.800 167.640 ;
    END
  END tap[248]
  PIN tap[249]
    DIRECTION INPUT ;
    USE SIGNAL ;
    PORT
      LAYER M4 ;
        RECT 820.608 167.808 820.800 167.832 ;
    END
  END tap[249]
  PIN tap[250]
    DIRECTION INPUT ;
    USE SIGNAL ;
    PORT
      LAYER M4 ;
        RECT 820.608 168.000 820.800 168.024 ;
    END
  END tap[250]
  PIN tap[251]
    DIRECTION INPUT ;
    USE SIGNAL ;
    PORT
      LAYER M4 ;
        RECT 820.608 168.192 820.800 168.216 ;
    END
  END tap[251]
  PIN tap[252]
    DIRECTION INPUT ;
    USE SIGNAL ;
    PORT
      LAYER M4 ;
        RECT 820.608 168.384 820.800 168.408 ;
    END
  END tap[252]
  PIN tap[253]
    DIRECTION INPUT ;
    USE SIGNAL ;
    PORT
      LAYER M4 ;
        RECT 820.608 168.576 820.800 168.600 ;
    END
  END tap[253]
  PIN tap[254]
    DIRECTION INPUT ;
    USE SIGNAL ;
    PORT
      LAYER M4 ;
        RECT 820.608 168.768 820.800 168.792 ;
    END
  END tap[254]
  PIN tap[255]
    DIRECTION INPUT ;
    USE SIGNAL ;
    PORT
      LAYER M4 ;
        RECT 820.608 168.960 820.800 168.984 ;
    END
  END tap[255]
  PIN tap[256]
    DIRECTION INPUT ;
    USE SIGNAL ;
    PORT
      LAYER M4 ;
        RECT 820.608 169.152 820.800 169.176 ;
    END
  END tap[256]
  PIN tap[257]
    DIRECTION INPUT ;
    USE SIGNAL ;
    PORT
      LAYER M4 ;
        RECT 820.608 169.344 820.800 169.368 ;
    END
  END tap[257]
  PIN tap[258]
    DIRECTION INPUT ;
    USE SIGNAL ;
    PORT
      LAYER M4 ;
        RECT 820.608 169.536 820.800 169.560 ;
    END
  END tap[258]
  PIN tap[259]
    DIRECTION INPUT ;
    USE SIGNAL ;
    PORT
      LAYER M4 ;
        RECT 820.608 169.728 820.800 169.752 ;
    END
  END tap[259]
  PIN tap[260]
    DIRECTION INPUT ;
    USE SIGNAL ;
    PORT
      LAYER M4 ;
        RECT 820.608 169.920 820.800 169.944 ;
    END
  END tap[260]
  PIN tap[261]
    DIRECTION INPUT ;
    USE SIGNAL ;
    PORT
      LAYER M4 ;
        RECT 820.608 170.112 820.800 170.136 ;
    END
  END tap[261]
  PIN tap[262]
    DIRECTION INPUT ;
    USE SIGNAL ;
    PORT
      LAYER M4 ;
        RECT 820.608 170.304 820.800 170.328 ;
    END
  END tap[262]
  PIN tap[263]
    DIRECTION INPUT ;
    USE SIGNAL ;
    PORT
      LAYER M4 ;
        RECT 820.608 170.496 820.800 170.520 ;
    END
  END tap[263]
  PIN tap[264]
    DIRECTION INPUT ;
    USE SIGNAL ;
    PORT
      LAYER M4 ;
        RECT 820.608 170.688 820.800 170.712 ;
    END
  END tap[264]
  PIN tap[265]
    DIRECTION INPUT ;
    USE SIGNAL ;
    PORT
      LAYER M4 ;
        RECT 820.608 170.880 820.800 170.904 ;
    END
  END tap[265]
  PIN tap[266]
    DIRECTION INPUT ;
    USE SIGNAL ;
    PORT
      LAYER M4 ;
        RECT 820.608 171.072 820.800 171.096 ;
    END
  END tap[266]
  PIN tap[267]
    DIRECTION INPUT ;
    USE SIGNAL ;
    PORT
      LAYER M4 ;
        RECT 820.608 171.264 820.800 171.288 ;
    END
  END tap[267]
  PIN tap[268]
    DIRECTION INPUT ;
    USE SIGNAL ;
    PORT
      LAYER M4 ;
        RECT 820.608 171.456 820.800 171.480 ;
    END
  END tap[268]
  PIN tap[269]
    DIRECTION INPUT ;
    USE SIGNAL ;
    PORT
      LAYER M4 ;
        RECT 820.608 171.648 820.800 171.672 ;
    END
  END tap[269]
  PIN tap[270]
    DIRECTION INPUT ;
    USE SIGNAL ;
    PORT
      LAYER M4 ;
        RECT 820.608 171.840 820.800 171.864 ;
    END
  END tap[270]
  PIN tap[271]
    DIRECTION INPUT ;
    USE SIGNAL ;
    PORT
      LAYER M4 ;
        RECT 820.608 172.032 820.800 172.056 ;
    END
  END tap[271]
  PIN tap[272]
    DIRECTION INPUT ;
    USE SIGNAL ;
    PORT
      LAYER M4 ;
        RECT 820.608 172.224 820.800 172.248 ;
    END
  END tap[272]
  PIN tap[273]
    DIRECTION INPUT ;
    USE SIGNAL ;
    PORT
      LAYER M4 ;
        RECT 820.608 172.416 820.800 172.440 ;
    END
  END tap[273]
  PIN tap[274]
    DIRECTION INPUT ;
    USE SIGNAL ;
    PORT
      LAYER M4 ;
        RECT 820.608 172.608 820.800 172.632 ;
    END
  END tap[274]
  PIN tap[275]
    DIRECTION INPUT ;
    USE SIGNAL ;
    PORT
      LAYER M4 ;
        RECT 820.608 172.800 820.800 172.824 ;
    END
  END tap[275]
  PIN tap[276]
    DIRECTION INPUT ;
    USE SIGNAL ;
    PORT
      LAYER M4 ;
        RECT 820.608 172.992 820.800 173.016 ;
    END
  END tap[276]
  PIN tap[277]
    DIRECTION INPUT ;
    USE SIGNAL ;
    PORT
      LAYER M4 ;
        RECT 820.608 173.184 820.800 173.208 ;
    END
  END tap[277]
  PIN tap[278]
    DIRECTION INPUT ;
    USE SIGNAL ;
    PORT
      LAYER M4 ;
        RECT 820.608 173.376 820.800 173.400 ;
    END
  END tap[278]
  PIN tap[279]
    DIRECTION INPUT ;
    USE SIGNAL ;
    PORT
      LAYER M4 ;
        RECT 820.608 173.568 820.800 173.592 ;
    END
  END tap[279]
  PIN tap[280]
    DIRECTION INPUT ;
    USE SIGNAL ;
    PORT
      LAYER M4 ;
        RECT 820.608 173.760 820.800 173.784 ;
    END
  END tap[280]
  PIN tap[281]
    DIRECTION INPUT ;
    USE SIGNAL ;
    PORT
      LAYER M4 ;
        RECT 820.608 173.952 820.800 173.976 ;
    END
  END tap[281]
  PIN tap[282]
    DIRECTION INPUT ;
    USE SIGNAL ;
    PORT
      LAYER M4 ;
        RECT 820.608 174.144 820.800 174.168 ;
    END
  END tap[282]
  PIN tap[283]
    DIRECTION INPUT ;
    USE SIGNAL ;
    PORT
      LAYER M4 ;
        RECT 820.608 174.336 820.800 174.360 ;
    END
  END tap[283]
  PIN tap[284]
    DIRECTION INPUT ;
    USE SIGNAL ;
    PORT
      LAYER M4 ;
        RECT 820.608 174.528 820.800 174.552 ;
    END
  END tap[284]
  PIN tap[285]
    DIRECTION INPUT ;
    USE SIGNAL ;
    PORT
      LAYER M4 ;
        RECT 820.608 174.720 820.800 174.744 ;
    END
  END tap[285]
  PIN tap[286]
    DIRECTION INPUT ;
    USE SIGNAL ;
    PORT
      LAYER M4 ;
        RECT 820.608 174.912 820.800 174.936 ;
    END
  END tap[286]
  PIN tap[287]
    DIRECTION INPUT ;
    USE SIGNAL ;
    PORT
      LAYER M4 ;
        RECT 820.608 175.104 820.800 175.128 ;
    END
  END tap[287]
  PIN tap[288]
    DIRECTION INPUT ;
    USE SIGNAL ;
    PORT
      LAYER M4 ;
        RECT 820.608 175.296 820.800 175.320 ;
    END
  END tap[288]
  PIN tap[289]
    DIRECTION INPUT ;
    USE SIGNAL ;
    PORT
      LAYER M4 ;
        RECT 820.608 175.488 820.800 175.512 ;
    END
  END tap[289]
  PIN tap[290]
    DIRECTION INPUT ;
    USE SIGNAL ;
    PORT
      LAYER M4 ;
        RECT 820.608 175.680 820.800 175.704 ;
    END
  END tap[290]
  PIN tap[291]
    DIRECTION INPUT ;
    USE SIGNAL ;
    PORT
      LAYER M4 ;
        RECT 820.608 175.872 820.800 175.896 ;
    END
  END tap[291]
  PIN tap[292]
    DIRECTION INPUT ;
    USE SIGNAL ;
    PORT
      LAYER M4 ;
        RECT 820.608 176.064 820.800 176.088 ;
    END
  END tap[292]
  PIN tap[293]
    DIRECTION INPUT ;
    USE SIGNAL ;
    PORT
      LAYER M4 ;
        RECT 820.608 176.256 820.800 176.280 ;
    END
  END tap[293]
  PIN tap[294]
    DIRECTION INPUT ;
    USE SIGNAL ;
    PORT
      LAYER M4 ;
        RECT 820.608 176.448 820.800 176.472 ;
    END
  END tap[294]
  PIN tap[295]
    DIRECTION INPUT ;
    USE SIGNAL ;
    PORT
      LAYER M4 ;
        RECT 820.608 176.640 820.800 176.664 ;
    END
  END tap[295]
  PIN tap[296]
    DIRECTION INPUT ;
    USE SIGNAL ;
    PORT
      LAYER M4 ;
        RECT 820.608 176.832 820.800 176.856 ;
    END
  END tap[296]
  PIN tap[297]
    DIRECTION INPUT ;
    USE SIGNAL ;
    PORT
      LAYER M4 ;
        RECT 820.608 177.024 820.800 177.048 ;
    END
  END tap[297]
  PIN tap[298]
    DIRECTION INPUT ;
    USE SIGNAL ;
    PORT
      LAYER M4 ;
        RECT 820.608 177.216 820.800 177.240 ;
    END
  END tap[298]
  PIN tap[299]
    DIRECTION INPUT ;
    USE SIGNAL ;
    PORT
      LAYER M4 ;
        RECT 820.608 177.408 820.800 177.432 ;
    END
  END tap[299]
  PIN tap[300]
    DIRECTION INPUT ;
    USE SIGNAL ;
    PORT
      LAYER M4 ;
        RECT 820.608 177.600 820.800 177.624 ;
    END
  END tap[300]
  PIN tap[301]
    DIRECTION INPUT ;
    USE SIGNAL ;
    PORT
      LAYER M4 ;
        RECT 820.608 177.792 820.800 177.816 ;
    END
  END tap[301]
  PIN tap[302]
    DIRECTION INPUT ;
    USE SIGNAL ;
    PORT
      LAYER M4 ;
        RECT 820.608 177.984 820.800 178.008 ;
    END
  END tap[302]
  PIN tap[303]
    DIRECTION INPUT ;
    USE SIGNAL ;
    PORT
      LAYER M4 ;
        RECT 820.608 178.176 820.800 178.200 ;
    END
  END tap[303]
  PIN tap[304]
    DIRECTION INPUT ;
    USE SIGNAL ;
    PORT
      LAYER M4 ;
        RECT 820.608 178.368 820.800 178.392 ;
    END
  END tap[304]
  PIN tap[305]
    DIRECTION INPUT ;
    USE SIGNAL ;
    PORT
      LAYER M4 ;
        RECT 820.608 178.560 820.800 178.584 ;
    END
  END tap[305]
  PIN tap[306]
    DIRECTION INPUT ;
    USE SIGNAL ;
    PORT
      LAYER M4 ;
        RECT 820.608 178.752 820.800 178.776 ;
    END
  END tap[306]
  PIN tap[307]
    DIRECTION INPUT ;
    USE SIGNAL ;
    PORT
      LAYER M4 ;
        RECT 820.608 178.944 820.800 178.968 ;
    END
  END tap[307]
  PIN tap[308]
    DIRECTION INPUT ;
    USE SIGNAL ;
    PORT
      LAYER M4 ;
        RECT 820.608 179.136 820.800 179.160 ;
    END
  END tap[308]
  PIN tap[309]
    DIRECTION INPUT ;
    USE SIGNAL ;
    PORT
      LAYER M4 ;
        RECT 820.608 179.328 820.800 179.352 ;
    END
  END tap[309]
  PIN tap[310]
    DIRECTION INPUT ;
    USE SIGNAL ;
    PORT
      LAYER M4 ;
        RECT 820.608 179.520 820.800 179.544 ;
    END
  END tap[310]
  PIN tap[311]
    DIRECTION INPUT ;
    USE SIGNAL ;
    PORT
      LAYER M4 ;
        RECT 820.608 179.712 820.800 179.736 ;
    END
  END tap[311]
  PIN tap[312]
    DIRECTION INPUT ;
    USE SIGNAL ;
    PORT
      LAYER M4 ;
        RECT 820.608 179.904 820.800 179.928 ;
    END
  END tap[312]
  PIN tap[313]
    DIRECTION INPUT ;
    USE SIGNAL ;
    PORT
      LAYER M4 ;
        RECT 820.608 180.096 820.800 180.120 ;
    END
  END tap[313]
  PIN tap[314]
    DIRECTION INPUT ;
    USE SIGNAL ;
    PORT
      LAYER M4 ;
        RECT 820.608 180.288 820.800 180.312 ;
    END
  END tap[314]
  PIN tap[315]
    DIRECTION INPUT ;
    USE SIGNAL ;
    PORT
      LAYER M4 ;
        RECT 820.608 180.480 820.800 180.504 ;
    END
  END tap[315]
  PIN tap[316]
    DIRECTION INPUT ;
    USE SIGNAL ;
    PORT
      LAYER M4 ;
        RECT 820.608 180.672 820.800 180.696 ;
    END
  END tap[316]
  PIN tap[317]
    DIRECTION INPUT ;
    USE SIGNAL ;
    PORT
      LAYER M4 ;
        RECT 820.608 180.864 820.800 180.888 ;
    END
  END tap[317]
  PIN tap[318]
    DIRECTION INPUT ;
    USE SIGNAL ;
    PORT
      LAYER M4 ;
        RECT 820.608 181.056 820.800 181.080 ;
    END
  END tap[318]
  PIN tap[319]
    DIRECTION INPUT ;
    USE SIGNAL ;
    PORT
      LAYER M4 ;
        RECT 820.608 181.248 820.800 181.272 ;
    END
  END tap[319]
  PIN tap[320]
    DIRECTION INPUT ;
    USE SIGNAL ;
    PORT
      LAYER M4 ;
        RECT 820.608 181.440 820.800 181.464 ;
    END
  END tap[320]
  PIN tap[321]
    DIRECTION INPUT ;
    USE SIGNAL ;
    PORT
      LAYER M4 ;
        RECT 820.608 181.632 820.800 181.656 ;
    END
  END tap[321]
  PIN tap[322]
    DIRECTION INPUT ;
    USE SIGNAL ;
    PORT
      LAYER M4 ;
        RECT 820.608 181.824 820.800 181.848 ;
    END
  END tap[322]
  PIN tap[323]
    DIRECTION INPUT ;
    USE SIGNAL ;
    PORT
      LAYER M4 ;
        RECT 820.608 182.016 820.800 182.040 ;
    END
  END tap[323]
  PIN tap[324]
    DIRECTION INPUT ;
    USE SIGNAL ;
    PORT
      LAYER M4 ;
        RECT 820.608 182.208 820.800 182.232 ;
    END
  END tap[324]
  PIN tap[325]
    DIRECTION INPUT ;
    USE SIGNAL ;
    PORT
      LAYER M4 ;
        RECT 820.608 182.400 820.800 182.424 ;
    END
  END tap[325]
  PIN tap[326]
    DIRECTION INPUT ;
    USE SIGNAL ;
    PORT
      LAYER M4 ;
        RECT 820.608 182.592 820.800 182.616 ;
    END
  END tap[326]
  PIN tap[327]
    DIRECTION INPUT ;
    USE SIGNAL ;
    PORT
      LAYER M4 ;
        RECT 820.608 182.784 820.800 182.808 ;
    END
  END tap[327]
  PIN tap[328]
    DIRECTION INPUT ;
    USE SIGNAL ;
    PORT
      LAYER M4 ;
        RECT 820.608 182.976 820.800 183.000 ;
    END
  END tap[328]
  PIN tap[329]
    DIRECTION INPUT ;
    USE SIGNAL ;
    PORT
      LAYER M4 ;
        RECT 820.608 183.168 820.800 183.192 ;
    END
  END tap[329]
  PIN tap[330]
    DIRECTION INPUT ;
    USE SIGNAL ;
    PORT
      LAYER M4 ;
        RECT 820.608 183.360 820.800 183.384 ;
    END
  END tap[330]
  PIN tap[331]
    DIRECTION INPUT ;
    USE SIGNAL ;
    PORT
      LAYER M4 ;
        RECT 820.608 183.552 820.800 183.576 ;
    END
  END tap[331]
  PIN tap[332]
    DIRECTION INPUT ;
    USE SIGNAL ;
    PORT
      LAYER M4 ;
        RECT 820.608 183.744 820.800 183.768 ;
    END
  END tap[332]
  PIN tap[333]
    DIRECTION INPUT ;
    USE SIGNAL ;
    PORT
      LAYER M4 ;
        RECT 820.608 183.936 820.800 183.960 ;
    END
  END tap[333]
  PIN tap[334]
    DIRECTION INPUT ;
    USE SIGNAL ;
    PORT
      LAYER M4 ;
        RECT 820.608 184.128 820.800 184.152 ;
    END
  END tap[334]
  PIN tap[335]
    DIRECTION INPUT ;
    USE SIGNAL ;
    PORT
      LAYER M4 ;
        RECT 820.608 184.320 820.800 184.344 ;
    END
  END tap[335]
  PIN tap[336]
    DIRECTION INPUT ;
    USE SIGNAL ;
    PORT
      LAYER M4 ;
        RECT 820.608 184.512 820.800 184.536 ;
    END
  END tap[336]
  PIN tap[337]
    DIRECTION INPUT ;
    USE SIGNAL ;
    PORT
      LAYER M4 ;
        RECT 820.608 184.704 820.800 184.728 ;
    END
  END tap[337]
  PIN tap[338]
    DIRECTION INPUT ;
    USE SIGNAL ;
    PORT
      LAYER M4 ;
        RECT 820.608 184.896 820.800 184.920 ;
    END
  END tap[338]
  PIN tap[339]
    DIRECTION INPUT ;
    USE SIGNAL ;
    PORT
      LAYER M4 ;
        RECT 820.608 185.088 820.800 185.112 ;
    END
  END tap[339]
  PIN tap[340]
    DIRECTION INPUT ;
    USE SIGNAL ;
    PORT
      LAYER M4 ;
        RECT 820.608 185.280 820.800 185.304 ;
    END
  END tap[340]
  PIN tap[341]
    DIRECTION INPUT ;
    USE SIGNAL ;
    PORT
      LAYER M4 ;
        RECT 820.608 185.472 820.800 185.496 ;
    END
  END tap[341]
  PIN tap[342]
    DIRECTION INPUT ;
    USE SIGNAL ;
    PORT
      LAYER M4 ;
        RECT 820.608 185.664 820.800 185.688 ;
    END
  END tap[342]
  PIN tap[343]
    DIRECTION INPUT ;
    USE SIGNAL ;
    PORT
      LAYER M4 ;
        RECT 820.608 185.856 820.800 185.880 ;
    END
  END tap[343]
  PIN tap[344]
    DIRECTION INPUT ;
    USE SIGNAL ;
    PORT
      LAYER M4 ;
        RECT 820.608 186.048 820.800 186.072 ;
    END
  END tap[344]
  PIN tap[345]
    DIRECTION INPUT ;
    USE SIGNAL ;
    PORT
      LAYER M4 ;
        RECT 820.608 186.240 820.800 186.264 ;
    END
  END tap[345]
  PIN tap[346]
    DIRECTION INPUT ;
    USE SIGNAL ;
    PORT
      LAYER M4 ;
        RECT 820.608 186.432 820.800 186.456 ;
    END
  END tap[346]
  PIN tap[347]
    DIRECTION INPUT ;
    USE SIGNAL ;
    PORT
      LAYER M4 ;
        RECT 820.608 186.624 820.800 186.648 ;
    END
  END tap[347]
  PIN tap[348]
    DIRECTION INPUT ;
    USE SIGNAL ;
    PORT
      LAYER M4 ;
        RECT 820.608 186.816 820.800 186.840 ;
    END
  END tap[348]
  PIN tap[349]
    DIRECTION INPUT ;
    USE SIGNAL ;
    PORT
      LAYER M4 ;
        RECT 820.608 187.008 820.800 187.032 ;
    END
  END tap[349]
  PIN tap[350]
    DIRECTION INPUT ;
    USE SIGNAL ;
    PORT
      LAYER M4 ;
        RECT 820.608 187.200 820.800 187.224 ;
    END
  END tap[350]
  PIN tap[351]
    DIRECTION INPUT ;
    USE SIGNAL ;
    PORT
      LAYER M4 ;
        RECT 820.608 187.392 820.800 187.416 ;
    END
  END tap[351]
  PIN tap[352]
    DIRECTION INPUT ;
    USE SIGNAL ;
    PORT
      LAYER M4 ;
        RECT 820.608 187.584 820.800 187.608 ;
    END
  END tap[352]
  PIN tap[353]
    DIRECTION INPUT ;
    USE SIGNAL ;
    PORT
      LAYER M4 ;
        RECT 820.608 187.776 820.800 187.800 ;
    END
  END tap[353]
  PIN tap[354]
    DIRECTION INPUT ;
    USE SIGNAL ;
    PORT
      LAYER M4 ;
        RECT 820.608 187.968 820.800 187.992 ;
    END
  END tap[354]
  PIN tap[355]
    DIRECTION INPUT ;
    USE SIGNAL ;
    PORT
      LAYER M4 ;
        RECT 820.608 188.160 820.800 188.184 ;
    END
  END tap[355]
  PIN tap[356]
    DIRECTION INPUT ;
    USE SIGNAL ;
    PORT
      LAYER M4 ;
        RECT 820.608 188.352 820.800 188.376 ;
    END
  END tap[356]
  PIN tap[357]
    DIRECTION INPUT ;
    USE SIGNAL ;
    PORT
      LAYER M4 ;
        RECT 820.608 188.544 820.800 188.568 ;
    END
  END tap[357]
  PIN tap[358]
    DIRECTION INPUT ;
    USE SIGNAL ;
    PORT
      LAYER M4 ;
        RECT 820.608 188.736 820.800 188.760 ;
    END
  END tap[358]
  PIN tap[359]
    DIRECTION INPUT ;
    USE SIGNAL ;
    PORT
      LAYER M4 ;
        RECT 820.608 188.928 820.800 188.952 ;
    END
  END tap[359]
  PIN tap[360]
    DIRECTION INPUT ;
    USE SIGNAL ;
    PORT
      LAYER M4 ;
        RECT 820.608 189.120 820.800 189.144 ;
    END
  END tap[360]
  PIN tap[361]
    DIRECTION INPUT ;
    USE SIGNAL ;
    PORT
      LAYER M4 ;
        RECT 820.608 189.312 820.800 189.336 ;
    END
  END tap[361]
  PIN tap[362]
    DIRECTION INPUT ;
    USE SIGNAL ;
    PORT
      LAYER M4 ;
        RECT 820.608 189.504 820.800 189.528 ;
    END
  END tap[362]
  PIN tap[363]
    DIRECTION INPUT ;
    USE SIGNAL ;
    PORT
      LAYER M4 ;
        RECT 820.608 189.696 820.800 189.720 ;
    END
  END tap[363]
  PIN tap[364]
    DIRECTION INPUT ;
    USE SIGNAL ;
    PORT
      LAYER M4 ;
        RECT 820.608 189.888 820.800 189.912 ;
    END
  END tap[364]
  PIN tap[365]
    DIRECTION INPUT ;
    USE SIGNAL ;
    PORT
      LAYER M4 ;
        RECT 820.608 190.080 820.800 190.104 ;
    END
  END tap[365]
  PIN tap[366]
    DIRECTION INPUT ;
    USE SIGNAL ;
    PORT
      LAYER M4 ;
        RECT 820.608 190.272 820.800 190.296 ;
    END
  END tap[366]
  PIN tap[367]
    DIRECTION INPUT ;
    USE SIGNAL ;
    PORT
      LAYER M4 ;
        RECT 820.608 190.464 820.800 190.488 ;
    END
  END tap[367]
  PIN tap[368]
    DIRECTION INPUT ;
    USE SIGNAL ;
    PORT
      LAYER M4 ;
        RECT 820.608 190.656 820.800 190.680 ;
    END
  END tap[368]
  PIN tap[369]
    DIRECTION INPUT ;
    USE SIGNAL ;
    PORT
      LAYER M4 ;
        RECT 820.608 190.848 820.800 190.872 ;
    END
  END tap[369]
  PIN tap[370]
    DIRECTION INPUT ;
    USE SIGNAL ;
    PORT
      LAYER M4 ;
        RECT 820.608 191.040 820.800 191.064 ;
    END
  END tap[370]
  PIN tap[371]
    DIRECTION INPUT ;
    USE SIGNAL ;
    PORT
      LAYER M4 ;
        RECT 820.608 191.232 820.800 191.256 ;
    END
  END tap[371]
  PIN tap[372]
    DIRECTION INPUT ;
    USE SIGNAL ;
    PORT
      LAYER M4 ;
        RECT 820.608 191.424 820.800 191.448 ;
    END
  END tap[372]
  PIN tap[373]
    DIRECTION INPUT ;
    USE SIGNAL ;
    PORT
      LAYER M4 ;
        RECT 820.608 191.616 820.800 191.640 ;
    END
  END tap[373]
  PIN tap[374]
    DIRECTION INPUT ;
    USE SIGNAL ;
    PORT
      LAYER M4 ;
        RECT 820.608 191.808 820.800 191.832 ;
    END
  END tap[374]
  PIN tap[375]
    DIRECTION INPUT ;
    USE SIGNAL ;
    PORT
      LAYER M4 ;
        RECT 820.608 192.000 820.800 192.024 ;
    END
  END tap[375]
  PIN tap[376]
    DIRECTION INPUT ;
    USE SIGNAL ;
    PORT
      LAYER M4 ;
        RECT 820.608 192.192 820.800 192.216 ;
    END
  END tap[376]
  PIN tap[377]
    DIRECTION INPUT ;
    USE SIGNAL ;
    PORT
      LAYER M4 ;
        RECT 820.608 192.384 820.800 192.408 ;
    END
  END tap[377]
  PIN tap[378]
    DIRECTION INPUT ;
    USE SIGNAL ;
    PORT
      LAYER M4 ;
        RECT 820.608 192.576 820.800 192.600 ;
    END
  END tap[378]
  PIN tap[379]
    DIRECTION INPUT ;
    USE SIGNAL ;
    PORT
      LAYER M4 ;
        RECT 820.608 192.768 820.800 192.792 ;
    END
  END tap[379]
  PIN tap[380]
    DIRECTION INPUT ;
    USE SIGNAL ;
    PORT
      LAYER M4 ;
        RECT 820.608 192.960 820.800 192.984 ;
    END
  END tap[380]
  PIN tap[381]
    DIRECTION INPUT ;
    USE SIGNAL ;
    PORT
      LAYER M4 ;
        RECT 820.608 193.152 820.800 193.176 ;
    END
  END tap[381]
  PIN tap[382]
    DIRECTION INPUT ;
    USE SIGNAL ;
    PORT
      LAYER M4 ;
        RECT 820.608 193.344 820.800 193.368 ;
    END
  END tap[382]
  PIN tap[383]
    DIRECTION INPUT ;
    USE SIGNAL ;
    PORT
      LAYER M4 ;
        RECT 820.608 193.536 820.800 193.560 ;
    END
  END tap[383]
  PIN tap[384]
    DIRECTION INPUT ;
    USE SIGNAL ;
    PORT
      LAYER M4 ;
        RECT 820.608 193.728 820.800 193.752 ;
    END
  END tap[384]
  PIN tap[385]
    DIRECTION INPUT ;
    USE SIGNAL ;
    PORT
      LAYER M4 ;
        RECT 820.608 193.920 820.800 193.944 ;
    END
  END tap[385]
  PIN tap[386]
    DIRECTION INPUT ;
    USE SIGNAL ;
    PORT
      LAYER M4 ;
        RECT 820.608 194.112 820.800 194.136 ;
    END
  END tap[386]
  PIN tap[387]
    DIRECTION INPUT ;
    USE SIGNAL ;
    PORT
      LAYER M4 ;
        RECT 820.608 194.304 820.800 194.328 ;
    END
  END tap[387]
  PIN tap[388]
    DIRECTION INPUT ;
    USE SIGNAL ;
    PORT
      LAYER M4 ;
        RECT 820.608 194.496 820.800 194.520 ;
    END
  END tap[388]
  PIN tap[389]
    DIRECTION INPUT ;
    USE SIGNAL ;
    PORT
      LAYER M4 ;
        RECT 820.608 194.688 820.800 194.712 ;
    END
  END tap[389]
  PIN tap[390]
    DIRECTION INPUT ;
    USE SIGNAL ;
    PORT
      LAYER M4 ;
        RECT 820.608 194.880 820.800 194.904 ;
    END
  END tap[390]
  PIN tap[391]
    DIRECTION INPUT ;
    USE SIGNAL ;
    PORT
      LAYER M4 ;
        RECT 820.608 195.072 820.800 195.096 ;
    END
  END tap[391]
  PIN tap[392]
    DIRECTION INPUT ;
    USE SIGNAL ;
    PORT
      LAYER M4 ;
        RECT 820.608 195.264 820.800 195.288 ;
    END
  END tap[392]
  PIN tap[393]
    DIRECTION INPUT ;
    USE SIGNAL ;
    PORT
      LAYER M4 ;
        RECT 820.608 195.456 820.800 195.480 ;
    END
  END tap[393]
  PIN tap[394]
    DIRECTION INPUT ;
    USE SIGNAL ;
    PORT
      LAYER M4 ;
        RECT 820.608 195.648 820.800 195.672 ;
    END
  END tap[394]
  PIN tap[395]
    DIRECTION INPUT ;
    USE SIGNAL ;
    PORT
      LAYER M4 ;
        RECT 820.608 195.840 820.800 195.864 ;
    END
  END tap[395]
  PIN tap[396]
    DIRECTION INPUT ;
    USE SIGNAL ;
    PORT
      LAYER M4 ;
        RECT 820.608 196.032 820.800 196.056 ;
    END
  END tap[396]
  PIN tap[397]
    DIRECTION INPUT ;
    USE SIGNAL ;
    PORT
      LAYER M4 ;
        RECT 820.608 196.224 820.800 196.248 ;
    END
  END tap[397]
  PIN tap[398]
    DIRECTION INPUT ;
    USE SIGNAL ;
    PORT
      LAYER M4 ;
        RECT 820.608 196.416 820.800 196.440 ;
    END
  END tap[398]
  PIN tap[399]
    DIRECTION INPUT ;
    USE SIGNAL ;
    PORT
      LAYER M4 ;
        RECT 820.608 196.608 820.800 196.632 ;
    END
  END tap[399]
  PIN tap[400]
    DIRECTION INPUT ;
    USE SIGNAL ;
    PORT
      LAYER M4 ;
        RECT 820.608 196.800 820.800 196.824 ;
    END
  END tap[400]
  PIN tap[401]
    DIRECTION INPUT ;
    USE SIGNAL ;
    PORT
      LAYER M4 ;
        RECT 820.608 196.992 820.800 197.016 ;
    END
  END tap[401]
  PIN tap[402]
    DIRECTION INPUT ;
    USE SIGNAL ;
    PORT
      LAYER M4 ;
        RECT 820.608 197.184 820.800 197.208 ;
    END
  END tap[402]
  PIN tap[403]
    DIRECTION INPUT ;
    USE SIGNAL ;
    PORT
      LAYER M4 ;
        RECT 820.608 197.376 820.800 197.400 ;
    END
  END tap[403]
  PIN tap[404]
    DIRECTION INPUT ;
    USE SIGNAL ;
    PORT
      LAYER M4 ;
        RECT 820.608 197.568 820.800 197.592 ;
    END
  END tap[404]
  PIN tap[405]
    DIRECTION INPUT ;
    USE SIGNAL ;
    PORT
      LAYER M4 ;
        RECT 820.608 197.760 820.800 197.784 ;
    END
  END tap[405]
  PIN tap[406]
    DIRECTION INPUT ;
    USE SIGNAL ;
    PORT
      LAYER M4 ;
        RECT 820.608 197.952 820.800 197.976 ;
    END
  END tap[406]
  PIN tap[407]
    DIRECTION INPUT ;
    USE SIGNAL ;
    PORT
      LAYER M4 ;
        RECT 820.608 198.144 820.800 198.168 ;
    END
  END tap[407]
  PIN tap[408]
    DIRECTION INPUT ;
    USE SIGNAL ;
    PORT
      LAYER M4 ;
        RECT 820.608 198.336 820.800 198.360 ;
    END
  END tap[408]
  PIN tap[409]
    DIRECTION INPUT ;
    USE SIGNAL ;
    PORT
      LAYER M4 ;
        RECT 820.608 198.528 820.800 198.552 ;
    END
  END tap[409]
  PIN tap[410]
    DIRECTION INPUT ;
    USE SIGNAL ;
    PORT
      LAYER M4 ;
        RECT 820.608 198.720 820.800 198.744 ;
    END
  END tap[410]
  PIN tap[411]
    DIRECTION INPUT ;
    USE SIGNAL ;
    PORT
      LAYER M4 ;
        RECT 820.608 198.912 820.800 198.936 ;
    END
  END tap[411]
  PIN tap[412]
    DIRECTION INPUT ;
    USE SIGNAL ;
    PORT
      LAYER M4 ;
        RECT 820.608 199.104 820.800 199.128 ;
    END
  END tap[412]
  PIN tap[413]
    DIRECTION INPUT ;
    USE SIGNAL ;
    PORT
      LAYER M4 ;
        RECT 820.608 199.296 820.800 199.320 ;
    END
  END tap[413]
  PIN tap[414]
    DIRECTION INPUT ;
    USE SIGNAL ;
    PORT
      LAYER M4 ;
        RECT 820.608 199.488 820.800 199.512 ;
    END
  END tap[414]
  PIN tap[415]
    DIRECTION INPUT ;
    USE SIGNAL ;
    PORT
      LAYER M4 ;
        RECT 820.608 199.680 820.800 199.704 ;
    END
  END tap[415]
  PIN tap[416]
    DIRECTION INPUT ;
    USE SIGNAL ;
    PORT
      LAYER M4 ;
        RECT 820.608 199.872 820.800 199.896 ;
    END
  END tap[416]
  PIN tap[417]
    DIRECTION INPUT ;
    USE SIGNAL ;
    PORT
      LAYER M4 ;
        RECT 820.608 200.064 820.800 200.088 ;
    END
  END tap[417]
  PIN tap[418]
    DIRECTION INPUT ;
    USE SIGNAL ;
    PORT
      LAYER M4 ;
        RECT 820.608 200.256 820.800 200.280 ;
    END
  END tap[418]
  PIN tap[419]
    DIRECTION INPUT ;
    USE SIGNAL ;
    PORT
      LAYER M4 ;
        RECT 820.608 200.448 820.800 200.472 ;
    END
  END tap[419]
  PIN tap[420]
    DIRECTION INPUT ;
    USE SIGNAL ;
    PORT
      LAYER M4 ;
        RECT 820.608 200.640 820.800 200.664 ;
    END
  END tap[420]
  PIN tap[421]
    DIRECTION INPUT ;
    USE SIGNAL ;
    PORT
      LAYER M4 ;
        RECT 820.608 200.832 820.800 200.856 ;
    END
  END tap[421]
  PIN tap[422]
    DIRECTION INPUT ;
    USE SIGNAL ;
    PORT
      LAYER M4 ;
        RECT 820.608 201.024 820.800 201.048 ;
    END
  END tap[422]
  PIN tap[423]
    DIRECTION INPUT ;
    USE SIGNAL ;
    PORT
      LAYER M4 ;
        RECT 820.608 201.216 820.800 201.240 ;
    END
  END tap[423]
  PIN tap[424]
    DIRECTION INPUT ;
    USE SIGNAL ;
    PORT
      LAYER M4 ;
        RECT 820.608 201.408 820.800 201.432 ;
    END
  END tap[424]
  PIN tap[425]
    DIRECTION INPUT ;
    USE SIGNAL ;
    PORT
      LAYER M4 ;
        RECT 820.608 201.600 820.800 201.624 ;
    END
  END tap[425]
  PIN tap[426]
    DIRECTION INPUT ;
    USE SIGNAL ;
    PORT
      LAYER M4 ;
        RECT 820.608 201.792 820.800 201.816 ;
    END
  END tap[426]
  PIN tap[427]
    DIRECTION INPUT ;
    USE SIGNAL ;
    PORT
      LAYER M4 ;
        RECT 820.608 201.984 820.800 202.008 ;
    END
  END tap[427]
  PIN tap[428]
    DIRECTION INPUT ;
    USE SIGNAL ;
    PORT
      LAYER M4 ;
        RECT 820.608 202.176 820.800 202.200 ;
    END
  END tap[428]
  PIN tap[429]
    DIRECTION INPUT ;
    USE SIGNAL ;
    PORT
      LAYER M4 ;
        RECT 820.608 202.368 820.800 202.392 ;
    END
  END tap[429]
  PIN tap[430]
    DIRECTION INPUT ;
    USE SIGNAL ;
    PORT
      LAYER M4 ;
        RECT 820.608 202.560 820.800 202.584 ;
    END
  END tap[430]
  PIN tap[431]
    DIRECTION INPUT ;
    USE SIGNAL ;
    PORT
      LAYER M4 ;
        RECT 820.608 202.752 820.800 202.776 ;
    END
  END tap[431]
  PIN tap[432]
    DIRECTION INPUT ;
    USE SIGNAL ;
    PORT
      LAYER M4 ;
        RECT 820.608 202.944 820.800 202.968 ;
    END
  END tap[432]
  PIN tap[433]
    DIRECTION INPUT ;
    USE SIGNAL ;
    PORT
      LAYER M4 ;
        RECT 820.608 203.136 820.800 203.160 ;
    END
  END tap[433]
  PIN tap[434]
    DIRECTION INPUT ;
    USE SIGNAL ;
    PORT
      LAYER M4 ;
        RECT 820.608 203.328 820.800 203.352 ;
    END
  END tap[434]
  PIN tap[435]
    DIRECTION INPUT ;
    USE SIGNAL ;
    PORT
      LAYER M4 ;
        RECT 820.608 203.520 820.800 203.544 ;
    END
  END tap[435]
  PIN tap[436]
    DIRECTION INPUT ;
    USE SIGNAL ;
    PORT
      LAYER M4 ;
        RECT 820.608 203.712 820.800 203.736 ;
    END
  END tap[436]
  PIN tap[437]
    DIRECTION INPUT ;
    USE SIGNAL ;
    PORT
      LAYER M4 ;
        RECT 820.608 203.904 820.800 203.928 ;
    END
  END tap[437]
  PIN tap[438]
    DIRECTION INPUT ;
    USE SIGNAL ;
    PORT
      LAYER M4 ;
        RECT 820.608 204.096 820.800 204.120 ;
    END
  END tap[438]
  PIN tap[439]
    DIRECTION INPUT ;
    USE SIGNAL ;
    PORT
      LAYER M4 ;
        RECT 820.608 204.288 820.800 204.312 ;
    END
  END tap[439]
  PIN tap[440]
    DIRECTION INPUT ;
    USE SIGNAL ;
    PORT
      LAYER M4 ;
        RECT 820.608 204.480 820.800 204.504 ;
    END
  END tap[440]
  PIN tap[441]
    DIRECTION INPUT ;
    USE SIGNAL ;
    PORT
      LAYER M4 ;
        RECT 820.608 204.672 820.800 204.696 ;
    END
  END tap[441]
  PIN tap[442]
    DIRECTION INPUT ;
    USE SIGNAL ;
    PORT
      LAYER M4 ;
        RECT 820.608 204.864 820.800 204.888 ;
    END
  END tap[442]
  PIN tap[443]
    DIRECTION INPUT ;
    USE SIGNAL ;
    PORT
      LAYER M4 ;
        RECT 820.608 205.056 820.800 205.080 ;
    END
  END tap[443]
  PIN tap[444]
    DIRECTION INPUT ;
    USE SIGNAL ;
    PORT
      LAYER M4 ;
        RECT 820.608 205.248 820.800 205.272 ;
    END
  END tap[444]
  PIN tap[445]
    DIRECTION INPUT ;
    USE SIGNAL ;
    PORT
      LAYER M4 ;
        RECT 820.608 205.440 820.800 205.464 ;
    END
  END tap[445]
  PIN tap[446]
    DIRECTION INPUT ;
    USE SIGNAL ;
    PORT
      LAYER M4 ;
        RECT 820.608 205.632 820.800 205.656 ;
    END
  END tap[446]
  PIN tap[447]
    DIRECTION INPUT ;
    USE SIGNAL ;
    PORT
      LAYER M4 ;
        RECT 820.608 205.824 820.800 205.848 ;
    END
  END tap[447]
  PIN tap[448]
    DIRECTION INPUT ;
    USE SIGNAL ;
    PORT
      LAYER M4 ;
        RECT 820.608 206.016 820.800 206.040 ;
    END
  END tap[448]
  PIN tap[449]
    DIRECTION INPUT ;
    USE SIGNAL ;
    PORT
      LAYER M4 ;
        RECT 820.608 206.208 820.800 206.232 ;
    END
  END tap[449]
  PIN tap[450]
    DIRECTION INPUT ;
    USE SIGNAL ;
    PORT
      LAYER M4 ;
        RECT 820.608 206.400 820.800 206.424 ;
    END
  END tap[450]
  PIN tap[451]
    DIRECTION INPUT ;
    USE SIGNAL ;
    PORT
      LAYER M4 ;
        RECT 820.608 206.592 820.800 206.616 ;
    END
  END tap[451]
  PIN tap[452]
    DIRECTION INPUT ;
    USE SIGNAL ;
    PORT
      LAYER M4 ;
        RECT 820.608 206.784 820.800 206.808 ;
    END
  END tap[452]
  PIN tap[453]
    DIRECTION INPUT ;
    USE SIGNAL ;
    PORT
      LAYER M4 ;
        RECT 820.608 206.976 820.800 207.000 ;
    END
  END tap[453]
  PIN tap[454]
    DIRECTION INPUT ;
    USE SIGNAL ;
    PORT
      LAYER M4 ;
        RECT 820.608 207.168 820.800 207.192 ;
    END
  END tap[454]
  PIN tap[455]
    DIRECTION INPUT ;
    USE SIGNAL ;
    PORT
      LAYER M4 ;
        RECT 820.608 207.360 820.800 207.384 ;
    END
  END tap[455]
  PIN tap[456]
    DIRECTION INPUT ;
    USE SIGNAL ;
    PORT
      LAYER M4 ;
        RECT 820.608 207.552 820.800 207.576 ;
    END
  END tap[456]
  PIN tap[457]
    DIRECTION INPUT ;
    USE SIGNAL ;
    PORT
      LAYER M4 ;
        RECT 820.608 207.744 820.800 207.768 ;
    END
  END tap[457]
  PIN tap[458]
    DIRECTION INPUT ;
    USE SIGNAL ;
    PORT
      LAYER M4 ;
        RECT 820.608 207.936 820.800 207.960 ;
    END
  END tap[458]
  PIN tap[459]
    DIRECTION INPUT ;
    USE SIGNAL ;
    PORT
      LAYER M4 ;
        RECT 820.608 208.128 820.800 208.152 ;
    END
  END tap[459]
  PIN tap[460]
    DIRECTION INPUT ;
    USE SIGNAL ;
    PORT
      LAYER M4 ;
        RECT 820.608 208.320 820.800 208.344 ;
    END
  END tap[460]
  PIN tap[461]
    DIRECTION INPUT ;
    USE SIGNAL ;
    PORT
      LAYER M4 ;
        RECT 820.608 208.512 820.800 208.536 ;
    END
  END tap[461]
  PIN tap[462]
    DIRECTION INPUT ;
    USE SIGNAL ;
    PORT
      LAYER M4 ;
        RECT 820.608 208.704 820.800 208.728 ;
    END
  END tap[462]
  PIN tap[463]
    DIRECTION INPUT ;
    USE SIGNAL ;
    PORT
      LAYER M4 ;
        RECT 820.608 208.896 820.800 208.920 ;
    END
  END tap[463]
  PIN tap[464]
    DIRECTION INPUT ;
    USE SIGNAL ;
    PORT
      LAYER M4 ;
        RECT 820.608 209.088 820.800 209.112 ;
    END
  END tap[464]
  PIN tap[465]
    DIRECTION INPUT ;
    USE SIGNAL ;
    PORT
      LAYER M4 ;
        RECT 820.608 209.280 820.800 209.304 ;
    END
  END tap[465]
  PIN tap[466]
    DIRECTION INPUT ;
    USE SIGNAL ;
    PORT
      LAYER M4 ;
        RECT 820.608 209.472 820.800 209.496 ;
    END
  END tap[466]
  PIN tap[467]
    DIRECTION INPUT ;
    USE SIGNAL ;
    PORT
      LAYER M4 ;
        RECT 820.608 209.664 820.800 209.688 ;
    END
  END tap[467]
  PIN tap[468]
    DIRECTION INPUT ;
    USE SIGNAL ;
    PORT
      LAYER M4 ;
        RECT 820.608 209.856 820.800 209.880 ;
    END
  END tap[468]
  PIN tap[469]
    DIRECTION INPUT ;
    USE SIGNAL ;
    PORT
      LAYER M4 ;
        RECT 820.608 210.048 820.800 210.072 ;
    END
  END tap[469]
  PIN tap[470]
    DIRECTION INPUT ;
    USE SIGNAL ;
    PORT
      LAYER M4 ;
        RECT 820.608 210.240 820.800 210.264 ;
    END
  END tap[470]
  PIN tap[471]
    DIRECTION INPUT ;
    USE SIGNAL ;
    PORT
      LAYER M4 ;
        RECT 820.608 210.432 820.800 210.456 ;
    END
  END tap[471]
  PIN tap[472]
    DIRECTION INPUT ;
    USE SIGNAL ;
    PORT
      LAYER M4 ;
        RECT 820.608 210.624 820.800 210.648 ;
    END
  END tap[472]
  PIN tap[473]
    DIRECTION INPUT ;
    USE SIGNAL ;
    PORT
      LAYER M4 ;
        RECT 820.608 210.816 820.800 210.840 ;
    END
  END tap[473]
  PIN tap[474]
    DIRECTION INPUT ;
    USE SIGNAL ;
    PORT
      LAYER M4 ;
        RECT 820.608 211.008 820.800 211.032 ;
    END
  END tap[474]
  PIN tap[475]
    DIRECTION INPUT ;
    USE SIGNAL ;
    PORT
      LAYER M4 ;
        RECT 820.608 211.200 820.800 211.224 ;
    END
  END tap[475]
  PIN tap[476]
    DIRECTION INPUT ;
    USE SIGNAL ;
    PORT
      LAYER M4 ;
        RECT 820.608 211.392 820.800 211.416 ;
    END
  END tap[476]
  PIN tap[477]
    DIRECTION INPUT ;
    USE SIGNAL ;
    PORT
      LAYER M4 ;
        RECT 820.608 211.584 820.800 211.608 ;
    END
  END tap[477]
  PIN tap[478]
    DIRECTION INPUT ;
    USE SIGNAL ;
    PORT
      LAYER M4 ;
        RECT 820.608 211.776 820.800 211.800 ;
    END
  END tap[478]
  PIN tap[479]
    DIRECTION INPUT ;
    USE SIGNAL ;
    PORT
      LAYER M4 ;
        RECT 820.608 211.968 820.800 211.992 ;
    END
  END tap[479]
  PIN tap[480]
    DIRECTION INPUT ;
    USE SIGNAL ;
    PORT
      LAYER M4 ;
        RECT 820.608 212.160 820.800 212.184 ;
    END
  END tap[480]
  PIN tap[481]
    DIRECTION INPUT ;
    USE SIGNAL ;
    PORT
      LAYER M4 ;
        RECT 820.608 212.352 820.800 212.376 ;
    END
  END tap[481]
  PIN tap[482]
    DIRECTION INPUT ;
    USE SIGNAL ;
    PORT
      LAYER M4 ;
        RECT 820.608 212.544 820.800 212.568 ;
    END
  END tap[482]
  PIN tap[483]
    DIRECTION INPUT ;
    USE SIGNAL ;
    PORT
      LAYER M4 ;
        RECT 820.608 212.736 820.800 212.760 ;
    END
  END tap[483]
  PIN tap[484]
    DIRECTION INPUT ;
    USE SIGNAL ;
    PORT
      LAYER M4 ;
        RECT 820.608 212.928 820.800 212.952 ;
    END
  END tap[484]
  PIN tap[485]
    DIRECTION INPUT ;
    USE SIGNAL ;
    PORT
      LAYER M4 ;
        RECT 820.608 213.120 820.800 213.144 ;
    END
  END tap[485]
  PIN tap[486]
    DIRECTION INPUT ;
    USE SIGNAL ;
    PORT
      LAYER M4 ;
        RECT 820.608 213.312 820.800 213.336 ;
    END
  END tap[486]
  PIN tap[487]
    DIRECTION INPUT ;
    USE SIGNAL ;
    PORT
      LAYER M4 ;
        RECT 820.608 213.504 820.800 213.528 ;
    END
  END tap[487]
  PIN tap[488]
    DIRECTION INPUT ;
    USE SIGNAL ;
    PORT
      LAYER M4 ;
        RECT 820.608 213.696 820.800 213.720 ;
    END
  END tap[488]
  PIN tap[489]
    DIRECTION INPUT ;
    USE SIGNAL ;
    PORT
      LAYER M4 ;
        RECT 820.608 213.888 820.800 213.912 ;
    END
  END tap[489]
  PIN tap[490]
    DIRECTION INPUT ;
    USE SIGNAL ;
    PORT
      LAYER M4 ;
        RECT 820.608 214.080 820.800 214.104 ;
    END
  END tap[490]
  PIN tap[491]
    DIRECTION INPUT ;
    USE SIGNAL ;
    PORT
      LAYER M4 ;
        RECT 820.608 214.272 820.800 214.296 ;
    END
  END tap[491]
  PIN tap[492]
    DIRECTION INPUT ;
    USE SIGNAL ;
    PORT
      LAYER M4 ;
        RECT 820.608 214.464 820.800 214.488 ;
    END
  END tap[492]
  PIN tap[493]
    DIRECTION INPUT ;
    USE SIGNAL ;
    PORT
      LAYER M4 ;
        RECT 820.608 214.656 820.800 214.680 ;
    END
  END tap[493]
  PIN tap[494]
    DIRECTION INPUT ;
    USE SIGNAL ;
    PORT
      LAYER M4 ;
        RECT 820.608 214.848 820.800 214.872 ;
    END
  END tap[494]
  PIN tap[495]
    DIRECTION INPUT ;
    USE SIGNAL ;
    PORT
      LAYER M4 ;
        RECT 820.608 215.040 820.800 215.064 ;
    END
  END tap[495]
  PIN tap[496]
    DIRECTION INPUT ;
    USE SIGNAL ;
    PORT
      LAYER M4 ;
        RECT 820.608 215.232 820.800 215.256 ;
    END
  END tap[496]
  PIN tap[497]
    DIRECTION INPUT ;
    USE SIGNAL ;
    PORT
      LAYER M4 ;
        RECT 820.608 215.424 820.800 215.448 ;
    END
  END tap[497]
  PIN tap[498]
    DIRECTION INPUT ;
    USE SIGNAL ;
    PORT
      LAYER M4 ;
        RECT 820.608 215.616 820.800 215.640 ;
    END
  END tap[498]
  PIN tap[499]
    DIRECTION INPUT ;
    USE SIGNAL ;
    PORT
      LAYER M4 ;
        RECT 820.608 215.808 820.800 215.832 ;
    END
  END tap[499]
  PIN tap[500]
    DIRECTION INPUT ;
    USE SIGNAL ;
    PORT
      LAYER M4 ;
        RECT 820.608 216.000 820.800 216.024 ;
    END
  END tap[500]
  PIN tap[501]
    DIRECTION INPUT ;
    USE SIGNAL ;
    PORT
      LAYER M4 ;
        RECT 820.608 216.192 820.800 216.216 ;
    END
  END tap[501]
  PIN tap[502]
    DIRECTION INPUT ;
    USE SIGNAL ;
    PORT
      LAYER M4 ;
        RECT 820.608 216.384 820.800 216.408 ;
    END
  END tap[502]
  PIN tap[503]
    DIRECTION INPUT ;
    USE SIGNAL ;
    PORT
      LAYER M4 ;
        RECT 820.608 216.576 820.800 216.600 ;
    END
  END tap[503]
  PIN tap[504]
    DIRECTION INPUT ;
    USE SIGNAL ;
    PORT
      LAYER M4 ;
        RECT 820.608 216.768 820.800 216.792 ;
    END
  END tap[504]
  PIN tap[505]
    DIRECTION INPUT ;
    USE SIGNAL ;
    PORT
      LAYER M4 ;
        RECT 820.608 216.960 820.800 216.984 ;
    END
  END tap[505]
  PIN tap[506]
    DIRECTION INPUT ;
    USE SIGNAL ;
    PORT
      LAYER M4 ;
        RECT 820.608 217.152 820.800 217.176 ;
    END
  END tap[506]
  PIN tap[507]
    DIRECTION INPUT ;
    USE SIGNAL ;
    PORT
      LAYER M4 ;
        RECT 820.608 217.344 820.800 217.368 ;
    END
  END tap[507]
  PIN ck_rs
    DIRECTION INPUT ;
    USE CLOCK ;
    PORT
      LAYER M4 ;
        RECT 820.608 218.016 820.800 218.040 ;
    END
  END ck_rs
  PIN ck_lsl4
    DIRECTION INPUT ;
    USE CLOCK ;
    PORT
      LAYER M4 ;
        RECT 820.608 219.744 820.800 219.768 ;
    END
  END ck_lsl4
  PIN ck_tx4
    DIRECTION INPUT ;
    USE CLOCK ;
    PORT
      LAYER M4 ;
        RECT 820.608 221.184 820.800 221.208 ;
    END
  END ck_tx4
  PIN tile_id[0]
    DIRECTION INPUT ;
    USE SIGNAL ;
    PORT
      LAYER M4 ;
        RECT 820.608 221.952 820.800 221.976 ;
    END
  END tile_id[0]
  PIN tile_id[1]
    DIRECTION INPUT ;
    USE SIGNAL ;
    PORT
      LAYER M4 ;
        RECT 820.608 222.144 820.800 222.168 ;
    END
  END tile_id[1]
  PIN tile_id[2]
    DIRECTION INPUT ;
    USE SIGNAL ;
    PORT
      LAYER M4 ;
        RECT 820.608 222.336 820.800 222.360 ;
    END
  END tile_id[2]
  PIN tile_id[3]
    DIRECTION INPUT ;
    USE SIGNAL ;
    PORT
      LAYER M4 ;
        RECT 820.608 222.528 820.800 222.552 ;
    END
  END tile_id[3]
  PIN tile_id[4]
    DIRECTION INPUT ;
    USE SIGNAL ;
    PORT
      LAYER M4 ;
        RECT 820.608 222.720 820.800 222.744 ;
    END
  END tile_id[4]
  PIN tile_id[5]
    DIRECTION INPUT ;
    USE SIGNAL ;
    PORT
      LAYER M4 ;
        RECT 820.608 222.912 820.800 222.936 ;
    END
  END tile_id[5]
  PIN tile_id[6]
    DIRECTION INPUT ;
    USE SIGNAL ;
    PORT
      LAYER M4 ;
        RECT 820.608 223.104 820.800 223.128 ;
    END
  END tile_id[6]
  PIN tile_id[7]
    DIRECTION INPUT ;
    USE SIGNAL ;
    PORT
      LAYER M4 ;
        RECT 820.608 223.296 820.800 223.320 ;
    END
  END tile_id[7]
  PIN tile_id[8]
    DIRECTION INPUT ;
    USE SIGNAL ;
    PORT
      LAYER M4 ;
        RECT 820.608 223.488 820.800 223.512 ;
    END
  END tile_id[8]
  PIN tile_id[9]
    DIRECTION INPUT ;
    USE SIGNAL ;
    PORT
      LAYER M4 ;
        RECT 820.608 223.680 820.800 223.704 ;
    END
  END tile_id[9]
  PIN tile_id[10]
    DIRECTION INPUT ;
    USE SIGNAL ;
    PORT
      LAYER M4 ;
        RECT 820.608 223.872 820.800 223.896 ;
    END
  END tile_id[10]
  PIN tile_id[11]
    DIRECTION INPUT ;
    USE SIGNAL ;
    PORT
      LAYER M4 ;
        RECT 820.608 224.064 820.800 224.088 ;
    END
  END tile_id[11]
  PIN tile_id[12]
    DIRECTION INPUT ;
    USE SIGNAL ;
    PORT
      LAYER M4 ;
        RECT 820.608 224.256 820.800 224.280 ;
    END
  END tile_id[12]
  PIN tile_id[13]
    DIRECTION INPUT ;
    USE SIGNAL ;
    PORT
      LAYER M4 ;
        RECT 820.608 224.448 820.800 224.472 ;
    END
  END tile_id[13]
  PIN tile_id[14]
    DIRECTION INPUT ;
    USE SIGNAL ;
    PORT
      LAYER M4 ;
        RECT 820.608 224.640 820.800 224.664 ;
    END
  END tile_id[14]
  PIN tile_id[15]
    DIRECTION INPUT ;
    USE SIGNAL ;
    PORT
      LAYER M4 ;
        RECT 820.608 224.832 820.800 224.856 ;
    END
  END tile_id[15]
  PIN rst_n
    DIRECTION INPUT ;
    USE SIGNAL ;
    PORT
      LAYER M4 ;
        RECT 820.608 228.000 820.800 228.024 ;
    END
  END rst_n
  PIN tie_hi
    DIRECTION OUTPUT ;
    USE SIGNAL ;
    PORT
      LAYER M4 ;
        RECT 820.608 232.032 820.800 232.056 ;
    END
  END tie_hi
  PIN tie_lo
    DIRECTION OUTPUT ;
    USE SIGNAL ;
    PORT
      LAYER M4 ;
        RECT 820.608 235.968 820.800 235.992 ;
    END
  END tie_lo
  PIN ck
    DIRECTION INPUT ;
    USE CLOCK ;
    PORT
      LAYER M4 ;
        RECT 820.608 240.000 820.800 240.024 ;
    END
  END ck
  PIN ck_rp6
    DIRECTION INPUT ;
    USE CLOCK ;
    PORT
      LAYER M4 ;
        RECT 820.608 271.104 820.800 271.128 ;
    END
  END ck_rp6
  PIN ck_lsl5
    DIRECTION INPUT ;
    USE CLOCK ;
    PORT
      LAYER M4 ;
        RECT 820.608 366.624 820.800 366.648 ;
    END
  END ck_lsl5
  PIN ck_tx5
    DIRECTION INPUT ;
    USE CLOCK ;
    PORT
      LAYER M4 ;
        RECT 820.608 378.624 820.800 378.648 ;
    END
  END ck_tx5
  PIN ck_de
    DIRECTION INPUT ;
    USE CLOCK ;
    PORT
      LAYER M4 ;
        RECT 820.608 429.984 820.800 430.008 ;
    END
  END ck_de
  PIN ck_rp7
    DIRECTION INPUT ;
    USE CLOCK ;
    PORT
      LAYER M4 ;
        RECT 820.608 443.904 820.800 443.928 ;
    END
  END ck_rp7
  PIN ck_lsl6
    DIRECTION INPUT ;
    USE CLOCK ;
    PORT
      LAYER M4 ;
        RECT 820.608 539.424 820.800 539.448 ;
    END
  END ck_lsl6
  PIN ck_tx6
    DIRECTION INPUT ;
    USE CLOCK ;
    PORT
      LAYER M4 ;
        RECT 820.608 551.424 820.800 551.448 ;
    END
  END ck_tx6
  PIN ck_rp8
    DIRECTION INPUT ;
    USE CLOCK ;
    PORT
      LAYER M4 ;
        RECT 820.608 616.704 820.800 616.728 ;
    END
  END ck_rp8
  PIN ck_rn
    DIRECTION INPUT ;
    USE CLOCK ;
    PORT
      LAYER M4 ;
        RECT 820.608 700.032 820.800 700.056 ;
    END
  END ck_rn
  PIN ck_lsl7
    DIRECTION INPUT ;
    USE CLOCK ;
    PORT
      LAYER M4 ;
        RECT 820.608 712.224 820.800 712.248 ;
    END
  END ck_lsl7
  PIN ck_tx7
    DIRECTION INPUT ;
    USE CLOCK ;
    PORT
      LAYER M4 ;
        RECT 820.608 724.224 820.800 724.248 ;
    END
  END ck_tx7
  PIN ck_rp9
    DIRECTION INPUT ;
    USE CLOCK ;
    PORT
      LAYER M4 ;
        RECT 820.608 789.504 820.800 789.528 ;
    END
  END ck_rp9
  PIN VDD
    DIRECTION INOUT ;
    USE POWER ;
    PORT
      LAYER M7 ;
        RECT 1.000 0.000 1.288 907.200 ;
        RECT 11.800 0.000 12.088 907.200 ;
        RECT 22.600 0.000 22.888 907.200 ;
        RECT 33.400 0.000 33.688 907.200 ;
        RECT 44.200 0.000 44.488 907.200 ;
        RECT 55.000 0.000 55.288 907.200 ;
        RECT 65.800 0.000 66.088 907.200 ;
        RECT 76.600 0.000 76.888 907.200 ;
        RECT 87.400 0.000 87.688 907.200 ;
        RECT 98.200 0.000 98.488 907.200 ;
        RECT 109.000 0.000 109.288 907.200 ;
        RECT 119.800 0.000 120.088 907.200 ;
        RECT 130.600 0.000 130.888 907.200 ;
        RECT 141.400 0.000 141.688 907.200 ;
        RECT 152.200 0.000 152.488 907.200 ;
        RECT 163.000 0.000 163.288 907.200 ;
        RECT 173.800 0.000 174.088 907.200 ;
        RECT 184.600 0.000 184.888 907.200 ;
        RECT 195.400 0.000 195.688 907.200 ;
        RECT 206.200 0.000 206.488 907.200 ;
        RECT 217.000 0.000 217.288 907.200 ;
        RECT 227.800 0.000 228.088 907.200 ;
        RECT 238.600 0.000 238.888 907.200 ;
        RECT 249.400 0.000 249.688 907.200 ;
        RECT 260.200 0.000 260.488 907.200 ;
        RECT 271.000 0.000 271.288 907.200 ;
        RECT 281.800 0.000 282.088 907.200 ;
        RECT 292.600 0.000 292.888 907.200 ;
        RECT 303.400 0.000 303.688 907.200 ;
        RECT 314.200 0.000 314.488 907.200 ;
        RECT 325.000 0.000 325.288 907.200 ;
        RECT 335.800 0.000 336.088 907.200 ;
        RECT 346.600 0.000 346.888 907.200 ;
        RECT 357.400 0.000 357.688 907.200 ;
        RECT 368.200 0.000 368.488 907.200 ;
        RECT 379.000 0.000 379.288 907.200 ;
        RECT 389.800 0.000 390.088 907.200 ;
        RECT 400.600 0.000 400.888 907.200 ;
        RECT 411.400 0.000 411.688 907.200 ;
        RECT 422.200 0.000 422.488 907.200 ;
        RECT 433.000 0.000 433.288 907.200 ;
        RECT 443.800 0.000 444.088 907.200 ;
        RECT 454.600 0.000 454.888 907.200 ;
        RECT 465.400 0.000 465.688 907.200 ;
        RECT 476.200 0.000 476.488 907.200 ;
        RECT 487.000 0.000 487.288 907.200 ;
        RECT 497.800 0.000 498.088 907.200 ;
        RECT 508.600 0.000 508.888 907.200 ;
        RECT 519.400 0.000 519.688 907.200 ;
        RECT 530.200 0.000 530.488 907.200 ;
        RECT 541.000 0.000 541.288 907.200 ;
        RECT 551.800 0.000 552.088 907.200 ;
        RECT 562.600 0.000 562.888 907.200 ;
        RECT 573.400 0.000 573.688 907.200 ;
        RECT 584.200 0.000 584.488 907.200 ;
        RECT 595.000 0.000 595.288 907.200 ;
        RECT 605.800 0.000 606.088 907.200 ;
        RECT 616.600 0.000 616.888 907.200 ;
        RECT 627.400 0.000 627.688 907.200 ;
        RECT 638.200 0.000 638.488 907.200 ;
        RECT 649.000 0.000 649.288 907.200 ;
        RECT 659.800 0.000 660.088 907.200 ;
        RECT 670.600 0.000 670.888 907.200 ;
        RECT 681.400 0.000 681.688 907.200 ;
        RECT 692.200 0.000 692.488 907.200 ;
        RECT 703.000 0.000 703.288 907.200 ;
        RECT 713.800 0.000 714.088 907.200 ;
        RECT 724.600 0.000 724.888 907.200 ;
        RECT 735.400 0.000 735.688 907.200 ;
        RECT 746.200 0.000 746.488 907.200 ;
        RECT 757.000 0.000 757.288 907.200 ;
        RECT 767.800 0.000 768.088 907.200 ;
        RECT 778.600 0.000 778.888 907.200 ;
        RECT 789.400 0.000 789.688 907.200 ;
        RECT 800.200 0.000 800.488 907.200 ;
        RECT 811.000 0.000 811.288 907.200 ;
    END
  END VDD
  PIN VSS
    DIRECTION INOUT ;
    USE GROUND ;
    PORT
      LAYER M7 ;
        RECT 6.400 0.000 6.688 907.200 ;
        RECT 17.200 0.000 17.488 907.200 ;
        RECT 28.000 0.000 28.288 907.200 ;
        RECT 38.800 0.000 39.088 907.200 ;
        RECT 49.600 0.000 49.888 907.200 ;
        RECT 60.400 0.000 60.688 907.200 ;
        RECT 71.200 0.000 71.488 907.200 ;
        RECT 82.000 0.000 82.288 907.200 ;
        RECT 92.800 0.000 93.088 907.200 ;
        RECT 103.600 0.000 103.888 907.200 ;
        RECT 114.400 0.000 114.688 907.200 ;
        RECT 125.200 0.000 125.488 907.200 ;
        RECT 136.000 0.000 136.288 907.200 ;
        RECT 146.800 0.000 147.088 907.200 ;
        RECT 157.600 0.000 157.888 907.200 ;
        RECT 168.400 0.000 168.688 907.200 ;
        RECT 179.200 0.000 179.488 907.200 ;
        RECT 190.000 0.000 190.288 907.200 ;
        RECT 200.800 0.000 201.088 907.200 ;
        RECT 211.600 0.000 211.888 907.200 ;
        RECT 222.400 0.000 222.688 907.200 ;
        RECT 233.200 0.000 233.488 907.200 ;
        RECT 244.000 0.000 244.288 907.200 ;
        RECT 254.800 0.000 255.088 907.200 ;
        RECT 265.600 0.000 265.888 907.200 ;
        RECT 276.400 0.000 276.688 907.200 ;
        RECT 287.200 0.000 287.488 907.200 ;
        RECT 298.000 0.000 298.288 907.200 ;
        RECT 308.800 0.000 309.088 907.200 ;
        RECT 319.600 0.000 319.888 907.200 ;
        RECT 330.400 0.000 330.688 907.200 ;
        RECT 341.200 0.000 341.488 907.200 ;
        RECT 352.000 0.000 352.288 907.200 ;
        RECT 362.800 0.000 363.088 907.200 ;
        RECT 373.600 0.000 373.888 907.200 ;
        RECT 384.400 0.000 384.688 907.200 ;
        RECT 395.200 0.000 395.488 907.200 ;
        RECT 406.000 0.000 406.288 907.200 ;
        RECT 416.800 0.000 417.088 907.200 ;
        RECT 427.600 0.000 427.888 907.200 ;
        RECT 438.400 0.000 438.688 907.200 ;
        RECT 449.200 0.000 449.488 907.200 ;
        RECT 460.000 0.000 460.288 907.200 ;
        RECT 470.800 0.000 471.088 907.200 ;
        RECT 481.600 0.000 481.888 907.200 ;
        RECT 492.400 0.000 492.688 907.200 ;
        RECT 503.200 0.000 503.488 907.200 ;
        RECT 514.000 0.000 514.288 907.200 ;
        RECT 524.800 0.000 525.088 907.200 ;
        RECT 535.600 0.000 535.888 907.200 ;
        RECT 546.400 0.000 546.688 907.200 ;
        RECT 557.200 0.000 557.488 907.200 ;
        RECT 568.000 0.000 568.288 907.200 ;
        RECT 578.800 0.000 579.088 907.200 ;
        RECT 589.600 0.000 589.888 907.200 ;
        RECT 600.400 0.000 600.688 907.200 ;
        RECT 611.200 0.000 611.488 907.200 ;
        RECT 622.000 0.000 622.288 907.200 ;
        RECT 632.800 0.000 633.088 907.200 ;
        RECT 643.600 0.000 643.888 907.200 ;
        RECT 654.400 0.000 654.688 907.200 ;
        RECT 665.200 0.000 665.488 907.200 ;
        RECT 676.000 0.000 676.288 907.200 ;
        RECT 686.800 0.000 687.088 907.200 ;
        RECT 697.600 0.000 697.888 907.200 ;
        RECT 708.400 0.000 708.688 907.200 ;
        RECT 719.200 0.000 719.488 907.200 ;
        RECT 730.000 0.000 730.288 907.200 ;
        RECT 740.800 0.000 741.088 907.200 ;
        RECT 751.600 0.000 751.888 907.200 ;
        RECT 762.400 0.000 762.688 907.200 ;
        RECT 773.200 0.000 773.488 907.200 ;
        RECT 784.000 0.000 784.288 907.200 ;
        RECT 794.800 0.000 795.088 907.200 ;
        RECT 805.600 0.000 805.888 907.200 ;
        RECT 816.400 0.000 816.688 907.200 ;
    END
  END VSS
  OBS
    LAYER M1 ;
      RECT 0.500 0.500 820.300 906.700 ;
    LAYER M2 ;
      RECT 0.500 0.500 820.300 906.700 ;
    LAYER M3 ;
      RECT 0.500 0.500 820.300 906.700 ;
    LAYER M4 ;
      RECT 0.500 0.500 10.800 87.504 ;
      RECT 0.500 109.128 10.800 159.216 ;
      RECT 0.500 180.840 10.800 183.024 ;
      RECT 0.500 216.648 10.800 260.304 ;
      RECT 0.500 281.928 10.800 355.824 ;
      RECT 0.500 389.448 10.800 419.184 ;
      RECT 0.500 454.728 10.800 528.624 ;
      RECT 0.500 562.248 10.800 605.904 ;
      RECT 0.500 627.528 10.800 689.232 ;
      RECT 0.500 735.048 10.800 759.216 ;
      RECT 0.500 884.808 10.800 906.700 ;
      RECT 10.800 0.500 810.000 906.700 ;
      RECT 810.000 0.500 820.300 87.504 ;
      RECT 810.000 250.824 820.300 260.304 ;
      RECT 810.000 281.928 820.300 355.824 ;
      RECT 810.000 389.448 820.300 419.184 ;
      RECT 810.000 454.728 820.300 528.624 ;
      RECT 810.000 562.248 820.300 605.904 ;
      RECT 810.000 627.528 820.300 689.232 ;
      RECT 810.000 735.048 820.300 778.704 ;
      RECT 810.000 800.328 820.300 906.700 ;
    LAYER M5 ;
      RECT 0.500 0.500 10.800 87.504 ;
      RECT 0.500 109.128 10.800 159.216 ;
      RECT 0.500 180.840 10.800 183.024 ;
      RECT 0.500 216.648 10.800 260.304 ;
      RECT 0.500 281.928 10.800 355.824 ;
      RECT 0.500 389.448 10.800 419.184 ;
      RECT 0.500 454.728 10.800 528.624 ;
      RECT 0.500 562.248 10.800 605.904 ;
      RECT 0.500 627.528 10.800 689.232 ;
      RECT 0.500 735.048 10.800 759.216 ;
      RECT 0.500 884.808 10.800 906.700 ;
      RECT 10.800 0.500 810.000 906.700 ;
      RECT 810.000 0.500 820.300 87.504 ;
      RECT 810.000 250.824 820.300 260.304 ;
      RECT 810.000 281.928 820.300 355.824 ;
      RECT 810.000 389.448 820.300 419.184 ;
      RECT 810.000 454.728 820.300 528.624 ;
      RECT 810.000 562.248 820.300 605.904 ;
      RECT 810.000 627.528 820.300 689.232 ;
      RECT 810.000 735.048 820.300 778.704 ;
      RECT 810.000 800.328 820.300 906.700 ;
    LAYER M6 ;
      RECT 0.500 0.500 10.800 87.504 ;
      RECT 0.500 109.128 10.800 159.216 ;
      RECT 0.500 180.840 10.800 183.024 ;
      RECT 0.500 216.648 10.800 260.304 ;
      RECT 0.500 281.928 10.800 355.824 ;
      RECT 0.500 389.448 10.800 419.184 ;
      RECT 0.500 454.728 10.800 528.624 ;
      RECT 0.500 562.248 10.800 605.904 ;
      RECT 0.500 627.528 10.800 689.232 ;
      RECT 0.500 735.048 10.800 759.216 ;
      RECT 0.500 884.808 10.800 906.700 ;
      RECT 10.800 0.500 810.000 906.700 ;
      RECT 810.000 0.500 820.300 87.504 ;
      RECT 810.000 250.824 820.300 260.304 ;
      RECT 810.000 281.928 820.300 355.824 ;
      RECT 810.000 389.448 820.300 419.184 ;
      RECT 810.000 454.728 820.300 528.624 ;
      RECT 810.000 562.248 820.300 605.904 ;
      RECT 810.000 627.528 820.300 689.232 ;
      RECT 810.000 735.048 820.300 778.704 ;
      RECT 810.000 800.328 820.300 906.700 ;
    LAYER M7 ;
      RECT 1.488 0.500 6.200 87.504 ;
      RECT 1.488 109.128 6.200 159.216 ;
      RECT 1.488 180.840 6.200 183.024 ;
      RECT 1.488 216.648 6.200 260.304 ;
      RECT 1.488 281.928 6.200 355.824 ;
      RECT 1.488 389.448 6.200 419.184 ;
      RECT 1.488 454.728 6.200 528.624 ;
      RECT 1.488 562.248 6.200 605.904 ;
      RECT 1.488 627.528 6.200 689.232 ;
      RECT 1.488 735.048 6.200 759.216 ;
      RECT 1.488 884.808 6.200 906.700 ;
      RECT 6.888 0.500 10.800 87.504 ;
      RECT 6.888 109.128 10.800 159.216 ;
      RECT 6.888 180.840 10.800 183.024 ;
      RECT 6.888 216.648 10.800 260.304 ;
      RECT 6.888 281.928 10.800 355.824 ;
      RECT 6.888 389.448 10.800 419.184 ;
      RECT 6.888 454.728 10.800 528.624 ;
      RECT 6.888 562.248 10.800 605.904 ;
      RECT 6.888 627.528 10.800 689.232 ;
      RECT 6.888 735.048 10.800 759.216 ;
      RECT 6.888 884.808 10.800 906.700 ;
      RECT 10.800 0.500 11.600 906.700 ;
      RECT 12.288 0.500 17.000 906.700 ;
      RECT 17.688 0.500 22.400 906.700 ;
      RECT 23.088 0.500 27.800 906.700 ;
      RECT 28.488 0.500 33.200 906.700 ;
      RECT 33.888 0.500 38.600 906.700 ;
      RECT 39.288 0.500 44.000 906.700 ;
      RECT 44.688 0.500 49.400 906.700 ;
      RECT 50.088 0.500 54.800 906.700 ;
      RECT 55.488 0.500 60.200 906.700 ;
      RECT 60.888 0.500 65.600 906.700 ;
      RECT 66.288 0.500 71.000 906.700 ;
      RECT 71.688 0.500 76.400 906.700 ;
      RECT 77.088 0.500 81.800 906.700 ;
      RECT 82.488 0.500 87.200 906.700 ;
      RECT 87.888 0.500 92.600 906.700 ;
      RECT 93.288 0.500 98.000 906.700 ;
      RECT 98.688 0.500 103.400 906.700 ;
      RECT 104.088 0.500 108.800 906.700 ;
      RECT 109.488 0.500 114.200 906.700 ;
      RECT 114.888 0.500 119.600 906.700 ;
      RECT 120.288 0.500 125.000 906.700 ;
      RECT 125.688 0.500 130.400 906.700 ;
      RECT 131.088 0.500 135.800 906.700 ;
      RECT 136.488 0.500 141.200 906.700 ;
      RECT 141.888 0.500 146.600 906.700 ;
      RECT 147.288 0.500 152.000 906.700 ;
      RECT 152.688 0.500 157.400 906.700 ;
      RECT 158.088 0.500 162.800 906.700 ;
      RECT 163.488 0.500 168.200 906.700 ;
      RECT 168.888 0.500 173.600 906.700 ;
      RECT 174.288 0.500 179.000 906.700 ;
      RECT 179.688 0.500 184.400 906.700 ;
      RECT 185.088 0.500 189.800 906.700 ;
      RECT 190.488 0.500 195.200 906.700 ;
      RECT 195.888 0.500 200.600 906.700 ;
      RECT 201.288 0.500 206.000 906.700 ;
      RECT 206.688 0.500 211.400 906.700 ;
      RECT 212.088 0.500 216.800 906.700 ;
      RECT 217.488 0.500 222.200 906.700 ;
      RECT 222.888 0.500 227.600 906.700 ;
      RECT 228.288 0.500 233.000 906.700 ;
      RECT 233.688 0.500 238.400 906.700 ;
      RECT 239.088 0.500 243.800 906.700 ;
      RECT 244.488 0.500 249.200 906.700 ;
      RECT 249.888 0.500 254.600 906.700 ;
      RECT 255.288 0.500 260.000 906.700 ;
      RECT 260.688 0.500 265.400 906.700 ;
      RECT 266.088 0.500 270.800 906.700 ;
      RECT 271.488 0.500 276.200 906.700 ;
      RECT 276.888 0.500 281.600 906.700 ;
      RECT 282.288 0.500 287.000 906.700 ;
      RECT 287.688 0.500 292.400 906.700 ;
      RECT 293.088 0.500 297.800 906.700 ;
      RECT 298.488 0.500 303.200 906.700 ;
      RECT 303.888 0.500 308.600 906.700 ;
      RECT 309.288 0.500 314.000 906.700 ;
      RECT 314.688 0.500 319.400 906.700 ;
      RECT 320.088 0.500 324.800 906.700 ;
      RECT 325.488 0.500 330.200 906.700 ;
      RECT 330.888 0.500 335.600 906.700 ;
      RECT 336.288 0.500 341.000 906.700 ;
      RECT 341.688 0.500 346.400 906.700 ;
      RECT 347.088 0.500 351.800 906.700 ;
      RECT 352.488 0.500 357.200 906.700 ;
      RECT 357.888 0.500 362.600 906.700 ;
      RECT 363.288 0.500 368.000 906.700 ;
      RECT 368.688 0.500 373.400 906.700 ;
      RECT 374.088 0.500 378.800 906.700 ;
      RECT 379.488 0.500 384.200 906.700 ;
      RECT 384.888 0.500 389.600 906.700 ;
      RECT 390.288 0.500 395.000 906.700 ;
      RECT 395.688 0.500 400.400 906.700 ;
      RECT 401.088 0.500 405.800 906.700 ;
      RECT 406.488 0.500 411.200 906.700 ;
      RECT 411.888 0.500 416.600 906.700 ;
      RECT 417.288 0.500 422.000 906.700 ;
      RECT 422.688 0.500 427.400 906.700 ;
      RECT 428.088 0.500 432.800 906.700 ;
      RECT 433.488 0.500 438.200 906.700 ;
      RECT 438.888 0.500 443.600 906.700 ;
      RECT 444.288 0.500 449.000 906.700 ;
      RECT 449.688 0.500 454.400 906.700 ;
      RECT 455.088 0.500 459.800 906.700 ;
      RECT 460.488 0.500 465.200 906.700 ;
      RECT 465.888 0.500 470.600 906.700 ;
      RECT 471.288 0.500 476.000 906.700 ;
      RECT 476.688 0.500 481.400 906.700 ;
      RECT 482.088 0.500 486.800 906.700 ;
      RECT 487.488 0.500 492.200 906.700 ;
      RECT 492.888 0.500 497.600 906.700 ;
      RECT 498.288 0.500 503.000 906.700 ;
      RECT 503.688 0.500 508.400 906.700 ;
      RECT 509.088 0.500 513.800 906.700 ;
      RECT 514.488 0.500 519.200 906.700 ;
      RECT 519.888 0.500 524.600 906.700 ;
      RECT 525.288 0.500 530.000 906.700 ;
      RECT 530.688 0.500 535.400 906.700 ;
      RECT 536.088 0.500 540.800 906.700 ;
      RECT 541.488 0.500 546.200 906.700 ;
      RECT 546.888 0.500 551.600 906.700 ;
      RECT 552.288 0.500 557.000 906.700 ;
      RECT 557.688 0.500 562.400 906.700 ;
      RECT 563.088 0.500 567.800 906.700 ;
      RECT 568.488 0.500 573.200 906.700 ;
      RECT 573.888 0.500 578.600 906.700 ;
      RECT 579.288 0.500 584.000 906.700 ;
      RECT 584.688 0.500 589.400 906.700 ;
      RECT 590.088 0.500 594.800 906.700 ;
      RECT 595.488 0.500 600.200 906.700 ;
      RECT 600.888 0.500 605.600 906.700 ;
      RECT 606.288 0.500 611.000 906.700 ;
      RECT 611.688 0.500 616.400 906.700 ;
      RECT 617.088 0.500 621.800 906.700 ;
      RECT 622.488 0.500 627.200 906.700 ;
      RECT 627.888 0.500 632.600 906.700 ;
      RECT 633.288 0.500 638.000 906.700 ;
      RECT 638.688 0.500 643.400 906.700 ;
      RECT 644.088 0.500 648.800 906.700 ;
      RECT 649.488 0.500 654.200 906.700 ;
      RECT 654.888 0.500 659.600 906.700 ;
      RECT 660.288 0.500 665.000 906.700 ;
      RECT 665.688 0.500 670.400 906.700 ;
      RECT 671.088 0.500 675.800 906.700 ;
      RECT 676.488 0.500 681.200 906.700 ;
      RECT 681.888 0.500 686.600 906.700 ;
      RECT 687.288 0.500 692.000 906.700 ;
      RECT 692.688 0.500 697.400 906.700 ;
      RECT 698.088 0.500 702.800 906.700 ;
      RECT 703.488 0.500 708.200 906.700 ;
      RECT 708.888 0.500 713.600 906.700 ;
      RECT 714.288 0.500 719.000 906.700 ;
      RECT 719.688 0.500 724.400 906.700 ;
      RECT 725.088 0.500 729.800 906.700 ;
      RECT 730.488 0.500 735.200 906.700 ;
      RECT 735.888 0.500 740.600 906.700 ;
      RECT 741.288 0.500 746.000 906.700 ;
      RECT 746.688 0.500 751.400 906.700 ;
      RECT 752.088 0.500 756.800 906.700 ;
      RECT 757.488 0.500 762.200 906.700 ;
      RECT 762.888 0.500 767.600 906.700 ;
      RECT 768.288 0.500 773.000 906.700 ;
      RECT 773.688 0.500 778.400 906.700 ;
      RECT 779.088 0.500 783.800 906.700 ;
      RECT 784.488 0.500 789.200 906.700 ;
      RECT 789.888 0.500 794.600 906.700 ;
      RECT 795.288 0.500 800.000 906.700 ;
      RECT 800.688 0.500 805.400 906.700 ;
      RECT 806.088 0.500 810.000 906.700 ;
      RECT 810.000 0.500 810.800 87.504 ;
      RECT 810.000 250.824 810.800 260.304 ;
      RECT 810.000 281.928 810.800 355.824 ;
      RECT 810.000 389.448 810.800 419.184 ;
      RECT 810.000 454.728 810.800 528.624 ;
      RECT 810.000 562.248 810.800 605.904 ;
      RECT 810.000 627.528 810.800 689.232 ;
      RECT 810.000 735.048 810.800 778.704 ;
      RECT 810.000 800.328 810.800 906.700 ;
      RECT 811.488 0.500 816.200 87.504 ;
      RECT 811.488 250.824 816.200 260.304 ;
      RECT 811.488 281.928 816.200 355.824 ;
      RECT 811.488 389.448 816.200 419.184 ;
      RECT 811.488 454.728 816.200 528.624 ;
      RECT 811.488 562.248 816.200 605.904 ;
      RECT 811.488 627.528 816.200 689.232 ;
      RECT 811.488 735.048 816.200 778.704 ;
      RECT 811.488 800.328 816.200 906.700 ;
      RECT 816.888 0.500 820.300 87.504 ;
      RECT 816.888 250.824 820.300 260.304 ;
      RECT 816.888 281.928 820.300 355.824 ;
      RECT 816.888 389.448 820.300 419.184 ;
      RECT 816.888 454.728 820.300 528.624 ;
      RECT 816.888 562.248 820.300 605.904 ;
      RECT 816.888 627.528 820.300 689.232 ;
      RECT 816.888 735.048 820.300 778.704 ;
      RECT 816.888 800.328 820.300 906.700 ;
  END
END qfd_tile_nl_rp2_romleaf_rr
END LIBRARY
